              <enumeratedValues>
                <enumeratedValue>
                  <name>0</name>
                  <value>1</value>
                </enumeratedValue>
                <enumeratedValue>
                  <name>1</name>
                  <value>2</value>
                </enumeratedValue>
                <enumeratedValue>
                  <name>2</name>
                  <value>4</value>
                </enumeratedValue>
                <enumeratedValue>
                  <name>3</name>
                  <value>8</value>
                </enumeratedValue>
              </enumeratedValues>
            </field>
            <field>
              <name>ETPS</name>
              <bitRange>[13:12]</bitRange>
              <enumeratedValues>
                <enumeratedValue>
                  <name>0</name>
                  <value>1</value>
                </enumeratedValue>
                <enumeratedValue>
                  <name>1</name>
                  <value>2</value>
                </enumeratedValue>
              </enumeratedValues>
            </field>
            <field>
              <name>ECE</name>
              <bitRange>[14:14]</bitRange>
            </field>
            <field>
              <name>ETP</name>
              <bitRange>[15:15]</bitRange>
            </field>
            <field>
              <name>SMS_H</name>
              <bitRange>[16:16]</bitRange>
            </field>
            <field>
              <name>TS_H</name>
              <bitRange>[21:20]</bitRange>
            </field>
            <field>
              <name>SMSPE</name>
              <bitRange>[24:24]</bitRange>
            </field>
            <field>
              <name>SMSPS</name>
              <bitRange>[25:25]</bitRange>
            </field>
          </fields>
        </register>
        <register>
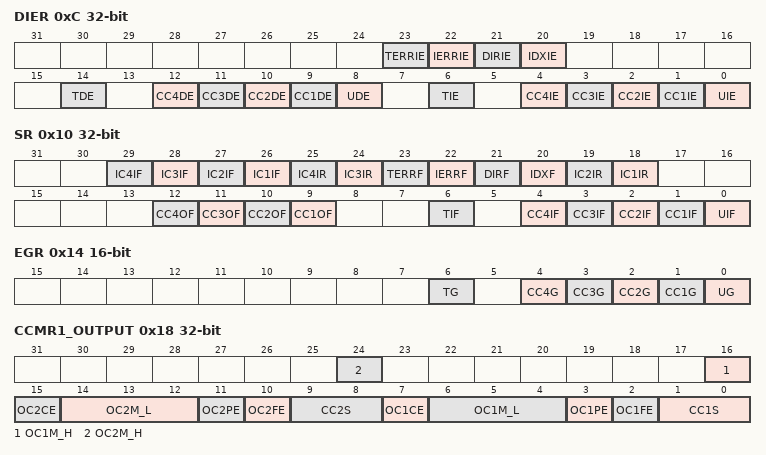
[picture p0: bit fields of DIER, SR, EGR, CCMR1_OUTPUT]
          <name>DIER</name>
          <description>desc DIER</description>
          <addressOffset>0xC</addressOffset>
          <fields>
            <field>
              <name>UIE</name>
              <bitRange>[0:0]</bitRange>
            </field>
            <field>
              <name>CC1IE</name>
              <bitRange>[1:1]</bitRange>
            </field>
            <field>
              <name>CC2IE</name>
              <bitRange>[2:2]</bitRange>
            </field>
            <field>
              <name>CC3IE</name>
              <bitRange>[3:3]</bitRange>
            </field>
            <field>
              <name>CC4IE</name>
              <bitRange>[4:4]</bitRange>
            </field>
            <field>
              <name>TIE</name>
              <bitRange>[6:6]</bitRange>
            </field>
            <field>
              <name>UDE</name>
              <bitRange>[8:8]</bitRange>
            </field>
            <field>
              <name>CC1DE</name>
              <bitRange>[9:9]</bitRange>
            </field>
            <field>
              <name>CC2DE</name>
              <bitRange>[10:10]</bitRange>
            </field>
            <field>
              <name>CC3DE</name>
              <bitRange>[11:11]</bitRange>
            </field>
            <field>
              <name>CC4DE</name>
              <bitRange>[12:12]</bitRange>
            </field>
            <field>
              <name>TDE</name>
              <bitRange>[14:14]</bitRange>
            </field>
            <field>
              <name>IDXIE</name>
              <bitRange>[20:20]</bitRange>
            </field>
            <field>
              <name>DIRIE</name>
              <bitRange>[21:21]</bitRange>
            </field>
            <field>
              <name>IERRIE</name>
              <bitRange>[22:22]</bitRange>
            </field>
            <field>
              <name>TERRIE</name>
              <bitRange>[23:23]</bitRange>
            </field>
          </fields>
        </register>
        <register>
          <name>SR</name>
          <description>desc SR</description>
          <addressOffset>0x10</addressOffset>
          <fields>
            <field>
              <name>UIF</name>
              <bitRange>[0:0]</bitRange>
            </field>
            <field>
              <name>CC1IF</name>
              <bitRange>[1:1]</bitRange>
            </field>
            <field>
              <name>CC2IF</name>
              <bitRange>[2:2]</bitRange>
            </field>
            <field>
              <name>CC3IF</name>
              <bitRange>[3:3]</bitRange>
            </field>
            <field>
              <name>CC4IF</name>
              <bitRange>[4:4]</bitRange>
            </field>
            <field>
              <name>TIF</name>
              <bitRange>[6:6]</bitRange>
            </field>
            <field>
              <name>CC1OF</name>
              <bitRange>[9:9]</bitRange>
            </field>
            <field>
              <name>CC2OF</name>
              <bitRange>[10:10]</bitRange>
            </field>
            <field>
              <name>CC3OF</name>
              <bitRange>[11:11]</bitRange>
            </field>
            <field>
              <name>CC4OF</name>
              <bitRange>[12:12]</bitRange>
            </field>
            <field>
              <name>IC1IR</name>
              <bitRange>[18:18]</bitRange>
            </field>
            <field>
              <name>IC2IR</name>
              <bitRange>[19:19]</bitRange>
            </field>
            <field>
              <name>IDXF</name>
              <bitRange>[20:20]</bitRange>
            </field>
            <field>
              <name>DIRF</name>
              <bitRange>[21:21]</bitRange>
            </field>
            <field>
              <name>IERRF</name>
              <bitRange>[22:22]</bitRange>
            </field>
            <field>
              <name>TERRF</name>
              <bitRange>[23:23]</bitRange>
            </field>
            <field>
              <name>IC3IR</name>
              <bitRange>[24:24]</bitRange>
            </field>
            <field>
              <name>IC4IR</name>
              <bitRange>[25:25]</bitRange>
            </field>
            <field>
              <name>IC1IF</name>
              <bitRange>[26:26]</bitRange>
            </field>
            <field>
              <name>IC2IF</name>
              <bitRange>[27:27]</bitRange>
            </field>
            <field>
              <name>IC3IF</name>
              <bitRange>[28:28]</bitRange>
            </field>
            <field>
              <name>IC4IF</name>
              <bitRange>[29:29]</bitRange>
            </field>
          </fields>
        </register>
        <register>
          <name>EGR</name>
          <description>desc EGR</description>
          <addressOffset>0x14</addressOffset>
          <size>16</size>
          <fields>
            <field>
              <name>UG</name>
              <bitRange>[0:0]</bitRange>
              <access>read-only</access>
            </field>
            <field>
              <name>CC1G</name>
              <bitRange>[1:1]</bitRange>
              <access>read-only</access>
            </field>
            <field>
              <name>CC2G</name>
              <bitRange>[2:2]</bitRange>
              <access>read-only</access>
            </field>
            <field>
              <name>CC3G</name>
              <bitRange>[3:3]</bitRange>
              <access>read-only</access>
            </field>
            <field>
              <name>CC4G</name>
              <bitRange>[4:4]</bitRange>
              <access>read-only</access>
            </field>
            <field>
              <name>TG</name>
              <bitRange>[6:6]</bitRange>
              <access>read-only</access>
            </field>
          </fields>
        </register>
        <register>
          <name>CCMR1_OUTPUT</name>
          <description>desc CCMR1:OUTPUT</description>
          <addressOffset>0x18</addressOffset>
          <fields>
            <field>
              <name>CC1S</name>
              <bitRange>[1:0]</bitRange>
            </field>
            <field>
              <name>OC1FE</name>
              <bitRange>[2:2]</bitRange>
            </field>
            <field>
              <name>OC1PE</name>
              <bitRange>[3:3]</bitRange>
            </field>
            <field>
              <name>OC1M_L</name>
              <bitRange>[6:4]</bitRange>
            </field>
            <field>
              <name>OC1CE</name>
              <bitRange>[7:7]</bitRange>
            </field>
            <field>
              <name>CC2S</name>
              <bitRange>[9:8]</bitRange>
            </field>
            <field>
              <name>OC2FE</name>
              <bitRange>[10:10]</bitRange>
            </field>
            <field>
              <name>OC2PE</name>
              <bitRange>[11:11]</bitRange>
            </field>
            <field>
              <name>OC2M_L</name>
              <bitRange>[14:12]</bitRange>
            </field>
            <field>
              <name>OC2CE</name>
              <bitRange>[15:15]</bitRange>
            </field>
            <field>
              <name>OC1M_H</name>
              <bitRange>[16:16]</bitRange>
            </field>
            <field>
              <name>OC2M_H</name>
              <bitRange>[24:24]</bitRange>
            </field>
          </fields>
        </register>
        <register>
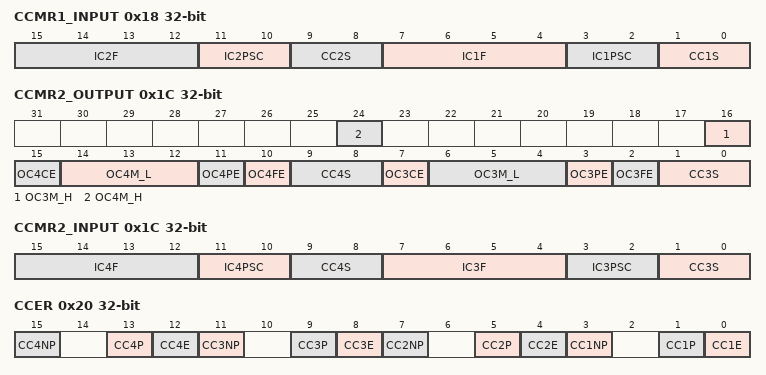
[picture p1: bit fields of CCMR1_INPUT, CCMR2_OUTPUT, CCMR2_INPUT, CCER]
          <name>CCMR1_INPUT</name>
          <description>desc CCMR1:INPUT</description>
          <alternateRegister>CCMR1_OUTPUT</alternateRegister>
          <addressOffset>0x18</addressOffset>
          <fields>
            <field>
              <name>CC1S</name>
              <bitRange>[1:0]</bitRange>
            </field>
            <field>
              <name>IC1PSC</name>
              <bitRange>[3:2]</bitRange>
            </field>
            <field>
              <name>IC1F</name>
              <bitRange>[7:4]</bitRange>
            </field>
            <field>
              <name>CC2S</name>
              <bitRange>[9:8]</bitRange>
            </field>
            <field>
              <name>IC2PSC</name>
              <bitRange>[11:10]</bitRange>
            </field>
            <field>
              <name>IC2F</name>
              <bitRange>[15:12]</bitRange>
            </field>
          </fields>
        </register>
        <register>
          <name>CCMR2_OUTPUT</name>
          <description>desc CCMR2:OUTPUT</description>
          <addressOffset>0x1C</addressOffset>
          <fields>
            <field>
              <name>CC3S</name>
              <bitRange>[1:0]</bitRange>
            </field>
            <field>
              <name>OC3FE</name>
              <bitRange>[2:2]</bitRange>
            </field>
            <field>
              <name>OC3PE</name>
              <bitRange>[3:3]</bitRange>
            </field>
            <field>
              <name>OC3M_L</name>
              <bitRange>[6:4]</bitRange>
            </field>
            <field>
              <name>OC3CE</name>
              <bitRange>[7:7]</bitRange>
            </field>
            <field>
              <name>CC4S</name>
              <bitRange>[9:8]</bitRange>
            </field>
            <field>
              <name>OC4FE</name>
              <bitRange>[10:10]</bitRange>
            </field>
            <field>
              <name>OC4PE</name>
              <bitRange>[11:11]</bitRange>
            </field>
            <field>
              <name>OC4M_L</name>
              <bitRange>[14:12]</bitRange>
            </field>
            <field>
              <name>OC4CE</name>
              <bitRange>[15:15]</bitRange>
            </field>
            <field>
              <name>OC3M_H</name>
              <bitRange>[16:16]</bitRange>
            </field>
            <field>
              <name>OC4M_H</name>
              <bitRange>[24:24]</bitRange>
            </field>
          </fields>
        </register>
        <register>
          <name>CCMR2_INPUT</name>
          <description>desc CCMR2:INPUT</description>
          <alternateRegister>CCMR2_OUTPUT</alternateRegister>
          <addressOffset>0x1C</addressOffset>
          <fields>
            <field>
              <name>CC3S</name>
              <bitRange>[1:0]</bitRange>
            </field>
            <field>
              <name>IC3PSC</name>
              <bitRange>[3:2]</bitRange>
            </field>
            <field>
              <name>IC3F</name>
              <bitRange>[7:4]</bitRange>
            </field>
            <field>
              <name>CC4S</name>
              <bitRange>[9:8]</bitRange>
            </field>
            <field>
              <name>IC4PSC</name>
              <bitRange>[11:10]</bitRange>
            </field>
            <field>
              <name>IC4F</name>
              <bitRange>[15:12]</bitRange>
            </field>
          </fields>
        </register>
        <register>
          <name>CCER</name>
          <description>desc CCER</description>
          <addressOffset>0x20</addressOffset>
          <fields>
            <field>
              <name>CC1E</name>
              <bitRange>[0:0]</bitRange>
            </field>
            <field>
              <name>CC1P</name>
              <bitRange>[1:1]</bitRange>
            </field>
            <field>
              <name>CC1NP</name>
              <bitRange>[3:3]</bitRange>
            </field>
            <field>
              <name>CC2E</name>
              <bitRange>[4:4]</bitRange>
            </field>
            <field>
              <name>CC2P</name>
              <bitRange>[5:5]</bitRange>
            </field>
            <field>
              <name>CC2NP</name>
              <bitRange>[7:7]</bitRange>
            </field>
            <field>
              <name>CC3E</name>
              <bitRange>[8:8]</bitRange>
            </field>
            <field>
              <name>CC3P</name>
              <bitRange>[9:9]</bitRange>
            </field>
            <field>
              <name>CC3NP</name>
              <bitRange>[11:11]</bitRange>
            </field>
            <field>
              <name>CC4E</name>
              <bitRange>[12:12]</bitRange>
            </field>
            <field>
              <name>CC4P</name>
              <bitRange>[13:13]</bitRange>
            </field>
            <field>
              <name>CC4NP</name>
              <bitRange>[15:15]</bitRange>
            </field>
          </fields>
        </register>
        <register>
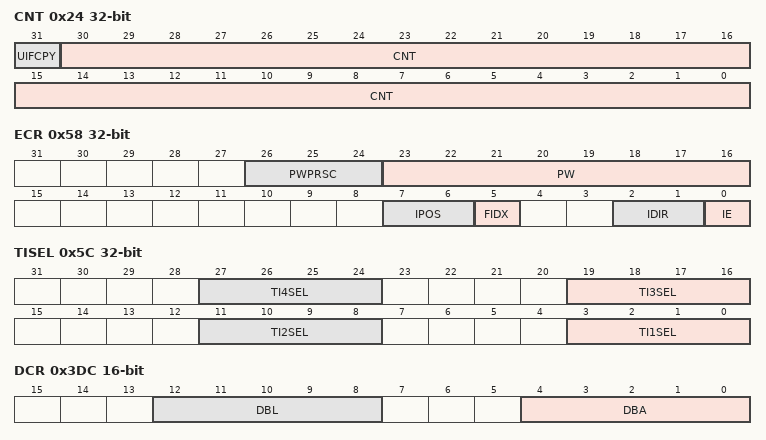
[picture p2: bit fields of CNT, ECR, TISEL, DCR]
          <name>CNT</name>
          <description>desc CNT</description>
          <addressOffset>0x24</addressOffset>
          <fields>
            <field>
              <name>CNT</name>
              <bitRange>[30:0]</bitRange>
            </field>
            <field>
              <name>UIFCPY</name>
              <bitRange>[31:31]</bitRange>
              <access>read-only</access>
            </field>
          </fields>
        </register>
        <register>
          <name>PSC</name>
          <description>desc PSC</description>
          <addressOffset>0x28</addressOffset>
          <fields>
            <field>
              <name>PSC</name>
              <bitRange>[15:0]</bitRange>
            </field>
          </fields>
        </register>
        <register>
          <name>ARR</name>
          <description>desc ARR</description>
          <addressOffset>0x2C</addressOffset>
          <fields>
            <field>
              <name>ARR</name>
              <bitRange>[31:0]</bitRange>
            </field>
          </fields>
        </register>
        <register>
          <name>CCR1</name>
          <description>desc CCR1</description>
          <addressOffset>0x34</addressOffset>
          <fields>
            <field>
              <name>CCR1</name>
              <bitRange>[31:0]</bitRange>
            </field>
          </fields>
        </register>
        <register>
          <name>CCR2</name>
          <description>desc CCR2</description>
          <addressOffset>0x38</addressOffset>
          <fields>
            <field>
              <name>CCR2</name>
              <bitRange>[31:0]</bitRange>
            </field>
          </fields>
        </register>
        <register>
          <name>CCR3</name>
          <description>desc CCR3</description>
          <addressOffset>0x3C</addressOffset>
          <fields>
            <field>
              <name>CCR3</name>
              <bitRange>[31:0]</bitRange>
            </field>
          </fields>
        </register>
        <register>
          <name>CCR4</name>
          <description>desc CCR4</description>
          <addressOffset>0x40</addressOffset>
          <fields>
            <field>
              <name>CCR4</name>
              <bitRange>[31:0]</bitRange>
            </field>
          </fields>
        </register>
        <register>
          <name>ECR</name>
          <addressOffset>0x58</addressOffset>
          <fields>
            <field>
              <name>IE</name>
              <bitRange>[0:0]</bitRange>
            </field>
            <field>
              <name>IDIR</name>
              <bitRange>[2:1]</bitRange>
              <enumeratedValues>
                <enumeratedValue>
                  <name>0</name>
                  <value>1</value>
                </enumeratedValue>
                <enumeratedValue>
                  <name>1</name>
                  <value>2</value>
                </enumeratedValue>
              </enumeratedValues>
            </field>
            <field>
              <name>FIDX</name>
              <bitRange>[5:5]</bitRange>
            </field>
            <field>
              <name>IPOS</name>
              <bitRange>[7:6]</bitRange>
              <enumeratedValues>
                <enumeratedValue>
                  <name>0</name>
                  <value>1</value>
                </enumeratedValue>
                <enumeratedValue>
                  <name>1</name>
                  <value>2</value>
                </enumeratedValue>
              </enumeratedValues>
            </field>
            <field>
              <name>PW</name>
              <bitRange>[23:16]</bitRange>
            </field>
            <field>
              <name>PWPRSC</name>
              <bitRange>[26:24]</bitRange>
              <enumeratedValues>
                <enumeratedValue>
                  <name>0</name>
                  <value>1</value>
                </enumeratedValue>
                <enumeratedValue>
                  <name>1</name>
                  <value>2</value>
                </enumeratedValue>
                <enumeratedValue>
                  <name>2</name>
                  <value>4</value>
                </enumeratedValue>
              </enumeratedValues>
            </field>
          </fields>
        </register>
        <register>
          <name>TISEL</name>
          <addressOffset>0x5C</addressOffset>
          <fields>
            <field>
              <name>TI1SEL</name>
              <bitRange>[3:0]</bitRange>
              <enumeratedValues>
                <enumeratedValue>
                  <name>0</name>
                  <value>1</value>
                </enumeratedValue>
                <enumeratedValue>
                  <name>1</name>
                  <value>2</value>
                </enumeratedValue>
                <enumeratedValue>
                  <name>2</name>
                  <value>4</value>
                </enumeratedValue>
                <enumeratedValue>
                  <name>3</name>
                  <value>8</value>
                </enumeratedValue>
              </enumeratedValues>
            </field>
            <field>
              <name>TI2SEL</name>
              <bitRange>[11:8]</bitRange>
              <enumeratedValues>
                <enumeratedValue>
                  <name>0</name>
                  <value>1</value>
                </enumeratedValue>
                <enumeratedValue>
                  <name>1</name>
                  <value>2</value>
                </enumeratedValue>
                <enumeratedValue>
                  <name>2</name>
                  <value>4</value>
                </enumeratedValue>
                <enumeratedValue>
                  <name>3</name>
                  <value>8</value>
                </enumeratedValue>
              </enumeratedValues>
            </field>
            <field>
              <name>TI3SEL</name>
              <bitRange>[19:16]</bitRange>
              <enumeratedValues>
                <enumeratedValue>
                  <name>0</name>
                  <value>1</value>
                </enumeratedValue>
                <enumeratedValue>
                  <name>1</name>
                  <value>2</value>
                </enumeratedValue>
                <enumeratedValue>
                  <name>2</name>
                  <value>4</value>
                </enumeratedValue>
                <enumeratedValue>
                  <name>3</name>
                  <value>8</value>
                </enumeratedValue>
              </enumeratedValues>
            </field>
            <field>
              <name>TI4SEL</name>
              <bitRange>[27:24]</bitRange>
              <enumeratedValues>
                <enumeratedValue>
                  <name>0</name>
                  <value>1</value>
                </enumeratedValue>
                <enumeratedValue>
                  <name>1</name>
                  <value>2</value>
                </enumeratedValue>
                <enumeratedValue>
                  <name>2</name>
                  <value>4</value>
                </enumeratedValue>
                <enumeratedValue>
                  <name>3</name>
                  <value>8</value>
                </enumeratedValue>
              </enumeratedValues>
            </field>
          </fields>
        </register>
        <register>
          <name>AF1</name>
          <addressOffset>0x60</addressOffset>
          <fields>
            <field>
              <name>ETRSEL</name>
              <bitRange>[17:14]</bitRange>
            </field>
          </fields>
        </register>
        <register>
          <name>AF2</name>
          <addressOffset>0x64</addressOffset>
          <fields>
            <field>
              <name>OCRSEL</name>
              <bitRange>[18:16]</bitRange>
            </field>
          </fields>
        </register>
        <register>
          <name>DCR</name>
          <description>desc DCR</description>
          <addressOffset>0x3DC</addressOffset>
          <size>16</size>
          <fields>
            <field>
              <name>DBA</name>
              <bitRange>[4:0]</bitRange>
              <enumeratedValues>
                <enumeratedValue>
                  <name>0</name>
                  <value>1</value>
                </enumeratedValue>
                <enumeratedValue>
                  <name>1</name>
                  <value>2</value>
                </enumeratedValue>
                <enumeratedValue>
                  <name>2</name>
                  <value>4</value>
                </enumeratedValue>
                <enumeratedValue>
                  <name>3</name>
                  <value>8</value>
                </enumeratedValue>
                <enumeratedValue>
                  <name>4</name>
                  <value>16</value>
                </enumeratedValue>
              </enumeratedValues>
            </field>
            <field>
              <name>DBL</name>
              <bitRange>[12:8]</bitRange>
              <enumeratedValues>
                <enumeratedValue>
                  <name>0</name>
                  <value>1</value>
                </enumeratedValue>
                <enumeratedValue>
                  <name>1</name>
                  <value>2</value>
                </enumeratedValue>
                <enumeratedValue>
                  <name>2</name>
                  <value>4</value>
                </enumeratedValue>
                <enumeratedValue>
                  <name>3</name>
                  <value>8</value>
                </enumeratedValue>
                <enumeratedValue>
                  <name>4</name>
                  <value>16</value>
                </enumeratedValue>
              </enumeratedValues>
            </field>
          </fields>
        </register>
        <register>
          <name>DMAR</name>
          <description>desc DMAR</description>
          <addressOffset>0x3E0</addressOffset>
          <fields>
            <field>
              <name>DMAB</name>
              <bitRange>[31:0]</bitRange>
            </field>
          </fields>
        </register>
      </registers>
    </peripheral>
    <peripheral derivedFrom="TIM2">
      <name>TIM3</name>
      <description>desc TIM</description>
      <baseAddress>0x40000400</baseAddress>
      <interrupt>
        <name>TIM3</name>
        <description>TIM3 global Interrupt</description>
        <value>29</value>
      </interrupt>
    </peripheral>
    <peripheral derivedFrom="TIM2">
      <name>TIM4</name>
      <description>desc TIM</description>
      <baseAddress>0x40000800</baseAddress>
      <interrupt>
        <name>TIM4</name>
        <description>TIM4 global Interrupt</description>
        <value>30</value>
      </interrupt>
    </peripheral>
    <peripheral derivedFrom="TIM2">
      <name>TIM5</name>
      <description>desc TIM</description>
      <baseAddress>0x40000C00</baseAddress>
      <interrupt>
        <name>TIM5</name>
        <description>TIM5 global Interrupt</description>
        <value>50</value>
      </interrupt>
    </peripheral>
    <peripheral>
      <name>TIM6</name>
      <description>desc TIM</description>
      <groupName>TIM</groupName>
      <baseAddress>0x40001000</baseAddress>
      <addressBlock>
        <offset>0x0</offset>
        <size>0x400</size>
        <usage>registers</usage>
      </addressBlock>
      <interrupt>
        <name>TIM6</name>
        <description>TIM6 global Interrupt</description>
        <value>54</value>
      </interrupt>
      <registers>
        <register>
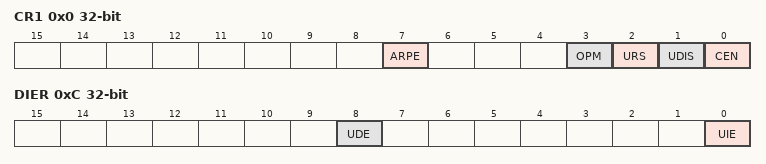
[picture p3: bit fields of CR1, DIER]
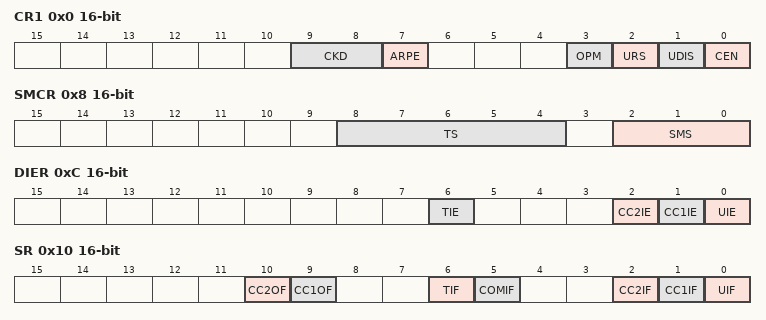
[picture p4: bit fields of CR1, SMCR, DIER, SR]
          <name>CR1</name>
          <description>desc CR1</description>
          <addressOffset>0x0</addressOffset>
          <fields>
            <field>
              <name>CEN</name>
              <bitRange>[0:0]</bitRange>
            </field>
            <field>
              <name>UDIS</name>
              <bitRange>[1:1]</bitRange>
            </field>
            <field>
              <name>URS</name>
              <bitRange>[2:2]</bitRange>
            </field>
            <field>
              <name>OPM</name>
              <bitRange>[3:3]</bitRange>
            </field>
            <field>
              <name>ARPE</name>
              <bitRange>[7:7]</bitRange>
            </field>
          </fields>
        </register>
        <register>
          <name>CR2</name>
          <description>desc CR2</description>
          <addressOffset>0x4</addressOffset>
          <fields>
            <field>
              <name>MMS</name>
              <bitRange>[6:4]</bitRange>
            </field>
          </fields>
        </register>
        <register>
          <name>DIER</name>
          <description>desc DIER</description>
          <addressOffset>0xC</addressOffset>
          <fields>
            <field>
              <name>UIE</name>
              <bitRange>[0:0]</bitRange>
            </field>
            <field>
              <name>UDE</name>
              <bitRange>[8:8]</bitRange>
            </field>
          </fields>
        </register>
        <register>
          <name>SR</name>
          <description>desc SR</description>
          <addressOffset>0x10</addressOffset>
          <fields>
            <field>
              <name>UIF</name>
              <bitRange>[0:0]</bitRange>
            </field>
          </fields>
        </register>
        <register>
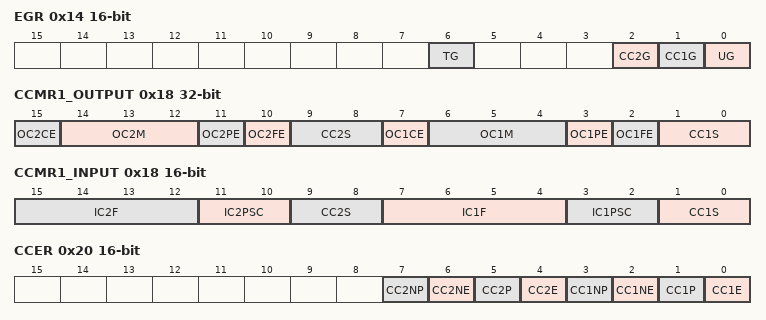
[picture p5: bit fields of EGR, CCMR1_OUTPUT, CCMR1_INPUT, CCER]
          <name>EGR</name>
          <description>desc EGR</description>
          <addressOffset>0x14</addressOffset>
          <fields>
            <field>
              <name>UG</name>
              <bitRange>[0:0]</bitRange>
            </field>
          </fields>
        </register>
        <register>
          <name>CNT</name>
          <description>desc CNT</description>
          <addressOffset>0x24</addressOffset>
          <fields>
            <field>
              <name>CNT</name>
              <bitRange>[15:0]</bitRange>
            </field>
          </fields>
        </register>
        <register>
          <name>PSC</name>
          <description>desc PSC</description>
          <addressOffset>0x28</addressOffset>
          <fields>
            <field>
              <name>PSC</name>
              <bitRange>[15:0]</bitRange>
            </field>
          </fields>
        </register>
        <register>
          <name>ARR</name>
          <description>desc ARR</description>
          <addressOffset>0x2C</addressOffset>
          <fields>
            <field>
              <name>ARR</name>
              <bitRange>[15:0]</bitRange>
            </field>
          </fields>
        </register>
      </registers>
    </peripheral>
    <peripheral derivedFrom="TIM6">
      <name>TIM7</name>
      <description>desc TIM</description>
      <baseAddress>0x40001400</baseAddress>
      <interrupt>
        <name>TIM7</name>
        <description>TIM7 global Interrupt</description>
        <value>55</value>
      </interrupt>
    </peripheral>
    <peripheral derivedFrom="TIM1">
      <name>TIM8</name>
      <baseAddress>0x40013400</baseAddress>
      <interrupt>
        <name>TIM8_BRK_TIM12</name>
        <description>TIM8 Break Interrupt and TIM12 global Interrupt</description>
        <value>43</value>
      </interrupt>
      <interrupt>
        <name>TIM8_UP_TIM13</name>
        <description>TIM8 Update Interrupt and TIM13 global Interrupt</description>
        <value>44</value>
      </interrupt>
      <interrupt>
        <name>TIM8_TRG_COM_TIM14</name>
        <description>TIM8 Trigger and Commutation Interrupt and TIM14 global interrupt</description>
        <value>45</value>
      </interrupt>
      <interrupt>
        <name>TIM8_CC</name>
        <description>TIM8 Capture Compare Interrupt</description>
        <value>46</value>
      </interrupt>
    </peripheral>
    <peripheral>
      <name>TIM9</name>
      <groupName>TIM</groupName>
      <baseAddress>0x40014C00</baseAddress>
      <addressBlock>
        <offset>0x0</offset>
        <size>0x400</size>
        <usage>registers</usage>
      </addressBlock>
      <interrupt>
        <name>TIM1_BRK_TIM9</name>
        <description>TIM1 Break Interrupt and TIM9 global Interrupt</description>
        <value>24</value>
      </interrupt>
      <registers>
        <register>
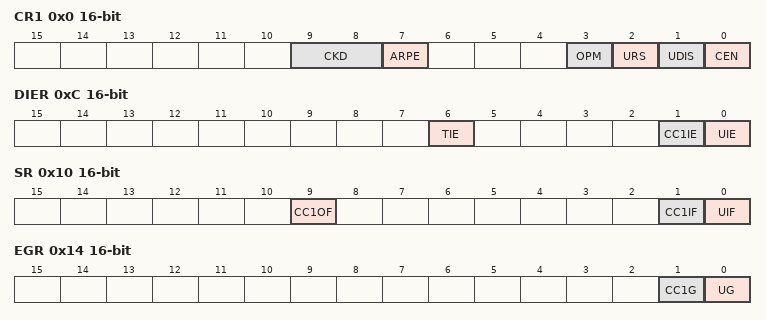
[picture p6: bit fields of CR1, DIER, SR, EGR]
          <name>CR1</name>
          <addressOffset>0x0</addressOffset>
          <size>16</size>
          <fields>
            <field>
              <name>CEN</name>
              <bitRange>[0:0]</bitRange>
            </field>
            <field>
              <name>UDIS</name>
              <bitRange>[1:1]</bitRange>
            </field>
            <field>
              <name>URS</name>
              <bitRange>[2:2]</bitRange>
            </field>
            <field>
              <name>OPM</name>
              <bitRange>[3:3]</bitRange>
            </field>
            <field>
              <name>ARPE</name>
              <bitRange>[7:7]</bitRange>
            </field>
            <field>
              <name>CKD</name>
              <bitRange>[9:8]</bitRange>
              <enumeratedValues>
                <enumeratedValue>
                  <name>0</name>
                  <value>1</value>
                </enumeratedValue>
                <enumeratedValue>
                  <name>1</name>
                  <value>2</value>
                </enumeratedValue>
              </enumeratedValues>
            </field>
          </fields>
        </register>
        <register>
          <name>SMCR</name>
          <addressOffset>0x8</addressOffset>
          <size>16</size>
          <fields>
            <field>
              <name>SMS</name>
              <bitRange>[2:0]</bitRange>
            </field>
            <field>
              <name>TS</name>
              <bitRange>[8:4]</bitRange>
            </field>
          </fields>
        </register>
        <register>
          <name>DIER</name>
          <addressOffset>0xC</addressOffset>
          <size>16</size>
          <fields>
            <field>
              <name>UIE</name>
              <bitRange>[0:0]</bitRange>
            </field>
            <field>
              <name>CC1IE</name>
              <bitRange>[1:1]</bitRange>
            </field>
            <field>
              <name>CC2IE</name>
              <bitRange>[2:2]</bitRange>
            </field>
            <field>
              <name>TIE</name>
              <bitRange>[6:6]</bitRange>
            </field>
          </fields>
        </register>
        <register>
          <name>SR</name>
          <addressOffset>0x10</addressOffset>
          <size>16</size>
          <fields>
            <field>
              <name>UIF</name>
              <bitRange>[0:0]</bitRange>
            </field>
            <field>
              <name>CC1IF</name>
              <bitRange>[1:1]</bitRange>
            </field>
            <field>
              <name>CC2IF</name>
              <bitRange>[2:2]</bitRange>
            </field>
            <field>
              <name>COMIF</name>
              <bitRange>[5:5]</bitRange>
            </field>
            <field>
              <name>TIF</name>
              <bitRange>[6:6]</bitRange>
            </field>
            <field>
              <name>CC1OF</name>
              <bitRange>[9:9]</bitRange>
            </field>
            <field>
              <name>CC2OF</name>
              <bitRange>[10:10]</bitRange>
            </field>
          </fields>
        </register>
        <register>
          <name>EGR</name>
          <addressOffset>0x14</addressOffset>
          <size>16</size>
          <fields>
            <field>
              <name>UG</name>
              <bitRange>[0:0]</bitRange>
            </field>
            <field>
              <name>CC1G</name>
              <bitRange>[1:1]</bitRange>
            </field>
            <field>
              <name>CC2G</name>
              <bitRange>[2:2]</bitRange>
            </field>
            <field>
              <name>TG</name>
              <bitRange>[6:6]</bitRange>
            </field>
          </fields>
        </register>
        <register>
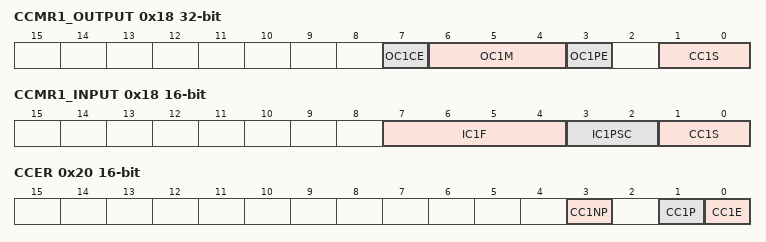
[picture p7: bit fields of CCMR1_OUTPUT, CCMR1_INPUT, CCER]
          <name>CCMR1_OUTPUT</name>
          <addressOffset>0x18</addressOffset>
          <fields>
            <field>
              <name>CC1S</name>
              <bitRange>[1:0]</bitRange>
            </field>
            <field>
              <name>OC1FE</name>
              <bitRange>[2:2]</bitRange>
            </field>
            <field>
              <name>OC1PE</name>
              <bitRange>[3:3]</bitRange>
            </field>
            <field>
              <name>OC1M</name>
              <bitRange>[6:4]</bitRange>
            </field>
            <field>
              <name>OC1CE</name>
              <bitRange>[7:7]</bitRange>
            </field>
            <field>
              <name>CC2S</name>
              <bitRange>[9:8]</bitRange>
            </field>
            <field>
              <name>OC2FE</name>
              <bitRange>[10:10]</bitRange>
            </field>
            <field>
              <name>OC2PE</name>
              <bitRange>[11:11]</bitRange>
            </field>
            <field>
              <name>OC2M</name>
              <bitRange>[14:12]</bitRange>
            </field>
            <field>
              <name>OC2CE</name>
              <bitRange>[15:15]</bitRange>
            </field>
          </fields>
        </register>
        <register>
          <name>CCMR1_INPUT</name>
          <alternateRegister>CCMR1_OUTPUT</alternateRegister>
          <addressOffset>0x18</addressOffset>
          <size>16</size>
          <fields>
            <field>
              <name>CC1S</name>
              <bitRange>[1:0]</bitRange>
            </field>
            <field>
              <name>IC1PSC</name>
              <bitRange>[3:2]</bitRange>
            </field>
            <field>
              <name>IC1F</name>
              <bitRange>[7:4]</bitRange>
            </field>
            <field>
              <name>CC2S</name>
              <bitRange>[9:8]</bitRange>
            </field>
            <field>
              <name>IC2PSC</name>
              <bitRange>[11:10]</bitRange>
            </field>
            <field>
              <name>IC2F</name>
              <bitRange>[15:12]</bitRange>
            </field>
          </fields>
        </register>
        <register>
          <name>CCER</name>
          <addressOffset>0x20</addressOffset>
          <size>16</size>
          <fields>
            <field>
              <name>CC1E</name>
              <bitRange>[0:0]</bitRange>
            </field>
            <field>
              <name>CC1P</name>
              <bitRange>[1:1]</bitRange>
            </field>
            <field>
              <name>CC1NE</name>
              <bitRange>[2:2]</bitRange>
            </field>
            <field>
              <name>CC1NP</name>
              <bitRange>[3:3]</bitRange>
            </field>
            <field>
              <name>CC2E</name>
              <bitRange>[4:4]</bitRange>
            </field>
            <field>
              <name>CC2P</name>
              <bitRange>[5:5]</bitRange>
            </field>
            <field>
              <name>CC2NE</name>
              <bitRange>[6:6]</bitRange>
            </field>
            <field>
              <name>CC2NP</name>
              <bitRange>[7:7]</bitRange>
            </field>
          </fields>
        </register>
        <register>
          <name>CNT</name>
          <addressOffset>0x24</addressOffset>
          <size>16</size>
          <fields>
            <field>
              <name>CNT</name>
              <bitRange>[15:0]</bitRange>
            </field>
          </fields>
        </register>
        <register>
          <name>PSC</name>
          <addressOffset>0x28</addressOffset>
          <size>16</size>
          <fields>
            <field>
              <name>PSC</name>
              <bitRange>[15:0]</bitRange>
            </field>
          </fields>
        </register>
        <register>
          <name>ARR</name>
          <addressOffset>0x2C</addressOffset>
          <size>16</size>
          <fields>
            <field>
              <name>ARR</name>
              <bitRange>[15:0]</bitRange>
            </field>
          </fields>
        </register>
        <register>
          <name>RCR</name>
          <addressOffset>0x30</addressOffset>
          <size>16</size>
          <fields>
            <field>
              <name>REP</name>
              <bitRange>[7:0]</bitRange>
            </field>
          </fields>
        </register>
        <register>
          <name>CCR1</name>
          <addressOffset>0x34</addressOffset>
          <size>16</size>
          <fields>
            <field>
              <name>CCR1</name>
              <bitRange>[15:0]</bitRange>
            </field>
          </fields>
        </register>
        <register>
          <name>CCR2</name>
          <addressOffset>0x38</addressOffset>
          <size>16</size>
          <fields>
            <field>
              <name>CCR2</name>
              <bitRange>[15:0]</bitRange>
            </field>
          </fields>
        </register>
      </registers>
    </peripheral>
    <peripheral>
      <name>TIM10</name>
      <groupName>TIM</groupName>
      <baseAddress>0x40015000</baseAddress>
      <addressBlock>
        <offset>0x0</offset>
        <size>0x400</size>
        <usage>registers</usage>
      </addressBlock>
      <interrupt>
        <name>TIM1_UP_TIM10</name>
        <description>TIM1 Update Interrupt and TIM10 global Interrupt</description>
        <value>25</value>
      </interrupt>
      <registers>
        <register>
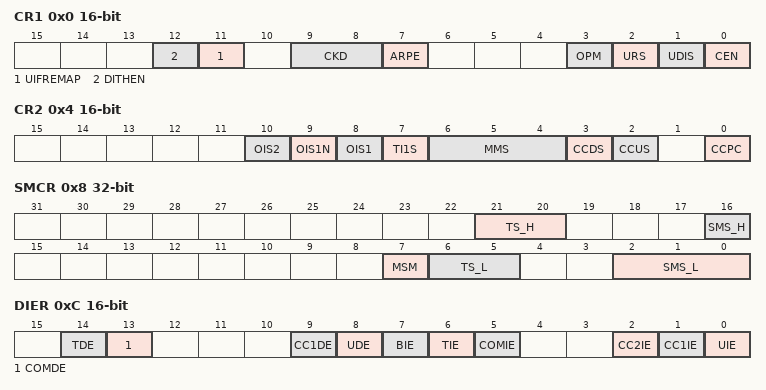
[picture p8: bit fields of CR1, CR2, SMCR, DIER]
          <name>CR1</name>
          <addressOffset>0x0</addressOffset>
          <size>16</size>
          <fields>
            <field>
              <name>CEN</name>
              <bitRange>[0:0]</bitRange>
            </field>
            <field>
              <name>UDIS</name>
              <bitRange>[1:1]</bitRange>
            </field>
            <field>
              <name>URS</name>
              <bitRange>[2:2]</bitRange>
            </field>
            <field>
              <name>OPM</name>
              <bitRange>[3:3]</bitRange>
            </field>
            <field>
              <name>ARPE</name>
              <bitRange>[7:7]</bitRange>
            </field>
            <field>
              <name>CKD</name>
              <bitRange>[9:8]</bitRange>
              <enumeratedValues>
                <enumeratedValue>
                  <name>0</name>
                  <value>1</value>
                </enumeratedValue>
                <enumeratedValue>
                  <name>1</name>
                  <value>2</value>
                </enumeratedValue>
              </enumeratedValues>
            </field>
          </fields>
        </register>
        <register>
          <name>DIER</name>
          <addressOffset>0xC</addressOffset>
          <size>16</size>
          <fields>
            <field>
              <name>UIE</name>
              <bitRange>[0:0]</bitRange>
            </field>
            <field>
              <name>CC1IE</name>
              <bitRange>[1:1]</bitRange>
            </field>
            <field>
              <name>TIE</name>
              <bitRange>[6:6]</bitRange>
            </field>
          </fields>
        </register>
        <register>
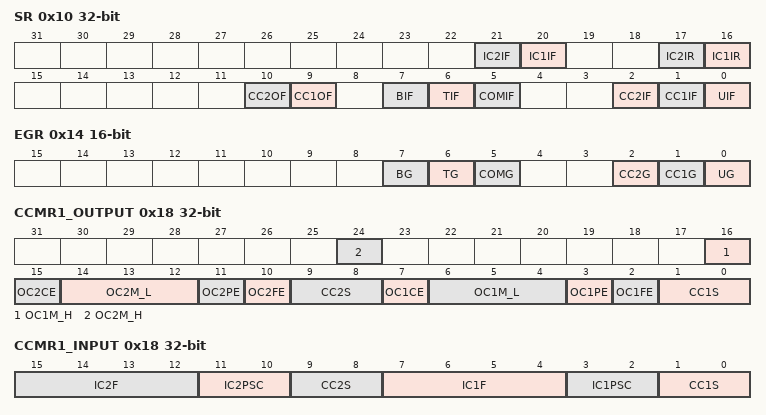
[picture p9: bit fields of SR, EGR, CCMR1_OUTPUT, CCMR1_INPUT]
          <name>SR</name>
          <addressOffset>0x10</addressOffset>
          <size>16</size>
          <fields>
            <field>
              <name>UIF</name>
              <bitRange>[0:0]</bitRange>
            </field>
            <field>
              <name>CC1IF</name>
              <bitRange>[1:1]</bitRange>
            </field>
            <field>
              <name>CC1OF</name>
              <bitRange>[9:9]</bitRange>
            </field>
          </fields>
        </register>
        <register>
          <name>EGR</name>
          <addressOffset>0x14</addressOffset>
          <size>16</size>
          <fields>
            <field>
              <name>UG</name>
              <bitRange>[0:0]</bitRange>
            </field>
            <field>
              <name>CC1G</name>
              <bitRange>[1:1]</bitRange>
            </field>
          </fields>
        </register>
        <register>
          <name>CCMR1_OUTPUT</name>
          <addressOffset>0x18</addressOffset>
          <fields>
            <field>
              <name>CC1S</name>
              <bitRange>[1:0]</bitRange>
            </field>
            <field>
              <name>OC1PE</name>
              <bitRange>[3:3]</bitRange>
            </field>
            <field>
              <name>OC1M</name>
              <bitRange>[6:4]</bitRange>
            </field>
            <field>
              <name>OC1CE</name>
              <bitRange>[7:7]</bitRange>
            </field>
          </fields>
        </register>
        <register>
          <name>CCMR1_INPUT</name>
          <alternateRegister>CCMR1_OUTPUT</alternateRegister>
          <addressOffset>0x18</addressOffset>
          <size>16</size>
          <fields>
            <field>
              <name>CC1S</name>
              <bitRange>[1:0]</bitRange>
            </field>
            <field>
              <name>IC1PSC</name>
              <bitRange>[3:2]</bitRange>
            </field>
            <field>
              <name>IC1F</name>
              <bitRange>[7:4]</bitRange>
            </field>
          </fields>
        </register>
        <register>
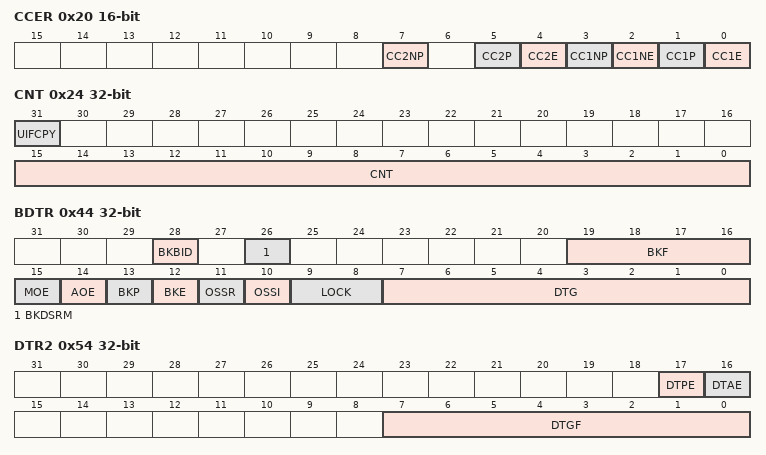
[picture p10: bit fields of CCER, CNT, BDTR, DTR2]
          <name>CCER</name>
          <addressOffset>0x20</addressOffset>
          <size>16</size>
          <fields>
            <field>
              <name>CC1E</name>
              <bitRange>[0:0]</bitRange>
            </field>
            <field>
              <name>CC1P</name>
              <bitRange>[1:1]</bitRange>
            </field>
            <field>
              <name>CC1NP</name>
              <bitRange>[3:3]</bitRange>
            </field>
          </fields>
        </register>
        <register>
          <name>CNT</name>
          <addressOffset>0x24</addressOffset>
          <size>16</size>
          <fields>
            <field>
              <name>CNT</name>
              <bitRange>[15:0]</bitRange>
            </field>
          </fields>
        </register>
        <register>
          <name>PSC</name>
          <addressOffset>0x28</addressOffset>
          <size>16</size>
          <fields>
            <field>
              <name>PSC</name>
              <bitRange>[15:0]</bitRange>
            </field>
          </fields>
        </register>
        <register>
          <name>ARR</name>
          <addressOffset>0x2C</addressOffset>
          <size>16</size>
          <fields>
            <field>
              <name>ARR</name>
              <bitRange>[15:0]</bitRange>
            </field>
          </fields>
        </register>
        <register>
          <name>CCR1</name>
          <addressOffset>0x34</addressOffset>
          <size>16</size>
          <fields>
            <field>
              <name>CCR1</name>
              <bitRange>[15:0]</bitRange>
            </field>
          </fields>
        </register>
        <register>
          <name>OR</name>
          <addressOffset>0x50</addressOffset>
          <size>16</size>
          <fields>
            <field>
              <name>TI1_RMP</name>
              <bitRange>[15:0]</bitRange>
            </field>
          </fields>
        </register>
      </registers>
    </peripheral>
    <peripheral derivedFrom="TIM10">
      <name>TIM11</name>
      <baseAddress>0x40015400</baseAddress>
    </peripheral>
    <peripheral derivedFrom="TIM9">
      <name>TIM12</name>
      <baseAddress>0x40001800</baseAddress>
    </peripheral>
    <peripheral derivedFrom="TIM10">
      <name>TIM13</name>
      <baseAddress>0x40001C00</baseAddress>
    </peripheral>
    <peripheral derivedFrom="TIM10">
      <name>TIM14</name>
      <baseAddress>0x40002000</baseAddress>
    </peripheral>
    <peripheral>
      <name>TIM15</name>
      <groupName>TIM</groupName>
      <baseAddress>0x40015800</baseAddress>
      <addressBlock>
        <offset>0x0</offset>
        <size>0x3F0</size>
        <usage>registers</usage>
      </addressBlock>
      <interrupt>
        <name>TIM15</name>
        <description>TIM15 global Interrupt</description>
        <value>60</value>
      </interrupt>
      <registers>
        <register>
          <name>CR1</name>
          <addressOffset>0x0</addressOffset>
          <size>16</size>
          <fields>
            <field>
              <name>CEN</name>
              <bitRange>[0:0]</bitRange>
            </field>
            <field>
              <name>UDIS</name>
              <bitRange>[1:1]</bitRange>
            </field>
            <field>
              <name>URS</name>
              <bitRange>[2:2]</bitRange>
            </field>
            <field>
              <name>OPM</name>
              <bitRange>[3:3]</bitRange>
            </field>
            <field>
              <name>ARPE</name>
              <bitRange>[7:7]</bitRange>
            </field>
            <field>
              <name>CKD</name>
              <bitRange>[9:8]</bitRange>
              <enumeratedValues>
                <enumeratedValue>
                  <name>0</name>
                  <value>1</value>
                </enumeratedValue>
                <enumeratedValue>
                  <name>1</name>
                  <value>2</value>
                </enumeratedValue>
              </enumeratedValues>
            </field>
            <field>
              <name>UIFREMAP</name>
              <bitRange>[11:11]</bitRange>
            </field>
            <field>
              <name>DITHEN</name>
              <bitRange>[12:12]</bitRange>
            </field>
          </fields>
        </register>
        <register>
          <name>CR2</name>
          <addressOffset>0x4</addressOffset>
          <size>16</size>
          <fields>
            <field>
              <name>CCPC</name>
              <bitRange>[0:0]</bitRange>
            </field>
            <field>
              <name>CCUS</name>
              <bitRange>[2:2]</bitRange>
            </field>
            <field>
              <name>CCDS</name>
              <bitRange>[3:3]</bitRange>
            </field>
            <field>
              <name>MMS</name>
              <bitRange>[6:4]</bitRange>
              <access>read-only</access>
            </field>
            <field>
              <name>TI1S</name>
              <bitRange>[7:7]</bitRange>
            </field>
            <field>
              <name>OIS1</name>
              <bitRange>[8:8]</bitRange>
            </field>
            <field>
              <name>OIS1N</name>
              <bitRange>[9:9]</bitRange>
            </field>
            <field>
              <name>OIS2</name>
              <bitRange>[10:10]</bitRange>
            </field>
          </fields>
        </register>
        <register>
          <name>SMCR</name>
          <addressOffset>0x8</addressOffset>
          <fields>
            <field>
              <name>SMS_L</name>
              <bitRange>[2:0]</bitRange>
            </field>
            <field>
              <name>TS_L</name>
              <bitRange>[6:5]</bitRange>
            </field>
            <field>
              <name>MSM</name>
              <bitRange>[7:7]</bitRange>
            </field>
            <field>
              <name>SMS_H</name>
              <bitRange>[16:16]</bitRange>
            </field>
            <field>
              <name>TS_H</name>
              <bitRange>[21:20]</bitRange>
            </field>
          </fields>
        </register>
        <register>
          <name>DIER</name>
          <addressOffset>0xC</addressOffset>
          <size>16</size>
          <fields>
            <field>
              <name>UIE</name>
              <bitRange>[0:0]</bitRange>
            </field>
            <field>
              <name>CC1IE</name>
              <bitRange>[1:1]</bitRange>
            </field>
            <field>
              <name>CC2IE</name>
              <bitRange>[2:2]</bitRange>
            </field>
            <field>
              <name>COMIE</name>
              <bitRange>[5:5]</bitRange>
            </field>
            <field>
              <name>TIE</name>
              <bitRange>[6:6]</bitRange>
            </field>
            <field>
              <name>BIE</name>
              <bitRange>[7:7]</bitRange>
            </field>
            <field>
              <name>UDE</name>
              <bitRange>[8:8]</bitRange>
            </field>
            <field>
              <name>CC1DE</name>
              <bitRange>[9:9]</bitRange>
            </field>
            <field>
              <name>COMDE</name>
              <bitRange>[13:13]</bitRange>
            </field>
            <field>
              <name>TDE</name>
              <bitRange>[14:14]</bitRange>
            </field>
          </fields>
        </register>
        <register>
          <name>SR</name>
          <addressOffset>0x10</addressOffset>
          <fields>
            <field>
              <name>UIF</name>
              <bitRange>[0:0]</bitRange>
            </field>
            <field>
              <name>CC1IF</name>
              <bitRange>[1:1]</bitRange>
            </field>
            <field>
              <name>CC2IF</name>
              <bitRange>[2:2]</bitRange>
            </field>
            <field>
              <name>COMIF</name>
              <bitRange>[5:5]</bitRange>
            </field>
            <field>
              <name>TIF</name>
              <bitRange>[6:6]</bitRange>
            </field>
            <field>
              <name>BIF</name>
              <bitRange>[7:7]</bitRange>
            </field>
            <field>
              <name>CC1OF</name>
              <bitRange>[9:9]</bitRange>
            </field>
            <field>
              <name>CC2OF</name>
              <bitRange>[10:10]</bitRange>
            </field>
            <field>
              <name>IC1IR</name>
              <bitRange>[16:16]</bitRange>
            </field>
            <field>
              <name>IC2IR</name>
              <bitRange>[17:17]</bitRange>
            </field>
            <field>
              <name>IC1IF</name>
              <bitRange>[20:20]</bitRange>
            </field>
            <field>
              <name>IC2IF</name>
              <bitRange>[21:21]</bitRange>
            </field>
          </fields>
        </register>
        <register>
          <name>EGR</name>
          <addressOffset>0x14</addressOffset>
          <size>16</size>
          <fields>
            <field>
              <name>UG</name>
              <bitRange>[0:0]</bitRange>
              <access>read-only</access>
            </field>
            <field>
              <name>CC1G</name>
              <bitRange>[1:1]</bitRange>
              <access>read-only</access>
            </field>
            <field>
              <name>CC2G</name>
              <bitRange>[2:2]</bitRange>
              <access>read-only</access>
            </field>
            <field>
              <name>COMG</name>
              <bitRange>[5:5]</bitRange>
              <access>read-only</access>
            </field>
            <field>
              <name>TG</name>
              <bitRange>[6:6]</bitRange>
              <access>read-only</access>
            </field>
            <field>
              <name>BG</name>
              <bitRange>[7:7]</bitRange>
              <access>read-only</access>
            </field>
          </fields>
        </register>
        <register>
          <name>CCMR1_OUTPUT</name>
          <addressOffset>0x18</addressOffset>
          <fields>
            <field>
              <name>CC1S</name>
              <bitRange>[1:0]</bitRange>
            </field>
            <field>
              <name>OC1FE</name>
              <bitRange>[2:2]</bitRange>
            </field>
            <field>
              <name>OC1PE</name>
              <bitRange>[3:3]</bitRange>
            </field>
            <field>
              <name>OC1M_L</name>
              <bitRange>[6:4]</bitRange>
            </field>
            <field>
              <name>OC1CE</name>
              <bitRange>[7:7]</bitRange>
            </field>
            <field>
              <name>CC2S</name>
              <bitRange>[9:8]</bitRange>
            </field>
            <field>
              <name>OC2FE</name>
              <bitRange>[10:10]</bitRange>
            </field>
            <field>
              <name>OC2PE</name>
              <bitRange>[11:11]</bitRange>
            </field>
            <field>
              <name>OC2M_L</name>
              <bitRange>[14:12]</bitRange>
            </field>
            <field>
              <name>OC2CE</name>
              <bitRange>[15:15]</bitRange>
            </field>
            <field>
              <name>OC1M_H</name>
              <bitRange>[16:16]</bitRange>
            </field>
            <field>
              <name>OC2M_H</name>
              <bitRange>[24:24]</bitRange>
            </field>
          </fields>
        </register>
        <register>
          <name>CCMR1_INPUT</name>
          <alternateRegister>CCMR1_OUTPUT</alternateRegister>
          <addressOffset>0x18</addressOffset>
          <fields>
            <field>
              <name>CC1S</name>
              <bitRange>[1:0]</bitRange>
            </field>
            <field>
              <name>IC1PSC</name>
              <bitRange>[3:2]</bitRange>
            </field>
            <field>
              <name>IC1F</name>
              <bitRange>[7:4]</bitRange>
            </field>
            <field>
              <name>CC2S</name>
              <bitRange>[9:8]</bitRange>
            </field>
            <field>
              <name>IC2PSC</name>
              <bitRange>[11:10]</bitRange>
            </field>
            <field>
              <name>IC2F</name>
              <bitRange>[15:12]</bitRange>
            </field>
          </fields>
        </register>
        <register>
          <name>CCER</name>
          <addressOffset>0x20</addressOffset>
          <size>16</size>
          <fields>
            <field>
              <name>CC1E</name>
              <bitRange>[0:0]</bitRange>
            </field>
            <field>
              <name>CC1P</name>
              <bitRange>[1:1]</bitRange>
            </field>
            <field>
              <name>CC1NE</name>
              <bitRange>[2:2]</bitRange>
            </field>
            <field>
              <name>CC1NP</name>
              <bitRange>[3:3]</bitRange>
            </field>
            <field>
              <name>CC2E</name>
              <bitRange>[4:4]</bitRange>
            </field>
            <field>
              <name>CC2P</name>
              <bitRange>[5:5]</bitRange>
            </field>
            <field>
              <name>CC2NP</name>
              <bitRange>[7:7]</bitRange>
            </field>
          </fields>
        </register>
        <register>
          <name>CNT</name>
          <addressOffset>0x24</addressOffset>
          <fields>
            <field>
              <name>CNT</name>
              <bitRange>[15:0]</bitRange>
            </field>
            <field>
              <name>UIFCPY</name>
              <bitRange>[31:31]</bitRange>
              <access>read-only</access>
            </field>
          </fields>
        </register>
        <register>
          <name>PSC</name>
          <addressOffset>0x28</addressOffset>
          <fields>
            <field>
              <name>PSC</name>
              <bitRange>[15:0]</bitRange>
            </field>
          </fields>
        </register>
        <register>
          <name>ARR</name>
          <addressOffset>0x2C</addressOffset>
          <fields>
            <field>
              <name>ARR</name>
              <bitRange>[19:0]</bitRange>
            </field>
          </fields>
        </register>
        <register>
          <name>RCR</name>
          <addressOffset>0x30</addressOffset>
          <fields>
            <field>
              <name>REP</name>
              <bitRange>[7:0]</bitRange>
            </field>
          </fields>
        </register>
        <register>
          <name>CCR1</name>
          <addressOffset>0x34</addressOffset>
          <fields>
            <field>
              <name>CCR1</name>
              <bitRange>[19:0]</bitRange>
            </field>
          </fields>
        </register>
        <register>
          <name>CCR2</name>
          <addressOffset>0x38</addressOffset>
          <fields>
            <field>
              <name>CCR2</name>
              <bitRange>[19:0]</bitRange>
            </field>
          </fields>
        </register>
        <register>
          <name>BDTR</name>
          <addressOffset>0x44</addressOffset>
          <fields>
            <field>
              <name>DTG</name>
              <bitRange>[7:0]</bitRange>
            </field>
            <field>
              <name>LOCK</name>
              <bitRange>[9:8]</bitRange>
              <enumeratedValues>
                <enumeratedValue>
                  <name>0</name>
                  <value>1</value>
                </enumeratedValue>
                <enumeratedValue>
                  <name>1</name>
                  <value>2</value>
                </enumeratedValue>
              </enumeratedValues>
            </field>
            <field>
              <name>OSSI</name>
              <bitRange>[10:10]</bitRange>
            </field>
            <field>
              <name>OSSR</name>
              <bitRange>[11:11]</bitRange>
            </field>
            <field>
              <name>BKE</name>
              <bitRange>[12:12]</bitRange>
            </field>
            <field>
              <name>BKP</name>
              <bitRange>[13:13]</bitRange>
            </field>
            <field>
              <name>AOE</name>
              <bitRange>[14:14]</bitRange>
            </field>
            <field>
              <name>MOE</name>
              <bitRange>[15:15]</bitRange>
            </field>
            <field>
              <name>BKF</name>
              <bitRange>[19:16]</bitRange>
              <enumeratedValues>
                <enumeratedValue>
                  <name>0</name>
                  <value>1</value>
                </enumeratedValue>
                <enumeratedValue>
                  <name>1</name>
                  <value>2</value>
                </enumeratedValue>
                <enumeratedValue>
                  <name>2</name>
                  <value>4</value>
                </enumeratedValue>
                <enumeratedValue>
                  <name>3</name>
                  <value>8</value>
                </enumeratedValue>
              </enumeratedValues>
            </field>
            <field>
              <name>BKDSRM</name>
              <bitRange>[26:26]</bitRange>
            </field>
            <field>
              <name>BKBID</name>
              <bitRange>[28:28]</bitRange>
            </field>
          </fields>
        </register>
        <register>
          <name>DTR2</name>
          <addressOffset>0x54</addressOffset>
          <fields>
            <field>
              <name>DTGF</name>
              <bitRange>[7:0]</bitRange>
            </field>
            <field>
              <name>DTAE</name>
              <bitRange>[16:16]</bitRange>
            </field>
            <field>
              <name>DTPE</name>
              <bitRange>[17:17]</bitRange>
            </field>
          </fields>
        </register>
        <register>
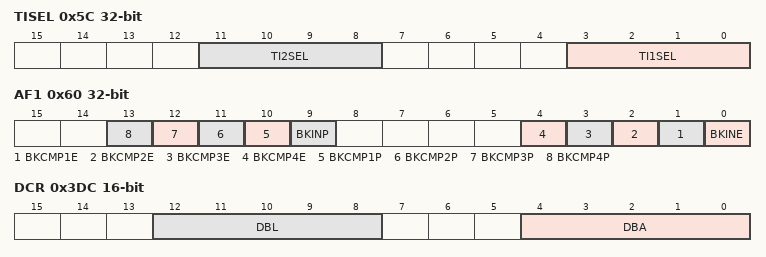
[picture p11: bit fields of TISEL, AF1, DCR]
          <name>TISEL</name>
          <addressOffset>0x5C</addressOffset>
          <fields>
            <field>
              <name>TI1SEL</name>
              <bitRange>[3:0]</bitRange>
              <enumeratedValues>
                <enumeratedValue>
                  <name>0</name>
                  <value>1</value>
                </enumeratedValue>
                <enumeratedValue>
                  <name>1</name>
                  <value>2</value>
                </enumeratedValue>
                <enumeratedValue>
                  <name>2</name>
                  <value>4</value>
                </enumeratedValue>
                <enumeratedValue>
                  <name>3</name>
                  <value>8</value>
                </enumeratedValue>
              </enumeratedValues>
            </field>
            <field>
              <name>TI2SEL</name>
              <bitRange>[11:8]</bitRange>
              <enumeratedValues>
                <enumeratedValue>
                  <name>0</name>
                  <value>1</value>
                </enumeratedValue>
                <enumeratedValue>
                  <name>1</name>
                  <value>2</value>
                </enumeratedValue>
                <enumeratedValue>
                  <name>2</name>
                  <value>4</value>
                </enumeratedValue>
                <enumeratedValue>
                  <name>3</name>
                  <value>8</value>
                </enumeratedValue>
              </enumeratedValues>
            </field>
          </fields>
        </register>
        <register>
          <name>AF1</name>
          <addressOffset>0x60</addressOffset>
          <fields>
            <field>
              <name>BKINE</name>
              <bitRange>[0:0]</bitRange>
            </field>
            <field>
              <name>BKCMP1E</name>
              <bitRange>[1:1]</bitRange>
            </field>
            <field>
              <name>BKCMP2E</name>
              <bitRange>[2:2]</bitRange>
            </field>
            <field>
              <name>BKCMP3E</name>
              <bitRange>[3:3]</bitRange>
            </field>
            <field>
              <name>BKCMP4E</name>
              <bitRange>[4:4]</bitRange>
            </field>
            <field>
              <name>BKINP</name>
              <bitRange>[9:9]</bitRange>
            </field>
            <field>
              <name>BKCMP1P</name>
              <bitRange>[10:10]</bitRange>
            </field>
            <field>
              <name>BKCMP2P</name>
              <bitRange>[11:11]</bitRange>
            </field>
            <field>
              <name>BKCMP3P</name>
              <bitRange>[12:12]</bitRange>
            </field>
            <field>
              <name>BKCMP4P</name>
              <bitRange>[13:13]</bitRange>
            </field>
          </fields>
        </register>
        <register>
          <name>AF2</name>
          <addressOffset>0x64</addressOffset>
          <fields>
            <field>
              <name>OCRSEL</name>
              <bitRange>[18:16]</bitRange>
            </field>
          </fields>
        </register>
        <register>
          <name>DCR</name>
          <addressOffset>0x3DC</addressOffset>
          <size>16</size>
          <fields>
            <field>
              <name>DBA</name>
              <bitRange>[4:0]</bitRange>
              <enumeratedValues>
                <enumeratedValue>
                  <name>0</name>
                  <value>1</value>
                </enumeratedValue>
                <enumeratedValue>
                  <name>1</name>
                  <value>2</value>
                </enumeratedValue>
                <enumeratedValue>
                  <name>2</name>
                  <value>4</value>
                </enumeratedValue>
                <enumeratedValue>
                  <name>3</name>
                  <value>8</value>
                </enumeratedValue>
                <enumeratedValue>
                  <name>4</name>
                  <value>16</value>
                </enumeratedValue>
              </enumeratedValues>
            </field>
            <field>
              <name>DBL</name>
              <bitRange>[12:8]</bitRange>
              <enumeratedValues>
                <enumeratedValue>
                  <name>0</name>
                  <value>1</value>
                </enumeratedValue>
                <enumeratedValue>
                  <name>1</name>
                  <value>2</value>
                </enumeratedValue>
                <enumeratedValue>
                  <name>2</name>
                  <value>4</value>
                </enumeratedValue>
                <enumeratedValue>
                  <name>3</name>
                  <value>8</value>
                </enumeratedValue>
                <enumeratedValue>
                  <name>4</name>
                  <value>16</value>
                </enumeratedValue>
              </enumeratedValues>
            </field>
          </fields>
        </register>
        <register>
          <name>DMAR</name>
          <addressOffset>0x3E0</addressOffset>
          <fields>
            <field>
              <name>DMAB</name>
              <bitRange>[31:0]</bitRange>
            </field>
          </fields>
        </register>
      </registers>
    </peripheral>
    <peripheral>
      <name>TIM16</name>
      <groupName>TIM</groupName>
      <baseAddress>0x40015C00</baseAddress>
      <addressBlock>
        <offset>0x0</offset>
        <size>0x3F0</size>
        <usage>registers</usage>
      </addressBlock>
      <interrupt>
        <name>TIM16</name>
        <description>TIM16 global Interrupt</description>
        <value>61</value>
      </interrupt>
      <registers>
        <register>
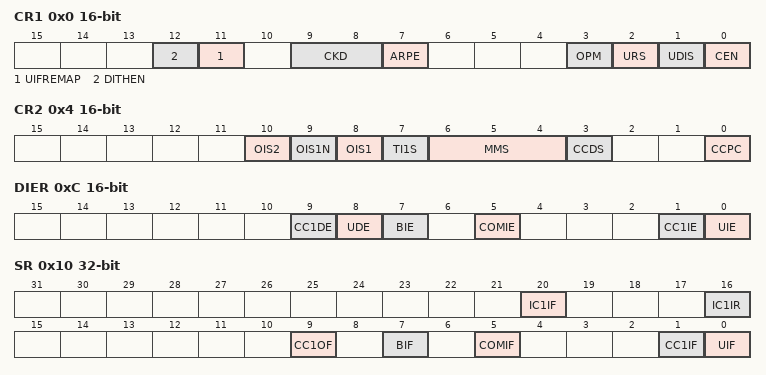
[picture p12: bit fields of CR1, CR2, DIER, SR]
          <name>CR1</name>
          <addressOffset>0x0</addressOffset>
          <size>16</size>
          <fields>
            <field>
              <name>CEN</name>
              <bitRange>[0:0]</bitRange>
            </field>
            <field>
              <name>UDIS</name>
              <bitRange>[1:1]</bitRange>
            </field>
            <field>
              <name>URS</name>
              <bitRange>[2:2]</bitRange>
            </field>
            <field>
              <name>OPM</name>
              <bitRange>[3:3]</bitRange>
            </field>
            <field>
              <name>ARPE</name>
              <bitRange>[7:7]</bitRange>
            </field>
            <field>
              <name>CKD</name>
              <bitRange>[9:8]</bitRange>
              <enumeratedValues>
                <enumeratedValue>
                  <name>0</name>
                  <value>1</value>
                </enumeratedValue>
                <enumeratedValue>
                  <name>1</name>
                  <value>2</value>
                </enumeratedValue>
              </enumeratedValues>
            </field>
            <field>
              <name>UIFREMAP</name>
              <bitRange>[11:11]</bitRange>
            </field>
            <field>
              <name>DITHEN</name>
              <bitRange>[12:12]</bitRange>
            </field>
          </fields>
        </register>
        <register>
          <name>CR2</name>
          <addressOffset>0x4</addressOffset>
          <size>16</size>
          <fields>
            <field>
              <name>CCPC</name>
              <bitRange>[0:0]</bitRange>
            </field>
            <field>
              <name>CCDS</name>
              <bitRange>[3:3]</bitRange>
            </field>
            <field>
              <name>MMS</name>
              <bitRange>[6:4]</bitRange>
              <access>read-only</access>
            </field>
            <field>
              <name>TI1S</name>
              <bitRange>[7:7]</bitRange>
            </field>
            <field>
              <name>OIS1</name>
              <bitRange>[8:8]</bitRange>
            </field>
            <field>
              <name>OIS1N</name>
              <bitRange>[9:9]</bitRange>
            </field>
            <field>
              <name>OIS2</name>
              <bitRange>[10:10]</bitRange>
            </field>
          </fields>
        </register>
        <register>
          <name>DIER</name>
          <addressOffset>0xC</addressOffset>
          <size>16</size>
          <fields>
            <field>
              <name>UIE</name>
              <bitRange>[0:0]</bitRange>
            </field>
            <field>
              <name>CC1IE</name>
              <bitRange>[1:1]</bitRange>
            </field>
            <field>
              <name>COMIE</name>
              <bitRange>[5:5]</bitRange>
            </field>
            <field>
              <name>BIE</name>
              <bitRange>[7:7]</bitRange>
            </field>
            <field>
              <name>UDE</name>
              <bitRange>[8:8]</bitRange>
            </field>
            <field>
              <name>CC1DE</name>
              <bitRange>[9:9]</bitRange>
            </field>
          </fields>
        </register>
        <register>
          <name>SR</name>
          <addressOffset>0x10</addressOffset>
          <fields>
            <field>
              <name>UIF</name>
              <bitRange>[0:0]</bitRange>
            </field>
            <field>
              <name>CC1IF</name>
              <bitRange>[1:1]</bitRange>
            </field>
            <field>
              <name>COMIF</name>
              <bitRange>[5:5]</bitRange>
            </field>
            <field>
              <name>BIF</name>
              <bitRange>[7:7]</bitRange>
            </field>
            <field>
              <name>CC1OF</name>
              <bitRange>[9:9]</bitRange>
            </field>
            <field>
              <name>IC1IR</name>
              <bitRange>[16:16]</bitRange>
            </field>
            <field>
              <name>IC1IF</name>
              <bitRange>[20:20]</bitRange>
            </field>
          </fields>
        </register>
        <register>
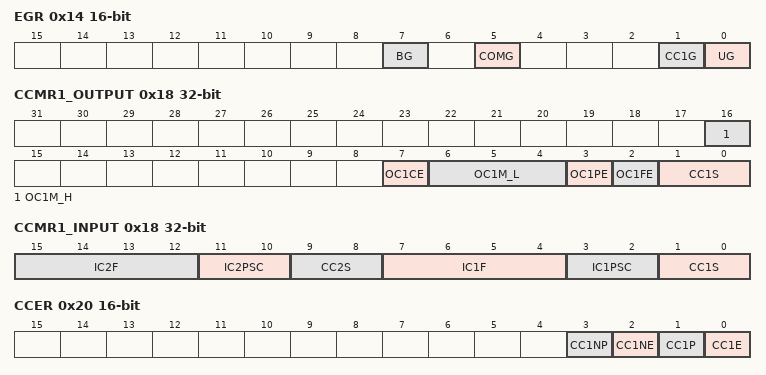
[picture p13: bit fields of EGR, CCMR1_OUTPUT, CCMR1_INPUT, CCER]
          <name>EGR</name>
          <addressOffset>0x14</addressOffset>
          <size>16</size>
          <fields>
            <field>
              <name>UG</name>
              <bitRange>[0:0]</bitRange>
              <access>read-only</access>
            </field>
            <field>
              <name>CC1G</name>
              <bitRange>[1:1]</bitRange>
              <access>read-only</access>
            </field>
            <field>
              <name>COMG</name>
              <bitRange>[5:5]</bitRange>
              <access>read-only</access>
            </field>
            <field>
              <name>BG</name>
              <bitRange>[7:7]</bitRange>
              <access>read-only</access>
            </field>
          </fields>
        </register>
        <register>
          <name>CCMR1_OUTPUT</name>
          <addressOffset>0x18</addressOffset>
          <fields>
            <field>
              <name>CC1S</name>
              <bitRange>[1:0]</bitRange>
            </field>
            <field>
              <name>OC1FE</name>
              <bitRange>[2:2]</bitRange>
            </field>
            <field>
              <name>OC1PE</name>
              <bitRange>[3:3]</bitRange>
            </field>
            <field>
              <name>OC1M_L</name>
              <bitRange>[6:4]</bitRange>
            </field>
            <field>
              <name>OC1CE</name>
              <bitRange>[7:7]</bitRange>
            </field>
            <field>
              <name>OC1M_H</name>
              <bitRange>[16:16]</bitRange>
            </field>
          </fields>
        </register>
        <register>
          <name>CCMR1_INPUT</name>
          <alternateRegister>CCMR1_OUTPUT</alternateRegister>
          <addressOffset>0x18</addressOffset>
          <fields>
            <field>
              <name>CC1S</name>
              <bitRange>[1:0]</bitRange>
            </field>
            <field>
              <name>IC1PSC</name>
              <bitRange>[3:2]</bitRange>
            </field>
            <field>
              <name>IC1F</name>
              <bitRange>[7:4]</bitRange>
            </field>
            <field>
              <name>CC2S</name>
              <bitRange>[9:8]</bitRange>
            </field>
            <field>
              <name>IC2PSC</name>
              <bitRange>[11:10]</bitRange>
            </field>
            <field>
              <name>IC2F</name>
              <bitRange>[15:12]</bitRange>
            </field>
          </fields>
        </register>
        <register>
          <name>CCER</name>
          <addressOffset>0x20</addressOffset>
          <size>16</size>
          <fields>
            <field>
              <name>CC1E</name>
              <bitRange>[0:0]</bitRange>
            </field>
            <field>
              <name>CC1P</name>
              <bitRange>[1:1]</bitRange>
            </field>
            <field>
              <name>CC1NE</name>
              <bitRange>[2:2]</bitRange>
            </field>
            <field>
              <name>CC1NP</name>
              <bitRange>[3:3]</bitRange>
            </field>
          </fields>
        </register>
        <register>
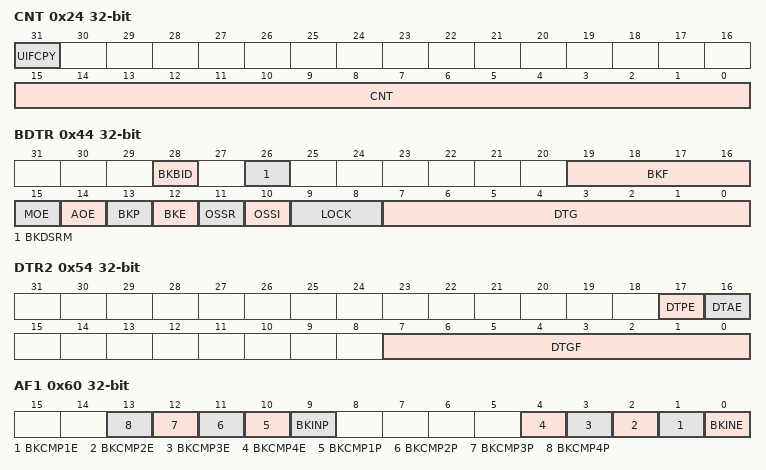
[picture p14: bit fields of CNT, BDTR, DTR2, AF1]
          <name>CNT</name>
          <addressOffset>0x24</addressOffset>
          <fields>
            <field>
              <name>CNT</name>
              <bitRange>[15:0]</bitRange>
            </field>
            <field>
              <name>UIFCPY</name>
              <bitRange>[31:31]</bitRange>
              <access>read-only</access>
            </field>
          </fields>
        </register>
        <register>
          <name>PSC</name>
          <addressOffset>0x28</addressOffset>
          <fields>
            <field>
              <name>PSC</name>
              <bitRange>[15:0]</bitRange>
            </field>
          </fields>
        </register>
        <register>
          <name>ARR</name>
          <addressOffset>0x2C</addressOffset>
          <fields>
            <field>
              <name>ARR</name>
              <bitRange>[19:0]</bitRange>
            </field>
          </fields>
        </register>
        <register>
          <name>RCR</name>
          <addressOffset>0x30</addressOffset>
          <fields>
            <field>
              <name>REP</name>
              <bitRange>[7:0]</bitRange>
            </field>
          </fields>
        </register>
        <register>
          <name>CCR1</name>
          <addressOffset>0x34</addressOffset>
          <fields>
            <field>
              <name>CCR1</name>
              <bitRange>[19:0]</bitRange>
            </field>
          </fields>
        </register>
        <register>
          <name>BDTR</name>
          <addressOffset>0x44</addressOffset>
          <fields>
            <field>
              <name>DTG</name>
              <bitRange>[7:0]</bitRange>
            </field>
            <field>
              <name>LOCK</name>
              <bitRange>[9:8]</bitRange>
              <enumeratedValues>
                <enumeratedValue>
                  <name>0</name>
                  <value>1</value>
                </enumeratedValue>
                <enumeratedValue>
                  <name>1</name>
                  <value>2</value>
                </enumeratedValue>
              </enumeratedValues>
            </field>
            <field>
              <name>OSSI</name>
              <bitRange>[10:10]</bitRange>
            </field>
            <field>
              <name>OSSR</name>
              <bitRange>[11:11]</bitRange>
            </field>
            <field>
              <name>BKE</name>
              <bitRange>[12:12]</bitRange>
            </field>
            <field>
              <name>BKP</name>
              <bitRange>[13:13]</bitRange>
            </field>
            <field>
              <name>AOE</name>
              <bitRange>[14:14]</bitRange>
            </field>
            <field>
              <name>MOE</name>
              <bitRange>[15:15]</bitRange>
            </field>
            <field>
              <name>BKF</name>
              <bitRange>[19:16]</bitRange>
              <enumeratedValues>
                <enumeratedValue>
                  <name>0</name>
                  <value>1</value>
                </enumeratedValue>
                <enumeratedValue>
                  <name>1</name>
                  <value>2</value>
                </enumeratedValue>
                <enumeratedValue>
                  <name>2</name>
                  <value>4</value>
                </enumeratedValue>
                <enumeratedValue>
                  <name>3</name>
                  <value>8</value>
                </enumeratedValue>
              </enumeratedValues>
            </field>
            <field>
              <name>BKDSRM</name>
              <bitRange>[26:26]</bitRange>
            </field>
            <field>
              <name>BKBID</name>
              <bitRange>[28:28]</bitRange>
            </field>
          </fields>
        </register>
        <register>
          <name>DTR2</name>
          <addressOffset>0x54</addressOffset>
          <fields>
            <field>
              <name>DTGF</name>
              <bitRange>[7:0]</bitRange>
            </field>
            <field>
              <name>DTAE</name>
              <bitRange>[16:16]</bitRange>
            </field>
            <field>
              <name>DTPE</name>
              <bitRange>[17:17]</bitRange>
            </field>
          </fields>
        </register>
        <register>
          <name>TISEL</name>
          <addressOffset>0x5C</addressOffset>
          <fields>
            <field>
              <name>TI1SEL</name>
              <bitRange>[3:0]</bitRange>
              <enumeratedValues>
                <enumeratedValue>
                  <name>0</name>
                  <value>1</value>
                </enumeratedValue>
                <enumeratedValue>
                  <name>1</name>
                  <value>2</value>
                </enumeratedValue>
                <enumeratedValue>
                  <name>2</name>
                  <value>4</value>
                </enumeratedValue>
                <enumeratedValue>
                  <name>3</name>
                  <value>8</value>
                </enumeratedValue>
              </enumeratedValues>
            </field>
          </fields>
        </register>
        <register>
          <name>AF1</name>
          <addressOffset>0x60</addressOffset>
          <fields>
            <field>
              <name>BKINE</name>
              <bitRange>[0:0]</bitRange>
            </field>
            <field>
              <name>BKCMP1E</name>
              <bitRange>[1:1]</bitRange>
            </field>
            <field>
              <name>BKCMP2E</name>
              <bitRange>[2:2]</bitRange>
            </field>
            <field>
              <name>BKCMP3E</name>
              <bitRange>[3:3]</bitRange>
            </field>
            <field>
              <name>BKCMP4E</name>
              <bitRange>[4:4]</bitRange>
            </field>
            <field>
              <name>BKINP</name>
              <bitRange>[9:9]</bitRange>
            </field>
            <field>
              <name>BKCMP1P</name>
              <bitRange>[10:10]</bitRange>
            </field>
            <field>
              <name>BKCMP2P</name>
              <bitRange>[11:11]</bitRange>
            </field>
            <field>
              <name>BKCMP3P</name>
              <bitRange>[12:12]</bitRange>
            </field>
            <field>
              <name>BKCMP4P</name>
              <bitRange>[13:13]</bitRange>
            </field>
          </fields>
        </register>
        <register>
          <name>AF2</name>
          <addressOffset>0x64</addressOffset>
          <fields>
            <field>
              <name>OCRSEL</name>
              <bitRange>[18:16]</bitRange>
            </field>
          </fields>
        </register>
        <register>
          <name>OR1</name>
          <addressOffset>0x68</addressOffset>
          <fields>
            <field>
              <name>HSE32EN</name>
              <bitRange>[0:0]</bitRange>
            </field>
          </fields>
        </register>
        <register>
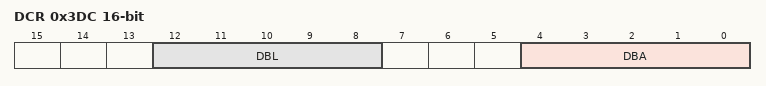
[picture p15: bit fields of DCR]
          <name>DCR</name>
          <addressOffset>0x3DC</addressOffset>
          <size>16</size>
          <fields>
            <field>
              <name>DBA</name>
              <bitRange>[4:0]</bitRange>
              <enumeratedValues>
                <enumeratedValue>
                  <name>0</name>
                  <value>1</value>
                </enumeratedValue>
                <enumeratedValue>
                  <name>1</name>
                  <value>2</value>
                </enumeratedValue>
                <enumeratedValue>
                  <name>2</name>
                  <value>4</value>
                </enumeratedValue>
                <enumeratedValue>
                  <name>3</name>
                  <value>8</value>
                </enumeratedValue>
                <enumeratedValue>
                  <name>4</name>
                  <value>16</value>
                </enumeratedValue>
              </enumeratedValues>
            </field>
            <field>
              <name>DBL</name>
              <bitRange>[12:8]</bitRange>
              <enumeratedValues>
                <enumeratedValue>
                  <name>0</name>
                  <value>1</value>
                </enumeratedValue>
                <enumeratedValue>
                  <name>1</name>
                  <value>2</value>
                </enumeratedValue>
                <enumeratedValue>
                  <name>2</name>
                  <value>4</value>
                </enumeratedValue>
                <enumeratedValue>
                  <name>3</name>
                  <value>8</value>
                </enumeratedValue>
                <enumeratedValue>
                  <name>4</name>
                  <value>16</value>
                </enumeratedValue>
              </enumeratedValues>
            </field>
          </fields>
        </register>
        <register>
          <name>DMAR</name>
          <addressOffset>0x3E0</addressOffset>
          <fields>
            <field>
              <name>DMAB</name>
              <bitRange>[31:0]</bitRange>
            </field>
          </fields>
        </register>
      </registers>
    </peripheral>
    <peripheral derivedFrom="TIM16">
      <name>TIM17</name>
      <baseAddress>0x40016000</baseAddress>
      <interrupt>
        <name>TIM17</name>
        <description>TIM17 global Interrupt</description>
        <value>62</value>
      </interrupt>
    </peripheral>
    <peripheral derivedFrom="TIM2">
      <name>TIM18</name>
      <baseAddress>0x40002400</baseAddress>
      <interrupt>
        <name>TIM18</name>
        <description>TIM18 global Interrupt</description>
        <value>22</value>
      </interrupt>
    </peripheral>
    <peripheral derivedFrom="TIM10">
      <name>TIM19</name>
      <baseAddress>0x40016400</baseAddress>
      <interrupt>
        <name>TIM19</name>
        <description>TIM19 global Interrupt</description>
        <value>42</value>
      </interrupt>
    </peripheral>
    <peripheral>
      <name>UART1</name>
      <groupName>UART</groupName>
      <baseAddress>0x40004C00</baseAddress>
      <addressBlock>
        <offset>0x0</offset>
        <size>0x400</size>
        <usage>registers</usage>
      </addressBlock>
      <interrupt>
        <name>UART1</name>
        <description>UART1 global Interrupt</description>
        <value>52</value>
      </interrupt>
      <registers>
        <register>
          <name>DR</name>
          <addressOffset>0x0</addressOffset>
          <fields>
            <field>
              <name>DR</name>
              <description>Receive/send data register</description>
              <bitRange>[8:0]</bitRange>
            </field>
          </fields>
        </register>
        <register>
          <name>BRR</name>
          <addressOffset>0x4</addressOffset>
          <fields>
            <field>
              <name>BRR</name>
              <description>Baud rate register</description>
              <bitRange>[15:0]</bitRange>
            </field>
          </fields>
        </register>
        <register>
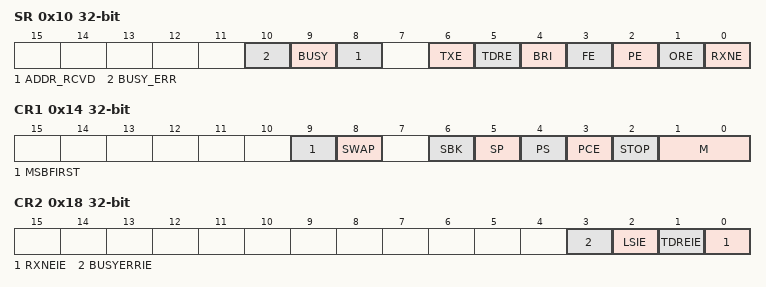
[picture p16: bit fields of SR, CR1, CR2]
          <name>SR</name>
          <addressOffset>0x10</addressOffset>
          <fields>
            <field>
              <name>RXNE</name>
              <description>Receive register not empty</description>
              <bitRange>[0:0]</bitRange>
              <access>read-only</access>
            </field>
            <field>
              <name>ORE</name>
              <description>Overrun error bit</description>
              <bitRange>[1:1]</bitRange>
            </field>
            <field>
              <name>PE</name>
              <description>Parity Error bit</description>
              <bitRange>[2:2]</bitRange>
            </field>
            <field>
              <name>FE</name>
              <description>Framing Error bit</description>
              <bitRange>[3:3]</bitRange>
            </field>
            <field>
              <name>BRI</name>
              <description>Break Interrupt bit</description>
              <bitRange>[4:4]</bitRange>
            </field>
            <field>
              <name>TDRE</name>
              <description>Transmit Holding Register Empty bit</description>
              <bitRange>[5:5]</bitRange>
              <access>read-only</access>
            </field>
            <field>
              <name>TXE</name>
              <description>Transmitter Empty bit</description>
              <bitRange>[6:6]</bitRange>
              <access>read-only</access>
            </field>
            <field>
              <name>ADDR_RCVD</name>
              <description>Address Received Bit</description>
              <bitRange>[8:8]</bitRange>
            </field>
            <field>
              <name>BUSY</name>
              <description>UART Busy</description>
              <bitRange>[9:9]</bitRange>
              <access>read-only</access>
            </field>
            <field>
              <name>BUSY_ERR</name>
              <description>Busy Detect Error</description>
              <bitRange>[10:10]</bitRange>
            </field>
          </fields>
        </register>
        <register>
          <name>CR1</name>
          <addressOffset>0x14</addressOffset>
          <fields>
            <field>
              <name>M</name>
              <description>Data Length Select</description>
              <bitRange>[1:0]</bitRange>
              <enumeratedValues>
                <enumeratedValue>
                  <name>0</name>
                  <value>1</value>
                </enumeratedValue>
                <enumeratedValue>
                  <name>1</name>
                  <value>2</value>
                </enumeratedValue>
              </enumeratedValues>
            </field>
            <field>
              <name>STOP</name>
              <description>Number of stop bits</description>
              <bitRange>[2:2]</bitRange>
            </field>
            <field>
              <name>PCE</name>
              <description>Parity Enable</description>
              <bitRange>[3:3]</bitRange>
            </field>
            <field>
              <name>PS</name>
              <description>Even Parity Select</description>
              <bitRange>[4:4]</bitRange>
            </field>
            <field>
              <name>SP</name>
              <description>Stick Parity</description>
              <bitRange>[5:5]</bitRange>
            </field>
            <field>
              <name>SBK</name>
              <description>Send Break</description>
              <bitRange>[6:6]</bitRange>
            </field>
            <field>
              <name>SWAP</name>
              <description>TX/RX pin swap</description>
              <bitRange>[8:8]</bitRange>
            </field>
            <field>
              <name>MSBFIRST</name>
              <description>MSB first mode</description>
              <bitRange>[9:9]</bitRange>
            </field>
          </fields>
        </register>
        <register>
          <name>CR2</name>
          <addressOffset>0x18</addressOffset>
          <fields>
            <field>
              <name>RXNEIE</name>
              <description>Enable Received Data Available Interrupt</description>
              <bitRange>[0:0]</bitRange>
            </field>
            <field>
              <name>TDREIE</name>
              <description>Enable Transmit Holding Register Empty Interrupt</description>
              <bitRange>[1:1]</bitRange>
            </field>
            <field>
              <name>LSIE</name>
              <description>Enable Receiver Line Status Interrupt</description>
              <bitRange>[2:2]</bitRange>
            </field>
            <field>
              <name>BUSYERRIE</name>
              <description>Enable Busyerr state interruption</description>
              <bitRange>[3:3]</bitRange>
            </field>
          </fields>
        </register>
        <register>
          <name>CR3</name>
          <addressOffset>0x1C</addressOffset>
          <fields>
            <field>
              <name>M_E</name>
              <description>Extension for DLS</description>
              <bitRange>[0:0]</bitRange>
            </field>
            <field>
              <name>ADDR_MATCH</name>
              <description>Address Match Mode</description>
              <bitRange>[1:1]</bitRange>
            </field>
            <field>
              <name>SEND_ADDR</name>
              <description>Send address control bit</description>
              <bitRange>[2:2]</bitRange>
            </field>
            <field>
              <name>TX_MODE</name>
              <description>Transmit mode control bit</description>
              <bitRange>[3:3]</bitRange>
            </field>
            <field>
              <name>DMAR</name>
              <description>DMA receive enable</description>
              <bitRange>[4:4]</bitRange>
            </field>
            <field>
              <name>DMAT</name>
              <description>DMA transmit enable</description>
              <bitRange>[5:5]</bitRange>
            </field>
            <field>
              <name>DMA_SOFT_ACK</name>
              <description>DMA software ack</description>
              <bitRange>[6:6]</bitRange>
            </field>
          </fields>
        </register>
        <register>
          <name>RAR</name>
          <addressOffset>0x20</addressOffset>
          <fields>
            <field>
              <name>RAR</name>
              <description>Receive address matching register</description>
              <bitRange>[7:0]</bitRange>
            </field>
          </fields>
        </register>
        <register>
          <name>TAR</name>
          <addressOffset>0x24</addressOffset>
          <fields>
            <field>
              <name>TAR</name>
              <description>Transmit address matching register</description>
              <bitRange>[7:0]</bitRange>
            </field>
          </fields>
        </register>
        <register>
          <name>BRRF</name>
          <addressOffset>0x28</addressOffset>
          <fields>
            <field>
              <name>BRRF</name>
              <description>Baud rate fractional register</description>
              <bitRange>[3:0]</bitRange>
              <enumeratedValues>
                <enumeratedValue>
                  <name>0</name>
                  <value>1</value>
                </enumeratedValue>
                <enumeratedValue>
                  <name>1</name>
                  <value>2</value>
                </enumeratedValue>
                <enumeratedValue>
                  <name>2</name>
                  <value>4</value>
                </enumeratedValue>
                <enumeratedValue>
                  <name>3</name>
                  <value>8</value>
                </enumeratedValue>
              </enumeratedValues>
            </field>
          </fields>
        </register>
      </registers>
    </peripheral>
    <peripheral derivedFrom="UART1">
      <name>UART2</name>
      <baseAddress>0x40005000</baseAddress>
      <interrupt>
        <name>UART2</name>
        <description>UART2 global Interrupt</description>
        <value>77</value>
      </interrupt>
    </peripheral>
    <peripheral derivedFrom="UART1">
      <name>UART3</name>
      <baseAddress>0x40005C00</baseAddress>
      <interrupt>
        <name>UART3</name>
        <description>UART3 global Interrupt</description>
        <value>78</value>
      </interrupt>
    </peripheral>
    <peripheral>
      <name>USART1</name>
      <groupName>USART</groupName>
      <baseAddress>0x40013800</baseAddress>
      <addressBlock>
        <offset>0x0</offset>
        <size>0x400</size>
        <usage>registers</usage>
      </addressBlock>
      <interrupt>
        <name>USART1</name>
        <description>USART1 global Interrupt</description>
        <value>37</value>
      </interrupt>
      <registers>
        <register>
          <name>SR</name>
          <addressOffset>0x0</addressOffset>
          <fields>
            <field>
              <name>PE</name>
              <description>Parity error</description>
              <bitRange>[0:0]</bitRange>
              <access>read-only</access>
            </field>
            <field>
              <name>FE</name>
              <description>Framing error</description>
              <bitRange>[1:1]</bitRange>
              <access>read-only</access>
            </field>
            <field>
              <name>NE</name>
              <description>Noise error flag</description>
              <bitRange>[2:2]</bitRange>
              <access>read-only</access>
            </field>
            <field>
              <name>ORE</name>
              <description>overrun error</description>
              <bitRange>[3:3]</bitRange>
              <access>read-only</access>
            </field>
            <field>
              <name>IDLE</name>
              <description>idle</description>
              <bitRange>[4:4]</bitRange>
              <access>read-only</access>
            </field>
            <field>
              <name>RXNE_RXFNF</name>
              <description>Read data register not empty</description>
              <bitRange>[5:5]</bitRange>
              <access>read-only</access>
            </field>
            <field>
              <name>TC</name>
              <description>Transmission complete</description>
              <bitRange>[6:6]</bitRange>
              <access>read-only</access>
            </field>
            <field>
              <name>TXE_TXFNF</name>
              <description>Transmit data register empty</description>
              <bitRange>[7:7]</bitRange>
              <access>read-only</access>
            </field>
            <field>
              <name>LBD</name>
              <description>LIN break detection flag</description>
              <bitRange>[8:8]</bitRange>
            </field>
            <field>
              <name>CTS</name>
              <description>cts flag</description>
              <bitRange>[9:9]</bitRange>
            </field>
            <field>
              <name>ABRF</name>
              <description>auto baud rate flag</description>
              <bitRange>[10:10]</bitRange>
              <access>read-only</access>
            </field>
            <field>
              <name>ABRE</name>
              <description>auto baud rateerror</description>
              <bitRange>[11:11]</bitRange>
              <access>read-only</access>
            </field>
            <field>
              <name>ABRQ</name>
              <description>auto baud rate req</description>
              <bitRange>[12:12]</bitRange>
              <access>read-only</access>
            </field>
            <field>
              <name>TXFT</name>
              <description>txfifo threshold flag</description>
              <bitRange>[13:13]</bitRange>
              <access>read-only</access>
            </field>
            <field>
              <name>RXFT</name>
              <description>rxfifo threshoold flag</description>
              <bitRange>[14:14]</bitRange>
              <access>read-only</access>
            </field>
            <field>
              <name>RXFF</name>
              <description>rxfifo full</description>
              <bitRange>[15:15]</bitRange>
              <access>read-only</access>
            </field>
            <field>
              <name>TXFE</name>
              <description>txfifo empty</description>
              <bitRange>[16:16]</bitRange>
              <access>read-only</access>
            </field>
            <field>
              <name>EOBF</name>
              <description>end of block flag</description>
              <bitRange>[18:18]</bitRange>
            </field>
            <field>
              <name>RTOF</name>
              <description>rto flag</description>
              <bitRange>[19:19]</bitRange>
            </field>
          </fields>
        </register>
        <register>
          <name>TDR</name>
          <addressOffset>0x4</addressOffset>
          <fields>
            <field>
              <name>TDR</name>
              <description>tdr</description>
              <bitRange>[8:0]</bitRange>
            </field>
          </fields>
        </register>
        <register>
          <name>BRR</name>
          <addressOffset>0x8</addressOffset>
          <fields>
            <field>
              <name>DIV_F</name>
              <description>DIV_Fraction</description>
              <bitRange>[3:0]</bitRange>
              <enumeratedValues>
                <enumeratedValue>
                  <name>0</name>
                  <value>1</value>
                </enumeratedValue>
                <enumeratedValue>
                  <name>1</name>
                  <value>2</value>
                </enumeratedValue>
                <enumeratedValue>
                  <name>2</name>
                  <value>4</value>
                </enumeratedValue>
                <enumeratedValue>
                  <name>3</name>
                  <value>8</value>
                </enumeratedValue>
              </enumeratedValues>
            </field>
            <field>
              <name>DIV_M</name>
              <description>DIV_Mantissa</description>
              <bitRange>[15:4]</bitRange>
            </field>
          </fields>
        </register>
        <register>
          <name>CR1</name>
          <addressOffset>0xC</addressOffset>
          <fields>
            <field>
              <name>SBK</name>
              <description>Send break</description>
              <bitRange>[0:0]</bitRange>
            </field>
            <field>
              <name>RWU</name>
              <description>Receiver wakeup</description>
              <bitRange>[1:1]</bitRange>
              <access>read-only</access>
            </field>
            <field>
              <name>RE</name>
              <description>Receiver enable</description>
              <bitRange>[2:2]</bitRange>
            </field>
            <field>
              <name>TE</name>
              <description>Transmitter enable</description>
              <bitRange>[3:3]</bitRange>
            </field>
            <field>
              <name>IDLEIE</name>
              <description>IDLE interrupt enable</description>
              <bitRange>[4:4]</bitRange>
            </field>
            <field>
              <name>RXNEIE</name>
              <description>RXNE interrupt enable</description>
              <bitRange>[5:5]</bitRange>
            </field>
            <field>
              <name>TCIE</name>
              <description>send complete int enable</description>
              <bitRange>[6:6]</bitRange>
            </field>
            <field>
              <name>TXEIE</name>
              <description>txe</description>
              <bitRange>[7:7]</bitRange>
            </field>
            <field>
              <name>PEIE</name>
              <description>PE interrupt enable</description>
              <bitRange>[8:8]</bitRange>
            </field>
            <field>
              <name>PS</name>
              <description>Parity selection</description>
              <bitRange>[9:9]</bitRange>
            </field>
            <field>
              <name>PCE</name>
              <description>Parity control enable</description>
              <bitRange>[10:10]</bitRange>
            </field>
            <field>
              <name>WAKE</name>
              <description>Wakeup method</description>
              <bitRange>[11:11]</bitRange>
            </field>
            <field>
              <name>M0</name>
              <description>word length</description>
              <bitRange>[12:12]</bitRange>
            </field>
            <field>
              <name>UE</name>
              <description>uesart enable</description>
              <bitRange>[13:13]</bitRange>
            </field>
            <field>
              <name>M1</name>
              <description>word length</description>
              <bitRange>[14:14]</bitRange>
            </field>
            <field>
              <name>MSB</name>
              <description>msb</description>
              <bitRange>[15:15]</bitRange>
            </field>
            <field>
              <name>MMRQ</name>
              <description>mm request</description>
              <bitRange>[16:16]</bitRange>
            </field>
            <field>
              <name>ADDM7</name>
              <description>addm7</description>
              <bitRange>[17:17]</bitRange>
            </field>
            <field>
              <name>SWAP</name>
              <description>swap</description>
              <bitRange>[18:18]</bitRange>
            </field>
            <field>
              <name>TXFTCFG</name>
              <description>txfifo threshoold cfg</description>
              <bitRange>[21:19]</bitRange>
              <enumeratedValues>
                <enumeratedValue>
                  <name>0</name>
                  <value>1</value>
                </enumeratedValue>
                <enumeratedValue>
                  <name>1</name>
                  <value>2</value>
                </enumeratedValue>
                <enumeratedValue>
                  <name>2</name>
                  <value>4</value>
                </enumeratedValue>
              </enumeratedValues>
            </field>
            <field>
              <name>RXFTCFG</name>
              <description>rxfifo threshoold cfg</description>
              <bitRange>[24:22]</bitRange>
              <enumeratedValues>
                <enumeratedValue>
                  <name>0</name>
                  <value>1</value>
                </enumeratedValue>
                <enumeratedValue>
                  <name>1</name>
                  <value>2</value>
                </enumeratedValue>
                <enumeratedValue>
                  <name>2</name>
                  <value>4</value>
                </enumeratedValue>
              </enumeratedValues>
            </field>
            <field>
              <name>RX_INV</name>
              <description>rxinv</description>
              <bitRange>[25:25]</bitRange>
            </field>
            <field>
              <name>TX_INV</name>
              <description>txinv</description>
              <bitRange>[26:26]</bitRange>
            </field>
            <field>
              <name>DATAINV</name>
              <description>datainv</description>
              <bitRange>[27:27]</bitRange>
            </field>
            <field>
              <name>RXFRQ</name>
              <description>receive data flush request</description>
              <bitRange>[29:29]</bitRange>
            </field>
            <field>
              <name>TXFRQ</name>
              <description>Transmit data flush request</description>
              <bitRange>[30:30]</bitRange>
            </field>
            <field>
              <name>FIFOEN</name>
              <description>fifo en</description>
              <bitRange>[31:31]</bitRange>
            </field>
          </fields>
        </register>
        <register>
          <name>CR2</name>
          <addressOffset>0x10</addressOffset>
          <fields>
            <field>
              <name>LBDL</name>
              <description>LIN break detection length</description>
              <bitRange>[5:5]</bitRange>
            </field>
            <field>
              <name>LBDIE</name>
              <description>lin break enable</description>
              <bitRange>[6:6]</bitRange>
            </field>
            <field>
              <name>LBCL</name>
              <description>lbcl</description>
              <bitRange>[8:8]</bitRange>
            </field>
            <field>
              <name>CPHA</name>
              <description>cpha</description>
              <bitRange>[9:9]</bitRange>
            </field>
            <field>
              <name>CPOL</name>
              <description>cpol</description>
              <bitRange>[10:10]</bitRange>
            </field>
            <field>
              <name>CLKEN</name>
              <description>clk en</description>
              <bitRange>[11:11]</bitRange>
            </field>
            <field>
              <name>STOP</name>
              <description>stop bit</description>
              <bitRange>[13:12]</bitRange>
              <enumeratedValues>
                <enumeratedValue>
                  <name>0</name>
                  <value>1</value>
                </enumeratedValue>
                <enumeratedValue>
                  <name>1</name>
                  <value>2</value>
                </enumeratedValue>
              </enumeratedValues>
            </field>
            <field>
              <name>LINEN</name>
              <description>lin enable</description>
              <bitRange>[14:14]</bitRange>
            </field>
            <field>
              <name>ADD</name>
              <description>address</description>
              <bitRange>[22:15]</bitRange>
            </field>
            <field>
              <name>DEM</name>
              <description>dem</description>
              <bitRange>[23:23]</bitRange>
            </field>
            <field>
              <name>DEP</name>
              <description>dep</description>
              <bitRange>[24:24]</bitRange>
            </field>
          </fields>
        </register>
        <register>
          <name>CR3</name>
          <addressOffset>0x14</addressOffset>
          <fields>
            <field>
              <name>EIE</name>
              <description>error int enable</description>
              <bitRange>[0:0]</bitRange>
            </field>
            <field>
              <name>IREN</name>
              <description>iren enable</description>
              <bitRange>[1:1]</bitRange>
            </field>
            <field>
              <name>IRLP</name>
              <description>idra lowpower</description>
              <bitRange>[2:2]</bitRange>
            </field>
            <field>
              <name>HDSEL</name>
              <description>hdsel</description>
              <bitRange>[3:3]</bitRange>
            </field>
            <field>
              <name>NACK</name>
              <description>scen nack enable</description>
              <bitRange>[4:4]</bitRange>
            </field>
            <field>
              <name>SCEN</name>
              <description>scen enable</description>
              <bitRange>[5:5]</bitRange>
            </field>
            <field>
              <name>DMAR</name>
              <description>dma rx enable</description>
              <bitRange>[6:6]</bitRange>
            </field>
            <field>
              <name>DMAT</name>
              <description>dma tx enable</description>
              <bitRange>[7:7]</bitRange>
            </field>
            <field>
              <name>RTSE</name>
              <description>rts enable</description>
              <bitRange>[8:8]</bitRange>
            </field>
            <field>
              <name>CTSE</name>
              <description>cts enable</description>
              <bitRange>[9:9]</bitRange>
            </field>
            <field>
              <name>CTSIE</name>
              <description>cts int enable</description>
              <bitRange>[10:10]</bitRange>
            </field>
            <field>
              <name>OVER8</name>
              <description>oversampling</description>
              <bitRange>[11:11]</bitRange>
            </field>
            <field>
              <name>ABREN</name>
              <description>autobaud enable</description>
              <bitRange>[12:12]</bitRange>
            </field>
            <field>
              <name>ABRMOD</name>
              <description>auto baud mod</description>
              <bitRange>[14:13]</bitRange>
              <enumeratedValues>
                <enumeratedValue>
                  <name>0</name>
                  <value>1</value>
                </enumeratedValue>
                <enumeratedValue>
                  <name>1</name>
                  <value>2</value>
                </enumeratedValue>
              </enumeratedValues>
            </field>
            <field>
              <name>RXFFIE</name>
              <description>rxff int enable</description>
              <bitRange>[15:15]</bitRange>
            </field>
            <field>
              <name>TXFEIE</name>
              <description>txfe int enable</description>
              <bitRange>[16:16]</bitRange>
            </field>
            <field>
              <name>RXFTIE</name>
              <description>rxft int enable</description>
              <bitRange>[17:17]</bitRange>
            </field>
            <field>
              <name>TXFTIE</name>
              <description>txft int enable</description>
              <bitRange>[18:18]</bitRange>
            </field>
            <field>
              <name>DEDT</name>
              <description>dedt int enable</description>
              <bitRange>[23:19]</bitRange>
              <enumeratedValues>
                <enumeratedValue>
                  <name>0</name>
                  <value>1</value>
                </enumeratedValue>
                <enumeratedValue>
                  <name>1</name>
                  <value>2</value>
                </enumeratedValue>
                <enumeratedValue>
                  <name>2</name>
                  <value>4</value>
                </enumeratedValue>
                <enumeratedValue>
                  <name>3</name>
                  <value>8</value>
                </enumeratedValue>
                <enumeratedValue>
                  <name>4</name>
                  <value>16</value>
                </enumeratedValue>
              </enumeratedValues>
            </field>
            <field>
              <name>DEAT</name>
              <description>deat int enable</description>
              <bitRange>[28:24]</bitRange>
              <enumeratedValues>
                <enumeratedValue>
                  <name>0</name>
                  <value>1</value>
                </enumeratedValue>
                <enumeratedValue>
                  <name>1</name>
                  <value>2</value>
                </enumeratedValue>
                <enumeratedValue>
                  <name>2</name>
                  <value>4</value>
                </enumeratedValue>
                <enumeratedValue>
                  <name>3</name>
                  <value>8</value>
                </enumeratedValue>
                <enumeratedValue>
                  <name>4</name>
                  <value>16</value>
                </enumeratedValue>
              </enumeratedValues>
            </field>
            <field>
              <name>RTOIE</name>
              <description>rto int enable</description>
              <bitRange>[29:29]</bitRange>
            </field>
            <field>
              <name>EOBIE</name>
              <description>eob int enable</description>
              <bitRange>[30:30]</bitRange>
            </field>
          </fields>
        </register>
        <register>
          <name>GTPR</name>
          <addressOffset>0x18</addressOffset>
          <fields>
            <field>
              <name>PSC</name>
              <description>Prescaler value</description>
              <bitRange>[7:0]</bitRange>
            </field>
            <field>
              <name>GT</name>
              <description>Guard time value</description>
              <bitRange>[15:8]</bitRange>
            </field>
          </fields>
        </register>
        <register>
          <name>RTOR</name>
          <addressOffset>0x1C</addressOffset>
          <fields>
            <field>
              <name>RTO</name>
              <description>receive timeout</description>
              <bitRange>[23:0]</bitRange>
            </field>
            <field>
              <name>BLEN</name>
              <description>blocken length</description>
              <bitRange>[31:24]</bitRange>
            </field>
          </fields>
        </register>
        <register>
          <name>RDR</name>
          <addressOffset>0x20</addressOffset>
          <fields>
            <field>
              <name>RDR</name>
              <description>rdr</description>
              <bitRange>[8:0]</bitRange>
            </field>
          </fields>
        </register>
      </registers>
    </peripheral>
    <peripheral derivedFrom="USART1">
      <name>USART2</name>
      <baseAddress>0x40004400</baseAddress>
      <interrupt>
        <name>USART2</name>
        <description>USART2 global Interrupt</description>
        <value>38</value>
      </interrupt>
    </peripheral>
    <peripheral derivedFrom="USART1">
      <name>USART3</name>
      <baseAddress>0x40004800</baseAddress>
      <interrupt>
        <name>USART3</name>
        <description>USART3 global Interrupt</description>
        <value>39</value>
      </interrupt>
    </peripheral>
    <peripheral>
      <name>USB1_OTG_DEVICE</name>
      <description>USB on the go full speed</description>
      <baseAddress>0x48040800</baseAddress>
      <addressBlock>
        <offset>0x0</offset>
        <size>0x400</size>
        <usage>registers</usage>
      </addressBlock>
      <registers>
        <register>
          <name>FS_DCFG</name>
          <description>OTG_FS device configuration register (OTG_FS_DCFG)</description>
          <addressOffset>0x0</addressOffset>
          <fields>
            <field>
              <name>DSPD</name>
              <description>Device speed</description>
              <bitRange>[1:0]</bitRange>
            </field>
            <field>
              <name>NZLSOHSK</name>
              <description>Non-zero-length status OUT handshake</description>
              <bitRange>[2:2]</bitRange>
            </field>
            <field>
              <name>DAD</name>
              <description>Device address</description>
              <bitRange>[10:4]</bitRange>
            </field>
            <field>
              <name>PFIVL</name>
              <description>Periodic frame interval</description>
              <bitRange>[12:11]</bitRange>
            </field>
          </fields>
        </register>
        <register>
          <name>FS_DCTL</name>
          <description>OTG_FS device control register (OTG_FS_DCTL)</description>
          <addressOffset>0x4</addressOffset>
          <fields>
            <field>
              <name>RWUSIG</name>
              <description>Remote wakeup signaling</description>
              <bitRange>[0:0]</bitRange>
            </field>
            <field>
              <name>SDIS</name>
              <description>Soft disconnect</description>
              <bitRange>[1:1]</bitRange>
            </field>
            <field>
              <name>GINSTS</name>
              <description>Global IN NAK status</description>
              <bitRange>[2:2]</bitRange>
              <access>read-only</access>
            </field>
            <field>
              <name>GONSTS</name>
              <description>Global OUT NAK status</description>
              <bitRange>[3:3]</bitRange>
              <access>read-only</access>
            </field>
            <field>
              <name>TCTL</name>
              <description>Test control</description>
              <bitRange>[6:4]</bitRange>
            </field>
            <field>
              <name>SGINAK</name>
              <description>Set global IN NAK</description>
              <bitRange>[7:7]</bitRange>
            </field>
            <field>
              <name>CGINAK</name>
              <description>Clear global IN NAK</description>
              <bitRange>[8:8]</bitRange>
            </field>
            <field>
              <name>SGONAK</name>
              <description>Set global OUT NAK</description>
              <bitRange>[9:9]</bitRange>
            </field>
            <field>
              <name>CGONAK</name>
              <description>Clear global OUT NAK</description>
              <bitRange>[10:10]</bitRange>
            </field>
            <field>
              <name>POPRGDNE</name>
              <description>Power-on programming done</description>
              <bitRange>[11:11]</bitRange>
            </field>
          </fields>
        </register>
        <register>
          <name>FS_DSTS</name>
          <description>OTG_FS device status register (OTG_FS_DSTS)</description>
          <addressOffset>0x8</addressOffset>
          <fields>
            <field>
              <name>SUSPSTS</name>
              <description>Suspend status</description>
              <bitRange>[0:0]</bitRange>
              <access>read-only</access>
            </field>
            <field>
              <name>ENUMSPD</name>
              <description>Enumerated speed</description>
              <bitRange>[2:1]</bitRange>
              <access>read-only</access>
            </field>
            <field>
              <name>EERR</name>
              <description>Erratic error</description>
              <bitRange>[3:3]</bitRange>
              <access>read-only</access>
            </field>
            <field>
              <name>FNSOF</name>
              <description>Frame number of the received SOF</description>
              <bitRange>[21:8]</bitRange>
              <access>read-only</access>
            </field>
          </fields>
        </register>
        <register>
          <name>FS_DIEPMSK</name>
          <description>OTG_FS device IN endpoint common interrupt mask register (OTG_FS_DIEPMSK)</description>
          <addressOffset>0x10</addressOffset>
          <fields>
            <field>
              <name>XFRCM</name>
              <description>Transfer completed interrupt mask</description>
              <bitRange>[0:0]</bitRange>
            </field>
            <field>
              <name>EPDM</name>
              <description>Endpoint disabled interrupt mask</description>
              <bitRange>[1:1]</bitRange>
            </field>
            <field>
              <name>TOM</name>
              <description>Timeout condition mask (Non-isochronous endpoints)</description>
              <bitRange>[3:3]</bitRange>
            </field>
            <field>
              <name>ITTXFEMSK</name>
              <description>IN token received when TxFIFO empty mask</description>
              <bitRange>[4:4]</bitRange>
            </field>
            <field>
              <name>INEPNMM</name>
              <description>IN token received with EP mismatch mask</description>
              <bitRange>[5:5]</bitRange>
            </field>
            <field>
              <name>INEPNEM</name>
              <description>IN endpoint NAK effective mask</description>
              <bitRange>[6:6]</bitRange>
            </field>
          </fields>
        </register>
        <register>
          <name>FS_DOEPMSK</name>
          <description>OTG_FS device OUT endpoint common interrupt mask register (OTG_FS_DOEPMSK)</description>
          <addressOffset>0x14</addressOffset>
          <fields>
            <field>
              <name>XFRCM</name>
              <description>Transfer completed interrupt mask</description>
              <bitRange>[0:0]</bitRange>
            </field>
            <field>
              <name>EPDM</name>
              <description>Endpoint disabled interrupt mask</description>
              <bitRange>[1:1]</bitRange>
            </field>
            <field>
              <name>STUPM</name>
              <description>SETUP phase done mask</description>
              <bitRange>[3:3]</bitRange>
            </field>
            <field>
              <name>OTEPDM</name>
              <description>OUT token received when endpoint disabled mask</description>
              <bitRange>[4:4]</bitRange>
            </field>
          </fields>
        </register>
        <register>
          <name>FS_DAINT</name>
          <description>OTG_FS device all endpoints interrupt register (OTG_FS_DAINT)</description>
          <addressOffset>0x18</addressOffset>
          <fields>
            <field>
              <name>IEPINT</name>
              <description>IN endpoint interrupt bits</description>
              <bitRange>[15:0]</bitRange>
              <access>read-only</access>
            </field>
            <field>
              <name>OEPINT</name>
              <description>OUT endpoint interrupt bits</description>
              <bitRange>[31:16]</bitRange>
              <access>read-only</access>
            </field>
          </fields>
        </register>
        <register>
          <name>FS_DAINTMSK</name>
          <description>OTG_FS all endpoints interrupt mask register (OTG_FS_DAINTMSK)</description>
          <addressOffset>0x1C</addressOffset>
          <fields>
            <field>
              <name>IEPM</name>
              <description>IN EP interrupt mask bits</description>
              <bitRange>[15:0]</bitRange>
            </field>
            <field>
              <name>OEPINT</name>
              <description>OUT endpoint interrupt bits</description>
              <bitRange>[31:16]</bitRange>
            </field>
          </fields>
        </register>
        <register>
          <name>DVBUSDIS</name>
          <description>OTG_FS device VBUS discharge time register</description>
          <addressOffset>0x28</addressOffset>
          <fields>
            <field>
              <name>VBUSDT</name>
              <description>Device VBUS discharge time</description>
              <bitRange>[15:0]</bitRange>
            </field>
          </fields>
        </register>
        <register>
          <name>DVBUSPULSE</name>
          <description>OTG_FS device VBUS pulsing time register</description>
          <addressOffset>0x2C</addressOffset>
          <fields>
            <field>
              <name>DVBUSP</name>
              <description>Device VBUS pulsing time</description>
              <bitRange>[11:0]</bitRange>
            </field>
          </fields>
        </register>
        <register>
          <name>DIEPEMPMSK</name>
          <description>OTG_FS device IN endpoint FIFO empty interrupt mask register</description>
          <addressOffset>0x34</addressOffset>
          <fields>
            <field>
              <name>INEPTXFEM</name>
              <description>IN EP Tx FIFO empty interrupt mask bits</description>
              <bitRange>[15:0]</bitRange>
            </field>
          </fields>
        </register>
        <register>
          <name>FS_DIEPCTL0</name>
          <description>OTG_FS device control IN endpoint 0 control register (OTG_FS_DIEPCTL0)</description>
          <addressOffset>0x100</addressOffset>
          <fields>
            <field>
              <name>MPSIZ</name>
              <description>Maximum packet size</description>
              <bitRange>[1:0]</bitRange>
            </field>
            <field>
              <name>USBAEP</name>
              <description>USB active endpoint</description>
              <bitRange>[15:15]</bitRange>
              <access>read-only</access>
            </field>
            <field>
              <name>NAKSTS</name>
              <description>NAK status</description>
              <bitRange>[17:17]</bitRange>
              <access>read-only</access>
            </field>
            <field>
              <name>EPTYP</name>
              <description>Endpoint type</description>
              <bitRange>[19:18]</bitRange>
              <access>read-only</access>
            </field>
            <field>
              <name>STALL</name>
              <description>STALL handshake</description>
              <bitRange>[21:21]</bitRange>
            </field>
            <field>
              <name>TXFNUM</name>
              <description>TxFIFO number</description>
              <bitRange>[25:22]</bitRange>
            </field>
            <field>
              <name>CNAK</name>
              <description>Clear NAK</description>
              <bitRange>[26:26]</bitRange>
            </field>
            <field>
              <name>SNAK</name>
              <description>Set NAK</description>
              <bitRange>[27:27]</bitRange>
            </field>
            <field>
              <name>EPDIS</name>
              <description>Endpoint disable</description>
              <bitRange>[30:30]</bitRange>
              <access>read-only</access>
            </field>
            <field>
              <name>EPENA</name>
              <description>Endpoint enable</description>
              <bitRange>[31:31]</bitRange>
              <access>read-only</access>
            </field>
          </fields>
        </register>
        <register>
          <name>DIEPINT0</name>
          <description>device endpoint-x interrupt register</description>
          <addressOffset>0x108</addressOffset>
          <fields>
            <field>
              <name>XFRC</name>
              <description>XFRC</description>
              <bitRange>[0:0]</bitRange>
            </field>
            <field>
              <name>EPDISD</name>
              <description>EPDISD</description>
              <bitRange>[1:1]</bitRange>
            </field>
            <field>
              <name>TOC</name>
              <description>TOC</description>
              <bitRange>[3:3]</bitRange>
            </field>
            <field>
              <name>ITTXFE</name>
              <description>ITTXFE</description>
              <bitRange>[4:4]</bitRange>
            </field>
            <field>
              <name>INEPNE</name>
              <description>INEPNE</description>
              <bitRange>[6:6]</bitRange>
            </field>
            <field>
              <name>TXFE</name>
              <description>TXFE</description>
              <bitRange>[7:7]</bitRange>
              <access>read-only</access>
            </field>
          </fields>
        </register>
        <register>
          <name>DIEPTSIZ0</name>
          <description>device endpoint-0 transfer size register</description>
          <addressOffset>0x110</addressOffset>
          <fields>
            <field>
              <name>XFRSIZ</name>
              <description>Transfer size</description>
              <bitRange>[6:0]</bitRange>
            </field>
            <field>
              <name>PKTCNT</name>
              <description>Packet count</description>
              <bitRange>[20:19]</bitRange>
            </field>
          </fields>
        </register>
        <register>
          <name>DTXFSTS0</name>
          <description>OTG_FS device IN endpoint transmit FIFO status register</description>
          <addressOffset>0x118</addressOffset>
          <fields>
            <field>
              <name>INEPTFSAV</name>
              <description>IN endpoint TxFIFO space available</description>
              <bitRange>[15:0]</bitRange>
              <access>read-only</access>
            </field>
          </fields>
        </register>
        <register>
          <name>DIEPCTL1</name>
          <description>OTG device endpoint-1 control register</description>
          <addressOffset>0x120</addressOffset>
          <fields>
            <field>
              <name>MPSIZ</name>
              <description>MPSIZ</description>
              <bitRange>[10:0]</bitRange>
            </field>
            <field>
              <name>USBAEP</name>
              <description>USBAEP</description>
              <bitRange>[15:15]</bitRange>
            </field>
            <field>
              <name>EONUM_DPID</name>
              <description>EONUM/DPID</description>
              <bitRange>[16:16]</bitRange>
              <access>read-only</access>
            </field>
            <field>
              <name>NAKSTS</name>
              <description>NAKSTS</description>
              <bitRange>[17:17]</bitRange>
              <access>read-only</access>
            </field>
            <field>
              <name>EPTYP</name>
              <description>EPTYP</description>
              <bitRange>[19:18]</bitRange>
            </field>
            <field>
              <name>STALL</name>
              <description>Stall</description>
              <bitRange>[21:21]</bitRange>
            </field>
            <field>
              <name>TXFNUM</name>
              <description>TXFNUM</description>
              <bitRange>[25:22]</bitRange>
            </field>
            <field>
              <name>CNAK</name>
              <description>CNAK</description>
              <bitRange>[26:26]</bitRange>
            </field>
            <field>
              <name>SNAK</name>
              <description>SNAK</description>
              <bitRange>[27:27]</bitRange>
            </field>
            <field>
              <name>SD0PID_SEVNFRM</name>
              <description>SD0PID/SEVNFRM</description>
              <bitRange>[28:28]</bitRange>
            </field>
            <field>
              <name>SODDFRM_SD1PID</name>
              <description>SODDFRM/SD1PID</description>
              <bitRange>[29:29]</bitRange>
            </field>
            <field>
              <name>EPDIS</name>
              <description>EPDIS</description>
              <bitRange>[30:30]</bitRange>
            </field>
            <field>
              <name>EPENA</name>
              <description>EPENA</description>
              <bitRange>[31:31]</bitRange>
            </field>
          </fields>
        </register>
        <register>
          <name>DIEPINT1</name>
          <description>device endpoint-1 interrupt register</description>
          <addressOffset>0x128</addressOffset>
          <fields>
            <field>
              <name>XFRC</name>
              <description>XFRC</description>
              <bitRange>[0:0]</bitRange>
            </field>
            <field>
              <name>EPDISD</name>
              <description>EPDISD</description>
              <bitRange>[1:1]</bitRange>
            </field>
            <field>
              <name>TOC</name>
              <description>TOC</description>
              <bitRange>[3:3]</bitRange>
            </field>
            <field>
              <name>ITTXFE</name>
              <description>ITTXFE</description>
              <bitRange>[4:4]</bitRange>
            </field>
            <field>
              <name>INEPNE</name>
              <description>INEPNE</description>
              <bitRange>[6:6]</bitRange>
            </field>
            <field>
              <name>TXFE</name>
              <description>TXFE</description>
              <bitRange>[7:7]</bitRange>
              <access>read-only</access>
            </field>
          </fields>
        </register>
        <register>
          <name>DIEPTSIZ1</name>
          <description>device endpoint-1 transfer size register</description>
          <addressOffset>0x130</addressOffset>
          <fields>
            <field>
              <name>XFRSIZ</name>
              <description>Transfer size</description>
              <bitRange>[18:0]</bitRange>
            </field>
            <field>
              <name>PKTCNT</name>
              <description>Packet count</description>
              <bitRange>[28:19]</bitRange>
            </field>
            <field>
              <name>MCNT</name>
              <description>Multi count</description>
              <bitRange>[30:29]</bitRange>
            </field>
          </fields>
        </register>
        <register>
          <name>DTXFSTS1</name>
          <description>OTG_FS device IN endpoint transmit FIFO status register</description>
          <addressOffset>0x138</addressOffset>
          <fields>
            <field>
              <name>INEPTFSAV</name>
              <description>IN endpoint TxFIFO space available</description>
              <bitRange>[15:0]</bitRange>
              <access>read-only</access>
            </field>
          </fields>
        </register>
        <register>
          <name>DIEPCTL2</name>
          <description>OTG device endpoint-2 control register</description>
          <addressOffset>0x140</addressOffset>
          <fields>
            <field>
              <name>MPSIZ</name>
              <description>MPSIZ</description>
              <bitRange>[10:0]</bitRange>
            </field>
            <field>
              <name>USBAEP</name>
              <description>USBAEP</description>
              <bitRange>[15:15]</bitRange>
            </field>
            <field>
              <name>EONUM_DPID</name>
              <description>EONUM/DPID</description>
              <bitRange>[16:16]</bitRange>
              <access>read-only</access>
            </field>
            <field>
              <name>NAKSTS</name>
              <description>NAKSTS</description>
              <bitRange>[17:17]</bitRange>
              <access>read-only</access>
            </field>
            <field>
              <name>EPTYP</name>
              <description>EPTYP</description>
              <bitRange>[19:18]</bitRange>
            </field>
            <field>
              <name>STALL</name>
              <description>Stall</description>
              <bitRange>[21:21]</bitRange>
            </field>
            <field>
              <name>TXFNUM</name>
              <description>TXFNUM</description>
              <bitRange>[25:22]</bitRange>
            </field>
            <field>
              <name>CNAK</name>
              <description>CNAK</description>
              <bitRange>[26:26]</bitRange>
            </field>
            <field>
              <name>SNAK</name>
              <description>SNAK</description>
              <bitRange>[27:27]</bitRange>
            </field>
            <field>
              <name>SD0PID_SEVNFRM</name>
              <description>SD0PID/SEVNFRM</description>
              <bitRange>[28:28]</bitRange>
            </field>
            <field>
              <name>SODDFRM</name>
              <description>SODDFRM</description>
              <bitRange>[29:29]</bitRange>
            </field>
            <field>
              <name>EPDIS</name>
              <description>EPDIS</description>
              <bitRange>[30:30]</bitRange>
            </field>
            <field>
              <name>EPENA</name>
              <description>EPENA</description>
              <bitRange>[31:31]</bitRange>
            </field>
          </fields>
        </register>
        <register>
          <name>DIEPINT2</name>
          <description>device endpoint-2 interrupt register</description>
          <addressOffset>0x148</addressOffset>
          <fields>
            <field>
              <name>XFRC</name>
              <description>XFRC</description>
              <bitRange>[0:0]</bitRange>
            </field>
            <field>
              <name>EPDISD</name>
              <description>EPDISD</description>
              <bitRange>[1:1]</bitRange>
            </field>
            <field>
              <name>TOC</name>
              <description>TOC</description>
              <bitRange>[3:3]</bitRange>
            </field>
            <field>
              <name>ITTXFE</name>
              <description>ITTXFE</description>
              <bitRange>[4:4]</bitRange>
            </field>
            <field>
              <name>INEPNE</name>
              <description>INEPNE</description>
              <bitRange>[6:6]</bitRange>
            </field>
            <field>
              <name>TXFE</name>
              <description>TXFE</description>
              <bitRange>[7:7]</bitRange>
              <access>read-only</access>
            </field>
          </fields>
        </register>
        <register>
          <name>DIEPTSIZ2</name>
          <description>device endpoint-2 transfer size register</description>
          <addressOffset>0x150</addressOffset>
          <fields>
            <field>
              <name>XFRSIZ</name>
              <description>Transfer size</description>
              <bitRange>[18:0]</bitRange>
            </field>
            <field>
              <name>PKTCNT</name>
              <description>Packet count</description>
              <bitRange>[28:19]</bitRange>
            </field>
            <field>
              <name>MCNT</name>
              <description>Multi count</description>
              <bitRange>[30:29]</bitRange>
            </field>
          </fields>
        </register>
        <register>
          <name>DTXFSTS2</name>
          <description>OTG_FS device IN endpoint transmit FIFO status register</description>
          <addressOffset>0x158</addressOffset>
          <fields>
            <field>
              <name>INEPTFSAV</name>
              <description>IN endpoint TxFIFO space available</description>
              <bitRange>[15:0]</bitRange>
              <access>read-only</access>
            </field>
          </fields>
        </register>
        <register>
          <name>DIEPCTL3</name>
          <description>OTG device endpoint-3 control register</description>
          <addressOffset>0x160</addressOffset>
          <fields>
            <field>
              <name>MPSIZ</name>
              <description>MPSIZ</description>
              <bitRange>[10:0]</bitRange>
            </field>
            <field>
              <name>USBAEP</name>
              <description>USBAEP</description>
              <bitRange>[15:15]</bitRange>
            </field>
            <field>
              <name>EONUM_DPID</name>
              <description>EONUM/DPID</description>
              <bitRange>[16:16]</bitRange>
              <access>read-only</access>
            </field>
            <field>
              <name>NAKSTS</name>
              <description>NAKSTS</description>
              <bitRange>[17:17]</bitRange>
              <access>read-only</access>
            </field>
            <field>
              <name>EPTYP</name>
              <description>EPTYP</description>
              <bitRange>[19:18]</bitRange>
            </field>
            <field>
              <name>STALL</name>
              <description>Stall</description>
              <bitRange>[21:21]</bitRange>
            </field>
            <field>
              <name>TXFNUM</name>
              <description>TXFNUM</description>
              <bitRange>[25:22]</bitRange>
            </field>
            <field>
              <name>CNAK</name>
              <description>CNAK</description>
              <bitRange>[26:26]</bitRange>
            </field>
            <field>
              <name>SNAK</name>
              <description>SNAK</description>
              <bitRange>[27:27]</bitRange>
            </field>
            <field>
              <name>SD0PID_SEVNFRM</name>
              <description>SD0PID/SEVNFRM</description>
              <bitRange>[28:28]</bitRange>
            </field>
            <field>
              <name>SODDFRM</name>
              <description>SODDFRM</description>
              <bitRange>[29:29]</bitRange>
            </field>
            <field>
              <name>EPDIS</name>
              <description>EPDIS</description>
              <bitRange>[30:30]</bitRange>
            </field>
            <field>
              <name>EPENA</name>
              <description>EPENA</description>
              <bitRange>[31:31]</bitRange>
            </field>
          </fields>
        </register>
        <register>
          <name>DIEPINT3</name>
          <description>device endpoint-3 interrupt register</description>
          <addressOffset>0x168</addressOffset>
          <fields>
            <field>
              <name>XFRC</name>
              <description>XFRC</description>
              <bitRange>[0:0]</bitRange>
            </field>
            <field>
              <name>EPDISD</name>
              <description>EPDISD</description>
              <bitRange>[1:1]</bitRange>
            </field>
            <field>
              <name>TOC</name>
              <description>TOC</description>
              <bitRange>[3:3]</bitRange>
            </field>
            <field>
              <name>ITTXFE</name>
              <description>ITTXFE</description>
              <bitRange>[4:4]</bitRange>
            </field>
            <field>
              <name>INEPNE</name>
              <description>INEPNE</description>
              <bitRange>[6:6]</bitRange>
            </field>
            <field>
              <name>TXFE</name>
              <description>TXFE</description>
              <bitRange>[7:7]</bitRange>
              <access>read-only</access>
            </field>
          </fields>
        </register>
        <register>
          <name>DIEPTSIZ3</name>
          <description>device endpoint-3 transfer size register</description>
          <addressOffset>0x170</addressOffset>
          <fields>
            <field>
              <name>XFRSIZ</name>
              <description>Transfer size</description>
              <bitRange>[18:0]</bitRange>
            </field>
            <field>
              <name>PKTCNT</name>
              <description>Packet count</description>
              <bitRange>[28:19]</bitRange>
            </field>
            <field>
              <name>MCNT</name>
              <description>Multi count</description>
              <bitRange>[30:29]</bitRange>
            </field>
          </fields>
        </register>
        <register>
          <name>DTXFSTS3</name>
          <description>OTG_FS device IN endpoint transmit FIFO status register</description>
          <addressOffset>0x178</addressOffset>
          <fields>
            <field>
              <name>INEPTFSAV</name>
              <description>IN endpoint TxFIFO space available</description>
              <bitRange>[15:0]</bitRange>
              <access>read-only</access>
            </field>
          </fields>
        </register>
        <register>
          <name>DOEPCTL0</name>
          <description>device endpoint-0 control register</description>
          <addressOffset>0x300</addressOffset>
          <fields>
            <field>
              <name>MPSIZ</name>
              <description>MPSIZ</description>
              <bitRange>[1:0]</bitRange>
              <access>read-only</access>
            </field>
            <field>
              <name>USBAEP</name>
              <description>USBAEP</description>
              <bitRange>[15:15]</bitRange>
              <access>read-only</access>
            </field>
            <field>
              <name>NAKSTS</name>
              <description>NAKSTS</description>
              <bitRange>[17:17]</bitRange>
              <access>read-only</access>
            </field>
            <field>
              <name>EPTYP</name>
              <description>EPTYP</description>
              <bitRange>[19:18]</bitRange>
              <access>read-only</access>
            </field>
            <field>
              <name>SNPM</name>
              <description>SNPM</description>
              <bitRange>[20:20]</bitRange>
            </field>
            <field>
              <name>STALL</name>
              <description>Stall</description>
              <bitRange>[21:21]</bitRange>
            </field>
            <field>
              <name>CNAK</name>
              <description>CNAK</description>
              <bitRange>[26:26]</bitRange>
            </field>
            <field>
              <name>SNAK</name>
              <description>SNAK</description>
              <bitRange>[27:27]</bitRange>
            </field>
            <field>
              <name>EPDIS</name>
              <description>EPDIS</description>
              <bitRange>[30:30]</bitRange>
              <access>read-only</access>
            </field>
            <field>
              <name>EPENA</name>
              <description>EPENA</description>
              <bitRange>[31:31]</bitRange>
            </field>
          </fields>
        </register>
        <register>
          <name>DOEPINT0</name>
          <description>device endpoint-0 interrupt register</description>
          <addressOffset>0x308</addressOffset>
          <fields>
            <field>
              <name>XFRC</name>
              <description>XFRC</description>
              <bitRange>[0:0]</bitRange>
            </field>
            <field>
              <name>EPDISD</name>
              <description>EPDISD</description>
              <bitRange>[1:1]</bitRange>
            </field>
            <field>
              <name>STUP</name>
              <description>STUP</description>
              <bitRange>[3:3]</bitRange>
            </field>
            <field>
              <name>OTEPDIS</name>
              <description>OTEPDIS</description>
              <bitRange>[4:4]</bitRange>
            </field>
            <field>
              <name>B2BSTUP</name>
              <description>B2BSTUP</description>
              <bitRange>[6:6]</bitRange>
            </field>
          </fields>
        </register>
        <register>
          <name>DOEPTSIZ0</name>
          <description>device OUT endpoint-0 transfer size register</description>
          <addressOffset>0x310</addressOffset>
          <fields>
            <field>
              <name>XFRSIZ</name>
              <description>Transfer size</description>
              <bitRange>[6:0]</bitRange>
            </field>
            <field>
              <name>PKTCNT</name>
              <description>Packet count</description>
              <bitRange>[19:19]</bitRange>
            </field>
            <field>
              <name>STUPCNT</name>
              <description>SETUP packet count</description>
              <bitRange>[30:29]</bitRange>
            </field>
          </fields>
        </register>
        <register>
          <name>DOEPCTL1</name>
          <description>device endpoint-1 control register</description>
          <addressOffset>0x320</addressOffset>
          <fields>
            <field>
              <name>MPSIZ</name>
              <description>MPSIZ</description>
              <bitRange>[10:0]</bitRange>
            </field>
            <field>
              <name>USBAEP</name>
              <description>USBAEP</description>
              <bitRange>[15:15]</bitRange>
            </field>
            <field>
              <name>EONUM_DPID</name>
              <description>EONUM/DPID</description>
              <bitRange>[16:16]</bitRange>
              <access>read-only</access>
            </field>
            <field>
              <name>NAKSTS</name>
              <description>NAKSTS</description>
              <bitRange>[17:17]</bitRange>
              <access>read-only</access>
            </field>
            <field>
              <name>EPTYP</name>
              <description>EPTYP</description>
              <bitRange>[19:18]</bitRange>
            </field>
            <field>
              <name>SNPM</name>
              <description>SNPM</description>
              <bitRange>[20:20]</bitRange>
            </field>
            <field>
              <name>STALL</name>
              <description>Stall</description>
              <bitRange>[21:21]</bitRange>
            </field>
            <field>
              <name>CNAK</name>
              <description>CNAK</description>
              <bitRange>[26:26]</bitRange>
            </field>
            <field>
              <name>SNAK</name>
              <description>SNAK</description>
              <bitRange>[27:27]</bitRange>
            </field>
            <field>
              <name>SD0PID_SEVNFRM</name>
              <description>SD0PID/SEVNFRM</description>
              <bitRange>[28:28]</bitRange>
            </field>
            <field>
              <name>SODDFRM</name>
              <description>SODDFRM</description>
              <bitRange>[29:29]</bitRange>
            </field>
            <field>
              <name>EPDIS</name>
              <description>EPDIS</description>
              <bitRange>[30:30]</bitRange>
            </field>
            <field>
              <name>EPENA</name>
              <description>EPENA</description>
              <bitRange>[31:31]</bitRange>
            </field>
          </fields>
        </register>
        <register>
          <name>DOEPINT1</name>
          <description>device endpoint-1 interrupt register</description>
          <addressOffset>0x328</addressOffset>
          <fields>
            <field>
              <name>XFRC</name>
              <description>XFRC</description>
              <bitRange>[0:0]</bitRange>
            </field>
            <field>
              <name>EPDISD</name>
              <description>EPDISD</description>
              <bitRange>[1:1]</bitRange>
            </field>
            <field>
              <name>STUP</name>
              <description>STUP</description>
              <bitRange>[3:3]</bitRange>
            </field>
            <field>
              <name>OTEPDIS</name>
              <description>OTEPDIS</description>
              <bitRange>[4:4]</bitRange>
            </field>
            <field>
              <name>B2BSTUP</name>
              <description>B2BSTUP</description>
              <bitRange>[6:6]</bitRange>
            </field>
          </fields>
        </register>
        <register>
          <name>DOEPTSIZ1</name>
          <description>device OUT endpoint-1 transfer size register</description>
          <addressOffset>0x330</addressOffset>
          <fields>
            <field>
              <name>XFRSIZ</name>
              <description>Transfer size</description>
              <bitRange>[18:0]</bitRange>
            </field>
            <field>
              <name>PKTCNT</name>
              <description>Packet count</description>
              <bitRange>[28:19]</bitRange>
            </field>
            <field>
              <name>RXDPID_STUPCNT</name>
              <description>Received data PID/SETUP packet count</description>
              <bitRange>[30:29]</bitRange>
            </field>
          </fields>
        </register>
        <register>
          <name>DOEPCTL2</name>
          <description>device endpoint-2 control register</description>
          <addressOffset>0x340</addressOffset>
          <fields>
            <field>
              <name>MPSIZ</name>
              <description>MPSIZ</description>
              <bitRange>[10:0]</bitRange>
            </field>
            <field>
              <name>USBAEP</name>
              <description>USBAEP</description>
              <bitRange>[15:15]</bitRange>
            </field>
            <field>
              <name>EONUM_DPID</name>
              <description>EONUM/DPID</description>
              <bitRange>[16:16]</bitRange>
              <access>read-only</access>
            </field>
            <field>
              <name>NAKSTS</name>
              <description>NAKSTS</description>
              <bitRange>[17:17]</bitRange>
              <access>read-only</access>
            </field>
            <field>
              <name>EPTYP</name>
              <description>EPTYP</description>
              <bitRange>[19:18]</bitRange>
            </field>
            <field>
              <name>SNPM</name>
              <description>SNPM</description>
              <bitRange>[20:20]</bitRange>
            </field>
            <field>
              <name>STALL</name>
              <description>Stall</description>
              <bitRange>[21:21]</bitRange>
            </field>
            <field>
              <name>CNAK</name>
              <description>CNAK</description>
              <bitRange>[26:26]</bitRange>
            </field>
            <field>
              <name>SNAK</name>
              <description>SNAK</description>
              <bitRange>[27:27]</bitRange>
            </field>
            <field>
              <name>SD0PID_SEVNFRM</name>
              <description>SD0PID/SEVNFRM</description>
              <bitRange>[28:28]</bitRange>
            </field>
            <field>
              <name>SODDFRM</name>
              <description>SODDFRM</description>
              <bitRange>[29:29]</bitRange>
            </field>
            <field>
              <name>EPDIS</name>
              <description>EPDIS</description>
              <bitRange>[30:30]</bitRange>
            </field>
            <field>
              <name>EPENA</name>
              <description>EPENA</description>
              <bitRange>[31:31]</bitRange>
            </field>
          </fields>
        </register>
        <register>
          <name>DOEPINT2</name>
          <description>device endpoint-2 interrupt register</description>
          <addressOffset>0x348</addressOffset>
          <fields>
            <field>
              <name>XFRC</name>
              <description>XFRC</description>
              <bitRange>[0:0]</bitRange>
            </field>
            <field>
              <name>EPDISD</name>
              <description>EPDISD</description>
              <bitRange>[1:1]</bitRange>
            </field>
            <field>
              <name>STUP</name>
              <description>STUP</description>
              <bitRange>[3:3]</bitRange>
            </field>
            <field>
              <name>OTEPDIS</name>
              <description>OTEPDIS</description>
              <bitRange>[4:4]</bitRange>
            </field>
            <field>
              <name>B2BSTUP</name>
              <description>B2BSTUP</description>
              <bitRange>[6:6]</bitRange>
            </field>
          </fields>
        </register>
        <register>
          <name>DOEPTSIZ2</name>
          <description>device OUT endpoint-2 transfer size register</description>
          <addressOffset>0x350</addressOffset>
          <fields>
            <field>
              <name>XFRSIZ</name>
              <description>Transfer size</description>
              <bitRange>[18:0]</bitRange>
            </field>
            <field>
              <name>PKTCNT</name>
              <description>Packet count</description>
              <bitRange>[28:19]</bitRange>
            </field>
            <field>
              <name>RXDPID_STUPCNT</name>
              <description>Received data PID/SETUP packet count</description>
              <bitRange>[30:29]</bitRange>
            </field>
          </fields>
        </register>
        <register>
          <name>DOEPCTL3</name>
          <description>device endpoint-3 control register</description>
          <addressOffset>0x360</addressOffset>
          <fields>
            <field>
              <name>MPSIZ</name>
              <description>MPSIZ</description>
              <bitRange>[10:0]</bitRange>
            </field>
            <field>
              <name>USBAEP</name>
              <description>USBAEP</description>
              <bitRange>[15:15]</bitRange>
            </field>
            <field>
              <name>EONUM_DPID</name>
              <description>EONUM/DPID</description>
              <bitRange>[16:16]</bitRange>
              <access>read-only</access>
            </field>
            <field>
              <name>NAKSTS</name>
              <description>NAKSTS</description>
              <bitRange>[17:17]</bitRange>
              <access>read-only</access>
            </field>
            <field>
              <name>EPTYP</name>
              <description>EPTYP</description>
              <bitRange>[19:18]</bitRange>
            </field>
            <field>
              <name>SNPM</name>
              <description>SNPM</description>
              <bitRange>[20:20]</bitRange>
            </field>
            <field>
              <name>STALL</name>
              <description>Stall</description>
              <bitRange>[21:21]</bitRange>
            </field>
            <field>
              <name>CNAK</name>
              <description>CNAK</description>
              <bitRange>[26:26]</bitRange>
            </field>
            <field>
              <name>SNAK</name>
              <description>SNAK</description>
              <bitRange>[27:27]</bitRange>
            </field>
            <field>
              <name>SD0PID_SEVNFRM</name>
              <description>SD0PID/SEVNFRM</description>
              <bitRange>[28:28]</bitRange>
            </field>
            <field>
              <name>SODDFRM</name>
              <description>SODDFRM</description>
              <bitRange>[29:29]</bitRange>
            </field>
            <field>
              <name>EPDIS</name>
              <description>EPDIS</description>
              <bitRange>[30:30]</bitRange>
            </field>
            <field>
              <name>EPENA</name>
              <description>EPENA</description>
              <bitRange>[31:31]</bitRange>
            </field>
          </fields>
        </register>
        <register>
          <name>DOEPINT3</name>
          <description>device endpoint-3 interrupt register</description>
          <addressOffset>0x368</addressOffset>
          <fields>
            <field>
              <name>XFRC</name>
              <description>XFRC</description>
              <bitRange>[0:0]</bitRange>
            </field>
            <field>
              <name>EPDISD</name>
              <description>EPDISD</description>
              <bitRange>[1:1]</bitRange>
            </field>
            <field>
              <name>STUP</name>
              <description>STUP</description>
              <bitRange>[3:3]</bitRange>
            </field>
            <field>
              <name>OTEPDIS</name>
              <description>OTEPDIS</description>
              <bitRange>[4:4]</bitRange>
            </field>
            <field>
              <name>B2BSTUP</name>
              <description>B2BSTUP</description>
              <bitRange>[6:6]</bitRange>
            </field>
          </fields>
        </register>
        <register>
          <name>DOEPTSIZ3</name>
          <description>device OUT endpoint-3 transfer size register</description>
          <addressOffset>0x370</addressOffset>
          <fields>
            <field>
              <name>XFRSIZ</name>
              <description>Transfer size</description>
              <bitRange>[18:0]</bitRange>
            </field>
            <field>
              <name>PKTCNT</name>
              <description>Packet count</description>
              <bitRange>[28:19]</bitRange>
            </field>
            <field>
              <name>RXDPID_STUPCNT</name>
              <description>Received data PID/SETUP packet count</description>
              <bitRange>[30:29]</bitRange>
            </field>
          </fields>
        </register>
      </registers>
    </peripheral>
    <peripheral>
      <name>USB1_OTG_GLOBAL</name>
      <description>USB on the go full speed</description>
      <baseAddress>0x48040000</baseAddress>
      <addressBlock>
        <offset>0x0</offset>
        <size>0x400</size>
        <usage>registers</usage>
      </addressBlock>
      <interrupt>
        <name>OTG1_FS</name>
        <description>USB1 OTG global interrupt</description>
        <value>21</value>
      </interrupt>
      <registers>
        <register>
          <name>FS_GOTGCTL</name>
          <description>OTG_FS control and status register (OTG_FS_GOTGCTL)</description>
          <addressOffset>0x0</addressOffset>
          <fields>
            <field>
              <name>SRQSCS</name>
              <description>Session request success</description>
              <bitRange>[0:0]</bitRange>
              <access>read-only</access>
            </field>
            <field>
              <name>SRQ</name>
              <description>Session request</description>
              <bitRange>[1:1]</bitRange>
            </field>
            <field>
              <name>HNGSCS</name>
              <description>Host negotiation success</description>
              <bitRange>[8:8]</bitRange>
              <access>read-only</access>
            </field>
            <field>
              <name>HNPRQ</name>
              <description>HNP request</description>
              <bitRange>[9:9]</bitRange>
            </field>
            <field>
              <name>HSHNPEN</name>
              <description>Host set HNP enable</description>
              <bitRange>[10:10]</bitRange>
            </field>
            <field>
              <name>DHNPEN</name>
              <description>Device HNP enabled</description>
              <bitRange>[11:11]</bitRange>
            </field>
            <field>
              <name>CIDSTS</name>
              <description>Connector ID status</description>
              <bitRange>[16:16]</bitRange>
              <access>read-only</access>
            </field>
            <field>
              <name>DBCT</name>
              <description>Long/short debounce time</description>
              <bitRange>[17:17]</bitRange>
              <access>read-only</access>
            </field>
            <field>
              <name>ASVLD</name>
              <description>A-session valid</description>
              <bitRange>[18:18]</bitRange>
              <access>read-only</access>
            </field>
            <field>
              <name>BSVLD</name>
              <description>B-session valid</description>
              <bitRange>[19:19]</bitRange>
              <access>read-only</access>
            </field>
          </fields>
        </register>
        <register>
          <name>FS_GOTGINT</name>
          <description>OTG_FS interrupt register (OTG_FS_GOTGINT)</description>
          <addressOffset>0x4</addressOffset>
          <fields>
            <field>
              <name>SEDET</name>
              <description>Session end detected</description>
              <bitRange>[2:2]</bitRange>
            </field>
            <field>
              <name>SRSSCHG</name>
              <description>Session request success status change</description>
              <bitRange>[8:8]</bitRange>
            </field>
            <field>
              <name>HNSSCHG</name>
              <description>Host negotiation success status change</description>
              <bitRange>[9:9]</bitRange>
            </field>
            <field>
              <name>HNGDET</name>
              <description>Host negotiation detected</description>
              <bitRange>[17:17]</bitRange>
            </field>
            <field>
              <name>ADTOCHG</name>
              <description>A-device timeout change</description>
              <bitRange>[18:18]</bitRange>
            </field>
            <field>
              <name>DBCDNE</name>
              <description>Debounce done</description>
              <bitRange>[19:19]</bitRange>
            </field>
          </fields>
        </register>
        <register>
          <name>FS_GAHBCFG</name>
          <description>OTG_FS AHB configuration register (OTG_FS_GAHBCFG)</description>
          <addressOffset>0x8</addressOffset>
          <fields>
            <field>
              <name>GINT</name>
              <description>Global interrupt mask</description>
              <bitRange>[0:0]</bitRange>
            </field>
            <field>
              <name>TXFELVL</name>
              <description>TxFIFO empty level</description>
              <bitRange>[7:7]</bitRange>
            </field>
            <field>
              <name>PTXFELVL</name>
              <description>Periodic TxFIFO empty level</description>
              <bitRange>[8:8]</bitRange>
            </field>
          </fields>
        </register>
        <register>
          <name>FS_GUSBCFG</name>
          <description>OTG_FS USB configuration register (OTG_FS_GUSBCFG)</description>
          <addressOffset>0xC</addressOffset>
          <fields>
            <field>
              <name>TOCAL</name>
              <description>FS timeout calibration</description>
              <bitRange>[2:0]</bitRange>
            </field>
            <field>
              <name>PHYSEL</name>
              <description>Full Speed serial transceiver select</description>
              <bitRange>[7:7]</bitRange>
            </field>
            <field>
              <name>SRPCAP</name>
              <description>SRP-capable</description>
              <bitRange>[8:8]</bitRange>
            </field>
            <field>
              <name>HNPCAP</name>
              <description>HNP-capable</description>
              <bitRange>[9:9]</bitRange>
            </field>
            <field>
              <name>TRDT</name>
              <description>USB turnaround time</description>
              <bitRange>[13:10]</bitRange>
            </field>
            <field>
              <name>FHMOD</name>
              <description>Force host mode</description>
              <bitRange>[29:29]</bitRange>
            </field>
            <field>
              <name>FDMOD</name>
              <description>Force device mode</description>
              <bitRange>[30:30]</bitRange>
            </field>
            <field>
              <name>CTXPKT</name>
              <description>Corrupt Tx packet</description>
              <bitRange>[31:31]</bitRange>
            </field>
          </fields>
        </register>
        <register>
          <name>FS_GRSTCTL</name>
          <description>OTG_FS reset register (OTG_FS_GRSTCTL)</description>
          <addressOffset>0x10</addressOffset>
          <fields>
            <field>
              <name>CSRST</name>
              <description>Core soft reset</description>
              <bitRange>[0:0]</bitRange>
            </field>
            <field>
              <name>HSRST</name>
              <description>HCLK soft reset</description>
              <bitRange>[1:1]</bitRange>
            </field>
            <field>
              <name>FCRST</name>
              <description>Host frame counter reset</description>
              <bitRange>[2:2]</bitRange>
            </field>
            <field>
              <name>RXFFLSH</name>
              <description>RxFIFO flush</description>
              <bitRange>[4:4]</bitRange>
            </field>
            <field>
              <name>TXFFLSH</name>
              <description>TxFIFO flush</description>
              <bitRange>[5:5]</bitRange>
            </field>
            <field>
              <name>TXFNUM</name>
              <description>TxFIFO number</description>
              <bitRange>[10:6]</bitRange>
            </field>
            <field>
              <name>AHBIDL</name>
              <description>AHB master idle</description>
              <bitRange>[31:31]</bitRange>
              <access>read-only</access>
            </field>
          </fields>
        </register>
        <register>
          <name>FS_GINTSTS</name>
          <description>OTG_FS core interrupt register (OTG_FS_GINTSTS)</description>
          <addressOffset>0x14</addressOffset>
          <fields>
            <field>
              <name>CMOD</name>
              <description>Current mode of operation</description>
              <bitRange>[0:0]</bitRange>
              <access>read-only</access>
            </field>
            <field>
              <name>MMIS</name>
              <description>Mode mismatch interrupt</description>
              <bitRange>[1:1]</bitRange>
            </field>
            <field>
              <name>OTGINT</name>
              <description>OTG interrupt</description>
              <bitRange>[2:2]</bitRange>
              <access>read-only</access>
            </field>
            <field>
              <name>SOF</name>
              <description>Start of frame</description>
              <bitRange>[3:3]</bitRange>
            </field>
            <field>
              <name>RXFLVL</name>
              <description>RxFIFO non-empty</description>
              <bitRange>[4:4]</bitRange>
              <access>read-only</access>
            </field>
            <field>
              <name>NPTXFE</name>
              <description>Non-periodic TxFIFO empty</description>
              <bitRange>[5:5]</bitRange>
              <access>read-only</access>
            </field>
            <field>
              <name>GINAKEFF</name>
              <description>Global IN non-periodic NAK effective</description>
              <bitRange>[6:6]</bitRange>
              <access>read-only</access>
            </field>
            <field>
              <name>GOUTNAKEFF</name>
              <description>Global OUT NAK effective</description>
              <bitRange>[7:7]</bitRange>
              <access>read-only</access>
            </field>
            <field>
              <name>ESUSP</name>
              <description>Early suspend</description>
              <bitRange>[10:10]</bitRange>
            </field>
            <field>
              <name>USBSUSP</name>
              <description>USB suspend</description>
              <bitRange>[11:11]</bitRange>
            </field>
            <field>
              <name>USBRST</name>
              <description>USB reset</description>
              <bitRange>[12:12]</bitRange>
            </field>
            <field>
              <name>ENUMDNE</name>
              <description>Enumeration done</description>
              <bitRange>[13:13]</bitRange>
            </field>
            <field>
              <name>ISOODRP</name>
              <description>Isochronous OUT packet dropped interrupt</description>
              <bitRange>[14:14]</bitRange>
            </field>
            <field>
              <name>EOPF</name>
              <description>End of periodic frame interrupt</description>
              <bitRange>[15:15]</bitRange>
            </field>
            <field>
              <name>IEPINT</name>
              <description>IN endpoint interrupt</description>
              <bitRange>[18:18]</bitRange>
              <access>read-only</access>
            </field>
            <field>
              <name>OEPINT</name>
              <description>OUT endpoint interrupt</description>
              <bitRange>[19:19]</bitRange>
              <access>read-only</access>
            </field>
            <field>
              <name>IISOIXFR</name>
              <description>Incomplete isochronous IN transfer</description>
              <bitRange>[20:20]</bitRange>
            </field>
            <field>
              <name>IPXFR_INCOMPISOOUT</name>
              <description>Incomplete periodic transfer(Host mode)/Incomplete isochronous OUT transfer(Device mode)</description>
              <bitRange>[21:21]</bitRange>
            </field>
            <field>
              <name>HPRTINT</name>
              <description>Host port interrupt</description>
              <bitRange>[24:24]</bitRange>
              <access>read-only</access>
            </field>
            <field>
              <name>HCINT</name>
              <description>Host channels interrupt</description>
              <bitRange>[25:25]</bitRange>
              <access>read-only</access>
            </field>
            <field>
              <name>PTXFE</name>
              <description>Periodic TxFIFO empty</description>
              <bitRange>[26:26]</bitRange>
              <access>read-only</access>
            </field>
            <field>
              <name>CIDSCHG</name>
              <description>Connector ID status change</description>
              <bitRange>[28:28]</bitRange>
            </field>
            <field>
              <name>DISCINT</name>
              <description>Disconnect detected interrupt</description>
              <bitRange>[29:29]</bitRange>
            </field>
            <field>
              <name>SRQINT</name>
              <description>Session request/new session detected interrupt</description>
              <bitRange>[30:30]</bitRange>
            </field>
            <field>
              <name>WKUPINT</name>
              <description>Resume/remote wakeup detected interrupt</description>
              <bitRange>[31:31]</bitRange>
            </field>
          </fields>
        </register>
        <register>
          <name>FS_GINTMSK</name>
          <description>OTG_FS interrupt mask register (OTG_FS_GINTMSK)</description>
          <addressOffset>0x18</addressOffset>
          <fields>
            <field>
              <name>MMISM</name>
              <description>Mode mismatch interrupt mask</description>
              <bitRange>[1:1]</bitRange>
            </field>
            <field>
              <name>OTGINT</name>
              <description>OTG interrupt mask</description>
              <bitRange>[2:2]</bitRange>
            </field>
            <field>
              <name>SOFM</name>
              <description>Start of frame mask</description>
              <bitRange>[3:3]</bitRange>
            </field>
            <field>
              <name>RXFLVLM</name>
              <description>Receive FIFO non-empty mask</description>
              <bitRange>[4:4]</bitRange>
            </field>
            <field>
              <name>NPTXFEM</name>
              <description>Non-periodic TxFIFO empty mask</description>
              <bitRange>[5:5]</bitRange>
            </field>
            <field>
              <name>GINAKEFFM</name>
              <description>Global non-periodic IN NAK effective mask</description>
              <bitRange>[6:6]</bitRange>
            </field>
            <field>
              <name>GONAKEFFM</name>
              <description>Global OUT NAK effective mask</description>
              <bitRange>[7:7]</bitRange>
            </field>
            <field>
              <name>ESUSPM</name>
              <description>Early suspend mask</description>
              <bitRange>[10:10]</bitRange>
            </field>
            <field>
              <name>USBSUSPM</name>
              <description>USB suspend mask</description>
              <bitRange>[11:11]</bitRange>
            </field>
            <field>
              <name>USBRST</name>
              <description>USB reset mask</description>
              <bitRange>[12:12]</bitRange>
            </field>
            <field>
              <name>ENUMDNEM</name>
              <description>Enumeration done mask</description>
              <bitRange>[13:13]</bitRange>
            </field>
            <field>
              <name>ISOODRPM</name>
              <description>Isochronous OUT packet dropped interrupt mask</description>
              <bitRange>[14:14]</bitRange>
            </field>
            <field>
              <name>EOPFM</name>
              <description>End of periodic frame interrupt mask</description>
              <bitRange>[15:15]</bitRange>
            </field>
            <field>
              <name>EPMISM</name>
              <description>Endpoint mismatch interrupt mask</description>
              <bitRange>[17:17]</bitRange>
            </field>
            <field>
              <name>IEPINT</name>
              <description>IN endpoints interrupt mask</description>
              <bitRange>[18:18]</bitRange>
            </field>
            <field>
              <name>OEPINT</name>
              <description>OUT endpoints interrupt mask</description>
              <bitRange>[19:19]</bitRange>
            </field>
            <field>
              <name>IISOIXFRM</name>
              <description>Incomplete isochronous IN transfer mask</description>
              <bitRange>[20:20]</bitRange>
            </field>
            <field>
              <name>IPXFRM_IISOOXFRM</name>
              <description>Incomplete periodic transfer mask(Host mode)/Incomplete isochronous OUT transfer mask(Device mode)</description>
              <bitRange>[21:21]</bitRange>
            </field>
            <field>
              <name>PRTIM</name>
              <description>Host port interrupt mask</description>
              <bitRange>[24:24]</bitRange>
              <access>read-only</access>
            </field>
            <field>
              <name>HCIM</name>
              <description>Host channels interrupt mask</description>
              <bitRange>[25:25]</bitRange>
            </field>
            <field>
              <name>PTXFEM</name>
              <description>Periodic TxFIFO empty mask</description>
              <bitRange>[26:26]</bitRange>
            </field>
            <field>
              <name>CIDSCHGM</name>
              <description>Connector ID status change mask</description>
              <bitRange>[28:28]</bitRange>
            </field>
            <field>
              <name>DISCINT</name>
              <description>Disconnect detected interrupt mask</description>
              <bitRange>[29:29]</bitRange>
            </field>
            <field>
              <name>SRQIM</name>
              <description>Session request/new session detected interrupt mask</description>
              <bitRange>[30:30]</bitRange>
            </field>
            <field>
              <name>WUIM</name>
              <description>Resume/remote wakeup detected interrupt mask</description>
              <bitRange>[31:31]</bitRange>
            </field>
          </fields>
        </register>
        <register>
          <name>FS_GRXSTSR_DEVICE</name>
          <addressOffset>0x1C</addressOffset>
          <fields>
            <field>
              <name>EPNUM</name>
              <description>Endpoint number</description>
              <bitRange>[3:0]</bitRange>
              <access>read-only</access>
            </field>
            <field>
              <name>BCNT</name>
              <description>Byte count</description>
              <bitRange>[14:4]</bitRange>
              <access>read-only</access>
            </field>
            <field>
              <name>DPID</name>
              <description>Data PID</description>
              <bitRange>[16:15]</bitRange>
              <access>read-only</access>
            </field>
            <field>
              <name>PKTSTS</name>
              <description>Packet status</description>
              <bitRange>[20:17]</bitRange>
              <access>read-only</access>
            </field>
            <field>
              <name>FRMNUM</name>
              <description>Frame number</description>
              <bitRange>[24:21]</bitRange>
              <access>read-only</access>
            </field>
          </fields>
        </register>
        <register>
          <name>FS_GRXSTSR_HOST</name>
          <alternateRegister>FS_GRXSTSR_DEVICE</alternateRegister>
          <addressOffset>0x1C</addressOffset>
          <fields>
            <field>
              <name>EPNUM</name>
              <description>Endpoint number</description>
              <bitRange>[3:0]</bitRange>
              <access>read-only</access>
            </field>
            <field>
              <name>BCNT</name>
              <description>Byte count</description>
              <bitRange>[14:4]</bitRange>
              <access>read-only</access>
            </field>
            <field>
              <name>DPID</name>
              <description>Data PID</description>
              <bitRange>[16:15]</bitRange>
              <access>read-only</access>
            </field>
            <field>
              <name>PKTSTS</name>
              <description>Packet status</description>
              <bitRange>[20:17]</bitRange>
              <access>read-only</access>
            </field>
            <field>
              <name>FRMNUM</name>
              <description>Frame number</description>
              <bitRange>[24:21]</bitRange>
              <access>read-only</access>
            </field>
          </fields>
        </register>
        <register>
          <name>FS_GRXFSIZ</name>
          <description>OTG_FS Receive FIFO size register (OTG_FS_GRXFSIZ)</description>
          <addressOffset>0x24</addressOffset>
          <fields>
            <field>
              <name>RXFD</name>
              <description>RxFIFO depth</description>
              <bitRange>[15:0]</bitRange>
            </field>
          </fields>
        </register>
        <register>
          <name>FS_GNPTXFSIZ_DEVICE</name>
          <addressOffset>0x28</addressOffset>
          <fields>
            <field>
              <name>TX0FSA</name>
              <description>Endpoint 0 transmit RAM start address</description>
              <bitRange>[15:0]</bitRange>
            </field>
            <field>
              <name>TX0FD</name>
              <description>Endpoint 0 TxFIFO depth</description>
              <bitRange>[31:16]</bitRange>
            </field>
          </fields>
        </register>
        <register>
          <name>FS_GNPTXFSIZ_HOST</name>
          <alternateRegister>FS_GNPTXFSIZ_DEVICE</alternateRegister>
          <addressOffset>0x28</addressOffset>
          <fields>
            <field>
              <name>NPTXFSA</name>
              <description>Non-periodic transmit RAM start address</description>
              <bitRange>[15:0]</bitRange>
            </field>
            <field>
              <name>NPTXFD</name>
              <description>Non-periodic TxFIFO depth</description>
              <bitRange>[31:16]</bitRange>
            </field>
          </fields>
        </register>
        <register>
          <name>FS_GNPTXSTS</name>
          <description>OTG_FS non-periodic transmit FIFO/queue status register (OTG_FS_GNPTXSTS)</description>
          <addressOffset>0x2C</addressOffset>
          <fields>
            <field>
              <name>NPTXFSAV</name>
              <description>Non-periodic TxFIFO space available</description>
              <bitRange>[15:0]</bitRange>
              <access>read-only</access>
            </field>
            <field>
              <name>NPTQXSAV</name>
              <description>Non-periodic transmit request queue space available</description>
              <bitRange>[23:16]</bitRange>
              <access>read-only</access>
            </field>
            <field>
              <name>NPTXQTOP</name>
              <description>Top of the non-periodic transmit request queue</description>
              <bitRange>[30:24]</bitRange>
              <access>read-only</access>
            </field>
          </fields>
        </register>
        <register>
          <name>FS_GCCFG</name>
          <description>OTG_FS general core configuration register (OTG_FS_GCCFG)</description>
          <addressOffset>0x38</addressOffset>
          <fields>
            <field>
              <name>PWRDWN</name>
              <description>Power down</description>
              <bitRange>[16:16]</bitRange>
            </field>
            <field>
              <name>VBUSASEN</name>
              <description>Enable the VBUS sensing device</description>
              <bitRange>[18:18]</bitRange>
            </field>
            <field>
              <name>VBUSBSEN</name>
              <description>Enable the VBUS sensing device</description>
              <bitRange>[19:19]</bitRange>
            </field>
            <field>
              <name>SOFOUTEN</name>
              <description>SOF output enable</description>
              <bitRange>[20:20]</bitRange>
            </field>
          </fields>
        </register>
        <register>
          <name>FS_CID</name>
          <description>core ID register</description>
          <addressOffset>0x3C</addressOffset>
          <fields>
            <field>
              <name>PRODUCT_ID</name>
              <description>Product ID field</description>
              <bitRange>[31:0]</bitRange>
            </field>
          </fields>
        </register>
        <register>
          <name>FS_HPTXFSIZ</name>
          <description>OTG_FS Host periodic transmit FIFO size register (OTG_FS_HPTXFSIZ)</description>
          <addressOffset>0x100</addressOffset>
          <fields>
            <field>
              <name>PTXSA</name>
              <description>Host periodic TxFIFO start address</description>
              <bitRange>[15:0]</bitRange>
            </field>
            <field>
              <name>PTXFSIZ</name>
              <description>Host periodic TxFIFO depth</description>
              <bitRange>[31:16]</bitRange>
            </field>
          </fields>
        </register>
        <register>
          <name>FS_DIEPTXF1</name>
          <description>OTG_FS device IN endpoint transmit FIFO size register (OTG_FS_DIEPTXF2)</description>
          <addressOffset>0x104</addressOffset>
          <fields>
            <field>
              <name>INEPTXSA</name>
              <description>IN endpoint FIFO2 transmit RAM start address</description>
              <bitRange>[15:0]</bitRange>
            </field>
            <field>
              <name>INEPTXFD</name>
              <description>IN endpoint TxFIFO depth</description>
              <bitRange>[31:16]</bitRange>
            </field>
          </fields>
        </register>
        <register>
          <name>FS_DIEPTXF2</name>
          <description>OTG_FS device IN endpoint transmit FIFO size register (OTG_FS_DIEPTXF3)</description>
          <addressOffset>0x108</addressOffset>
          <fields>
            <field>
              <name>INEPTXSA</name>
              <description>IN endpoint FIFO3 transmit RAM start address</description>
              <bitRange>[15:0]</bitRange>
            </field>
            <field>
              <name>INEPTXFD</name>
              <description>IN endpoint TxFIFO depth</description>
              <bitRange>[31:16]</bitRange>
            </field>
          </fields>
        </register>
        <register>
          <name>FS_DIEPTXF3</name>
          <description>OTG_FS device IN endpoint transmit FIFO size register (OTG_FS_DIEPTXF4)</description>
          <addressOffset>0x10C</addressOffset>
          <fields>
            <field>
              <name>INEPTXSA</name>
              <description>IN endpoint FIFO4 transmit RAM start address</description>
              <bitRange>[15:0]</bitRange>
            </field>
            <field>
              <name>INEPTXFD</name>
              <description>IN endpoint TxFIFO depth</description>
              <bitRange>[31:16]</bitRange>
            </field>
          </fields>
        </register>
      </registers>
    </peripheral>
    <peripheral>
      <name>USB1_OTG_HOST</name>
      <description>USB on the go full speed</description>
      <baseAddress>0x48040400</baseAddress>
      <addressBlock>
        <offset>0x0</offset>
        <size>0x400</size>
        <usage>registers</usage>
      </addressBlock>
      <registers>
        <register>
          <name>FS_HCFG</name>
          <description>OTG_FS host configuration register (OTG_FS_HCFG)</description>
          <addressOffset>0x0</addressOffset>
          <fields>
            <field>
              <name>FSLSPCS</name>
              <description>FS/LS PHY clock select</description>
              <bitRange>[1:0]</bitRange>
            </field>
            <field>
              <name>FSLSS</name>
              <description>FS- and LS-only support</description>
              <bitRange>[2:2]</bitRange>
              <access>read-only</access>
            </field>
          </fields>
        </register>
        <register>
          <name>HFIR</name>
          <description>OTG_FS Host frame interval register</description>
          <addressOffset>0x4</addressOffset>
          <fields>
            <field>
              <name>FRIVL</name>
              <description>Frame interval</description>
              <bitRange>[15:0]</bitRange>
            </field>
          </fields>
        </register>
        <register>
          <name>FS_HFNUM</name>
          <description>OTG_FS host frame number/frame time remaining register (OTG_FS_HFNUM)</description>
          <addressOffset>0x8</addressOffset>
          <fields>
            <field>
              <name>FRNUM</name>
              <description>Frame number</description>
              <bitRange>[15:0]</bitRange>
              <access>read-only</access>
            </field>
            <field>
              <name>FTREM</name>
              <description>Frame time remaining</description>
              <bitRange>[31:16]</bitRange>
              <access>read-only</access>
            </field>
          </fields>
        </register>
        <register>
          <name>FS_HPTXSTS</name>
          <description>OTG_FS_Host periodic transmit FIFO/queue status register (OTG_FS_HPTXSTS)</description>
          <addressOffset>0x10</addressOffset>
          <fields>
            <field>
              <name>PTXFSAVL</name>
              <description>Periodic transmit data FIFO space available</description>
              <bitRange>[15:0]</bitRange>
            </field>
            <field>
              <name>PTXQSAV</name>
              <description>Periodic transmit request queue space available</description>
              <bitRange>[23:16]</bitRange>
              <access>read-only</access>
            </field>
            <field>
              <name>PTXQTOP</name>
              <description>Top of the periodic transmit request queue</description>
              <bitRange>[31:24]</bitRange>
              <access>read-only</access>
            </field>
          </fields>
        </register>
        <register>
          <name>HAINT</name>
          <description>OTG_FS Host all channels interrupt register</description>
          <addressOffset>0x14</addressOffset>
          <fields>
            <field>
              <name>HAINT</name>
              <description>Channel interrupts</description>
              <bitRange>[15:0]</bitRange>
              <access>read-only</access>
            </field>
          </fields>
        </register>
        <register>
          <name>HAINTMSK</name>
          <description>OTG_FS host all channels interrupt mask register</description>
          <addressOffset>0x18</addressOffset>
          <fields>
            <field>
              <name>HAINTM</name>
              <description>Channel interrupt mask</description>
              <bitRange>[15:0]</bitRange>
            </field>
          </fields>
        </register>
        <register>
          <name>FS_HPRT</name>
          <description>OTG_FS host port control and status register (OTG_FS_HPRT)</description>
          <addressOffset>0x40</addressOffset>
          <fields>
            <field>
              <name>PCSTS</name>
              <description>Port connect status</description>
              <bitRange>[0:0]</bitRange>
              <access>read-only</access>
            </field>
            <field>
              <name>PCDET</name>
              <description>Port connect detected</description>
              <bitRange>[1:1]</bitRange>
            </field>
            <field>
              <name>PENA</name>
              <description>Port enable</description>
              <bitRange>[2:2]</bitRange>
            </field>
            <field>
              <name>PENCHNG</name>
              <description>Port enable/disable change</description>
              <bitRange>[3:3]</bitRange>
            </field>
            <field>
              <name>POCA</name>
              <description>Port overcurrent active</description>
              <bitRange>[4:4]</bitRange>
              <access>read-only</access>
            </field>
            <field>
              <name>POCCHNG</name>
              <description>Port overcurrent change</description>
              <bitRange>[5:5]</bitRange>
            </field>
            <field>
              <name>PRES</name>
              <description>Port resume</description>
              <bitRange>[6:6]</bitRange>
            </field>
            <field>
              <name>PSUSP</name>
              <description>Port suspend</description>
              <bitRange>[7:7]</bitRange>
            </field>
            <field>
              <name>PRST</name>
              <description>Port reset</description>
              <bitRange>[8:8]</bitRange>
            </field>
            <field>
              <name>PLSTS</name>
              <description>Port line status</description>
              <bitRange>[11:10]</bitRange>
              <access>read-only</access>
            </field>
            <field>
              <name>PPWR</name>
              <description>Port power</description>
              <bitRange>[12:12]</bitRange>
            </field>
            <field>
              <name>PTCTL</name>
              <description>Port test control</description>
              <bitRange>[16:13]</bitRange>
            </field>
            <field>
              <name>PSPD</name>
              <description>Port speed</description>
              <bitRange>[18:17]</bitRange>
              <access>read-only</access>
            </field>
          </fields>
        </register>
        <register>
          <name>FS_HCCHAR0</name>
          <description>OTG_FS host channel-0 characteristics register (OTG_FS_HCCHAR0)</description>
          <addressOffset>0x100</addressOffset>
          <fields>
            <field>
              <name>MPSIZ</name>
              <description>Maximum packet size</description>
              <bitRange>[10:0]</bitRange>
            </field>
            <field>
              <name>EPNUM</name>
              <description>Endpoint number</description>
              <bitRange>[14:11]</bitRange>
            </field>
            <field>
              <name>EPDIR</name>
              <description>Endpoint direction</description>
              <bitRange>[15:15]</bitRange>
            </field>
            <field>
              <name>LSDEV</name>
              <description>Low-speed device</description>
              <bitRange>[17:17]</bitRange>
            </field>
            <field>
              <name>EPTYP</name>
              <description>Endpoint type</description>
              <bitRange>[19:18]</bitRange>
            </field>
            <field>
              <name>MCNT</name>
              <description>Multicount</description>
              <bitRange>[21:20]</bitRange>
            </field>
            <field>
              <name>DAD</name>
              <description>Device address</description>
              <bitRange>[28:22]</bitRange>
            </field>
            <field>
              <name>ODDFRM</name>
              <description>Odd frame</description>
              <bitRange>[29:29]</bitRange>
            </field>
            <field>
              <name>CHDIS</name>
              <description>Channel disable</description>
              <bitRange>[30:30]</bitRange>
            </field>
            <field>
              <name>CHENA</name>
              <description>Channel enable</description>
              <bitRange>[31:31]</bitRange>
            </field>
          </fields>
        </register>
        <register>
          <name>FS_HCINT0</name>
          <description>OTG_FS host channel-0 interrupt register (OTG_FS_HCINT0)</description>
          <addressOffset>0x108</addressOffset>
          <fields>
            <field>
              <name>XFRC</name>
              <description>Transfer completed</description>
              <bitRange>[0:0]</bitRange>
            </field>
            <field>
              <name>CHH</name>
              <description>Channel halted</description>
              <bitRange>[1:1]</bitRange>
            </field>
            <field>
              <name>STALL</name>
              <description>STALL response received interrupt</description>
              <bitRange>[3:3]</bitRange>
            </field>
            <field>
              <name>NAK</name>
              <description>NAK response received interrupt</description>
              <bitRange>[4:4]</bitRange>
            </field>
            <field>
              <name>ACK</name>
              <description>ACK response received/transmitted interrupt</description>
              <bitRange>[5:5]</bitRange>
            </field>
            <field>
              <name>TXERR</name>
              <description>Transaction error</description>
              <bitRange>[7:7]</bitRange>
            </field>
            <field>
              <name>BBERR</name>
              <description>Babble error</description>
              <bitRange>[8:8]</bitRange>
            </field>
            <field>
              <name>FRMOR</name>
              <description>Frame overrun</description>
              <bitRange>[9:9]</bitRange>
            </field>
            <field>
              <name>DTERR</name>
              <description>Data toggle error</description>
              <bitRange>[10:10]</bitRange>
            </field>
          </fields>
        </register>
        <register>
          <name>FS_HCINTMSK0</name>
          <description>OTG_FS host channel-0 mask register (OTG_FS_HCINTMSK0)</description>
          <addressOffset>0x10C</addressOffset>
          <fields>
            <field>
              <name>XFRCM</name>
              <description>Transfer completed mask</description>
              <bitRange>[0:0]</bitRange>
            </field>
            <field>
              <name>CHHM</name>
              <description>Channel halted mask</description>
              <bitRange>[1:1]</bitRange>
            </field>
            <field>
              <name>STALLM</name>
              <description>STALL response received interrupt mask</description>
              <bitRange>[3:3]</bitRange>
            </field>
            <field>
              <name>NAKM</name>
              <description>NAK response received interrupt mask</description>
              <bitRange>[4:4]</bitRange>
            </field>
            <field>
              <name>ACKM</name>
              <description>ACK response received/transmitted interrupt mask</description>
              <bitRange>[5:5]</bitRange>
            </field>
            <field>
              <name>NYET</name>
              <description>response received interrupt mask</description>
              <bitRange>[6:6]</bitRange>
            </field>
            <field>
              <name>TXERRM</name>
              <description>Transaction error mask</description>
              <bitRange>[7:7]</bitRange>
            </field>
            <field>
              <name>BBERRM</name>
              <description>Babble error mask</description>
              <bitRange>[8:8]</bitRange>
            </field>
            <field>
              <name>FRMORM</name>
              <description>Frame overrun mask</description>
              <bitRange>[9:9]</bitRange>
            </field>
            <field>
              <name>DTERRM</name>
              <description>Data toggle error mask</description>
              <bitRange>[10:10]</bitRange>
            </field>
          </fields>
        </register>
        <register>
          <name>FS_HCTSIZ0</name>
          <description>OTG_FS host channel-0 transfer size register</description>
          <addressOffset>0x110</addressOffset>
          <fields>
            <field>
              <name>XFRSIZ</name>
              <description>Transfer size</description>
              <bitRange>[18:0]</bitRange>
            </field>
            <field>
              <name>PKTCNT</name>
              <description>Packet count</description>
              <bitRange>[28:19]</bitRange>
            </field>
            <field>
              <name>DPID</name>
              <description>Data PID</description>
              <bitRange>[30:29]</bitRange>
            </field>
          </fields>
        </register>
        <register>
          <name>FS_HCCHAR1</name>
          <description>OTG_FS host channel-1 characteristics register (OTG_FS_HCCHAR1)</description>
          <addressOffset>0x120</addressOffset>
          <fields>
            <field>
              <name>MPSIZ</name>
              <description>Maximum packet size</description>
              <bitRange>[10:0]</bitRange>
            </field>
            <field>
              <name>EPNUM</name>
              <description>Endpoint number</description>
              <bitRange>[14:11]</bitRange>
            </field>
            <field>
              <name>EPDIR</name>
              <description>Endpoint direction</description>
              <bitRange>[15:15]</bitRange>
            </field>
            <field>
              <name>LSDEV</name>
              <description>Low-speed device</description>
              <bitRange>[17:17]</bitRange>
            </field>
            <field>
              <name>EPTYP</name>
              <description>Endpoint type</description>
              <bitRange>[19:18]</bitRange>
            </field>
            <field>
              <name>MCNT</name>
              <description>Multicount</description>
              <bitRange>[21:20]</bitRange>
            </field>
            <field>
              <name>DAD</name>
              <description>Device address</description>
              <bitRange>[28:22]</bitRange>
            </field>
            <field>
              <name>ODDFRM</name>
              <description>Odd frame</description>
              <bitRange>[29:29]</bitRange>
            </field>
            <field>
              <name>CHDIS</name>
              <description>Channel disable</description>
              <bitRange>[30:30]</bitRange>
            </field>
            <field>
              <name>CHENA</name>
              <description>Channel enable</description>
              <bitRange>[31:31]</bitRange>
            </field>
          </fields>
        </register>
        <register>
          <name>FS_HCINT1</name>
          <description>OTG_FS host channel-1 interrupt register (OTG_FS_HCINT1)</description>
          <addressOffset>0x128</addressOffset>
          <fields>
            <field>
              <name>XFRC</name>
              <description>Transfer completed</description>
              <bitRange>[0:0]</bitRange>
            </field>
            <field>
              <name>CHH</name>
              <description>Channel halted</description>
              <bitRange>[1:1]</bitRange>
            </field>
            <field>
              <name>STALL</name>
              <description>STALL response received interrupt</description>
              <bitRange>[3:3]</bitRange>
            </field>
            <field>
              <name>NAK</name>
              <description>NAK response received interrupt</description>
              <bitRange>[4:4]</bitRange>
            </field>
            <field>
              <name>ACK</name>
              <description>ACK response received/transmitted interrupt</description>
              <bitRange>[5:5]</bitRange>
            </field>
            <field>
              <name>TXERR</name>
              <description>Transaction error</description>
              <bitRange>[7:7]</bitRange>
            </field>
            <field>
              <name>BBERR</name>
              <description>Babble error</description>
              <bitRange>[8:8]</bitRange>
            </field>
            <field>
              <name>FRMOR</name>
              <description>Frame overrun</description>
              <bitRange>[9:9]</bitRange>
            </field>
            <field>
              <name>DTERR</name>
              <description>Data toggle error</description>
              <bitRange>[10:10]</bitRange>
            </field>
          </fields>
        </register>
        <register>
          <name>FS_HCINTMSK1</name>
          <description>OTG_FS host channel-1 mask register (OTG_FS_HCINTMSK1)</description>
          <addressOffset>0x12C</addressOffset>
          <fields>
            <field>
              <name>XFRCM</name>
              <description>Transfer completed mask</description>
              <bitRange>[0:0]</bitRange>
            </field>
            <field>
              <name>CHHM</name>
              <description>Channel halted mask</description>
              <bitRange>[1:1]</bitRange>
            </field>
            <field>
              <name>STALLM</name>
              <description>STALL response received interrupt mask</description>
              <bitRange>[3:3]</bitRange>
            </field>
            <field>
              <name>NAKM</name>
              <description>NAK response received interrupt mask</description>
              <bitRange>[4:4]</bitRange>
            </field>
            <field>
              <name>ACKM</name>
              <description>ACK response received/transmitted interrupt mask</description>
              <bitRange>[5:5]</bitRange>
            </field>
            <field>
              <name>NYET</name>
              <description>response received interrupt mask</description>
              <bitRange>[6:6]</bitRange>
            </field>
            <field>
              <name>TXERRM</name>
              <description>Transaction error mask</description>
              <bitRange>[7:7]</bitRange>
            </field>
            <field>
              <name>BBERRM</name>
              <description>Babble error mask</description>
              <bitRange>[8:8]</bitRange>
            </field>
            <field>
              <name>FRMORM</name>
              <description>Frame overrun mask</description>
              <bitRange>[9:9]</bitRange>
            </field>
            <field>
              <name>DTERRM</name>
              <description>Data toggle error mask</description>
              <bitRange>[10:10]</bitRange>
            </field>
          </fields>
        </register>
        <register>
          <name>FS_HCTSIZ1</name>
          <description>OTG_FS host channel-1 transfer size register</description>
          <addressOffset>0x130</addressOffset>
          <fields>
            <field>
              <name>XFRSIZ</name>
              <description>Transfer size</description>
              <bitRange>[18:0]</bitRange>
            </field>
            <field>
              <name>PKTCNT</name>
              <description>Packet count</description>
              <bitRange>[28:19]</bitRange>
            </field>
            <field>
              <name>DPID</name>
              <description>Data PID</description>
              <bitRange>[30:29]</bitRange>
            </field>
          </fields>
        </register>
        <register>
          <name>FS_HCCHAR2</name>
          <description>OTG_FS host channel-2 characteristics register (OTG_FS_HCCHAR2)</description>
          <addressOffset>0x140</addressOffset>
          <fields>
            <field>
              <name>MPSIZ</name>
              <description>Maximum packet size</description>
              <bitRange>[10:0]</bitRange>
            </field>
            <field>
              <name>EPNUM</name>
              <description>Endpoint number</description>
              <bitRange>[14:11]</bitRange>
            </field>
            <field>
              <name>EPDIR</name>
              <description>Endpoint direction</description>
              <bitRange>[15:15]</bitRange>
            </field>
            <field>
              <name>LSDEV</name>
              <description>Low-speed device</description>
              <bitRange>[17:17]</bitRange>
            </field>
            <field>
              <name>EPTYP</name>
              <description>Endpoint type</description>
              <bitRange>[19:18]</bitRange>
            </field>
            <field>
              <name>MCNT</name>
              <description>Multicount</description>
              <bitRange>[21:20]</bitRange>
            </field>
            <field>
              <name>DAD</name>
              <description>Device address</description>
              <bitRange>[28:22]</bitRange>
            </field>
            <field>
              <name>ODDFRM</name>
              <description>Odd frame</description>
              <bitRange>[29:29]</bitRange>
            </field>
            <field>
              <name>CHDIS</name>
              <description>Channel disable</description>
              <bitRange>[30:30]</bitRange>
            </field>
            <field>
              <name>CHENA</name>
              <description>Channel enable</description>
              <bitRange>[31:31]</bitRange>
            </field>
          </fields>
        </register>
        <register>
          <name>FS_HCINT2</name>
          <description>OTG_FS host channel-2 interrupt register (OTG_FS_HCINT2)</description>
          <addressOffset>0x148</addressOffset>
          <fields>
            <field>
              <name>XFRC</name>
              <description>Transfer completed</description>
              <bitRange>[0:0]</bitRange>
            </field>
            <field>
              <name>CHH</name>
              <description>Channel halted</description>
              <bitRange>[1:1]</bitRange>
            </field>
            <field>
              <name>STALL</name>
              <description>STALL response received interrupt</description>
              <bitRange>[3:3]</bitRange>
            </field>
            <field>
              <name>NAK</name>
              <description>NAK response received interrupt</description>
              <bitRange>[4:4]</bitRange>
            </field>
            <field>
              <name>ACK</name>
              <description>ACK response received/transmitted interrupt</description>
              <bitRange>[5:5]</bitRange>
            </field>
            <field>
              <name>TXERR</name>
              <description>Transaction error</description>
              <bitRange>[7:7]</bitRange>
            </field>
            <field>
              <name>BBERR</name>
              <description>Babble error</description>
              <bitRange>[8:8]</bitRange>
            </field>
            <field>
              <name>FRMOR</name>
              <description>Frame overrun</description>
              <bitRange>[9:9]</bitRange>
            </field>
            <field>
              <name>DTERR</name>
              <description>Data toggle error</description>
              <bitRange>[10:10]</bitRange>
            </field>
          </fields>
        </register>
        <register>
          <name>FS_HCINTMSK2</name>
          <description>OTG_FS host channel-2 mask register (OTG_FS_HCINTMSK2)</description>
          <addressOffset>0x14C</addressOffset>
          <fields>
            <field>
              <name>XFRCM</name>
              <description>Transfer completed mask</description>
              <bitRange>[0:0]</bitRange>
            </field>
            <field>
              <name>CHHM</name>
              <description>Channel halted mask</description>
              <bitRange>[1:1]</bitRange>
            </field>
            <field>
              <name>STALLM</name>
              <description>STALL response received interrupt mask</description>
              <bitRange>[3:3]</bitRange>
            </field>
            <field>
              <name>NAKM</name>
              <description>NAK response received interrupt mask</description>
              <bitRange>[4:4]</bitRange>
            </field>
            <field>
              <name>ACKM</name>
              <description>ACK response received/transmitted interrupt mask</description>
              <bitRange>[5:5]</bitRange>
            </field>
            <field>
              <name>NYET</name>
              <description>response received interrupt mask</description>
              <bitRange>[6:6]</bitRange>
            </field>
            <field>
              <name>TXERRM</name>
              <description>Transaction error mask</description>
              <bitRange>[7:7]</bitRange>
            </field>
            <field>
              <name>BBERRM</name>
              <description>Babble error mask</description>
              <bitRange>[8:8]</bitRange>
            </field>
            <field>
              <name>FRMORM</name>
              <description>Frame overrun mask</description>
              <bitRange>[9:9]</bitRange>
            </field>
            <field>
              <name>DTERRM</name>
              <description>Data toggle error mask</description>
              <bitRange>[10:10]</bitRange>
            </field>
          </fields>
        </register>
        <register>
          <name>FS_HCTSIZ2</name>
          <description>OTG_FS host channel-2 transfer size register</description>
          <addressOffset>0x150</addressOffset>
          <fields>
            <field>
              <name>XFRSIZ</name>
              <description>Transfer size</description>
              <bitRange>[18:0]</bitRange>
            </field>
            <field>
              <name>PKTCNT</name>
              <description>Packet count</description>
              <bitRange>[28:19]</bitRange>
            </field>
            <field>
              <name>DPID</name>
              <description>Data PID</description>
              <bitRange>[30:29]</bitRange>
            </field>
          </fields>
        </register>
        <register>
          <name>FS_HCCHAR3</name>
          <description>OTG_FS host channel-3 characteristics register (OTG_FS_HCCHAR3)</description>
          <addressOffset>0x160</addressOffset>
          <fields>
            <field>
              <name>MPSIZ</name>
              <description>Maximum packet size</description>
              <bitRange>[10:0]</bitRange>
            </field>
            <field>
              <name>EPNUM</name>
              <description>Endpoint number</description>
              <bitRange>[14:11]</bitRange>
            </field>
            <field>
              <name>EPDIR</name>
              <description>Endpoint direction</description>
              <bitRange>[15:15]</bitRange>
            </field>
            <field>
              <name>LSDEV</name>
              <description>Low-speed device</description>
              <bitRange>[17:17]</bitRange>
            </field>
            <field>
              <name>EPTYP</name>
              <description>Endpoint type</description>
              <bitRange>[19:18]</bitRange>
            </field>
            <field>
              <name>MCNT</name>
              <description>Multicount</description>
              <bitRange>[21:20]</bitRange>
            </field>
            <field>
              <name>DAD</name>
              <description>Device address</description>
              <bitRange>[28:22]</bitRange>
            </field>
            <field>
              <name>ODDFRM</name>
              <description>Odd frame</description>
              <bitRange>[29:29]</bitRange>
            </field>
            <field>
              <name>CHDIS</name>
              <description>Channel disable</description>
              <bitRange>[30:30]</bitRange>
            </field>
            <field>
              <name>CHENA</name>
              <description>Channel enable</description>
              <bitRange>[31:31]</bitRange>
            </field>
          </fields>
        </register>
        <register>
          <name>FS_HCINT3</name>
          <description>OTG_FS host channel-3 interrupt register (OTG_FS_HCINT3)</description>
          <addressOffset>0x168</addressOffset>
          <fields>
            <field>
              <name>XFRC</name>
              <description>Transfer completed</description>
              <bitRange>[0:0]</bitRange>
            </field>
            <field>
              <name>CHH</name>
              <description>Channel halted</description>
              <bitRange>[1:1]</bitRange>
            </field>
            <field>
              <name>STALL</name>
              <description>STALL response received interrupt</description>
              <bitRange>[3:3]</bitRange>
            </field>
            <field>
              <name>NAK</name>
              <description>NAK response received interrupt</description>
              <bitRange>[4:4]</bitRange>
            </field>
            <field>
              <name>ACK</name>
              <description>ACK response received/transmitted interrupt</description>
              <bitRange>[5:5]</bitRange>
            </field>
            <field>
              <name>TXERR</name>
              <description>Transaction error</description>
              <bitRange>[7:7]</bitRange>
            </field>
            <field>
              <name>BBERR</name>
              <description>Babble error</description>
              <bitRange>[8:8]</bitRange>
            </field>
            <field>
              <name>FRMOR</name>
              <description>Frame overrun</description>
              <bitRange>[9:9]</bitRange>
            </field>
            <field>
              <name>DTERR</name>
              <description>Data toggle error</description>
              <bitRange>[10:10]</bitRange>
            </field>
          </fields>
        </register>
        <register>
          <name>FS_HCINTMSK3</name>
          <description>OTG_FS host channel-3 mask register (OTG_FS_HCINTMSK3)</description>
          <addressOffset>0x16C</addressOffset>
          <fields>
            <field>
              <name>XFRCM</name>
              <description>Transfer completed mask</description>
              <bitRange>[0:0]</bitRange>
            </field>
            <field>
              <name>CHHM</name>
              <description>Channel halted mask</description>
              <bitRange>[1:1]</bitRange>
            </field>
            <field>
              <name>STALLM</name>
              <description>STALL response received interrupt mask</description>
              <bitRange>[3:3]</bitRange>
            </field>
            <field>
              <name>NAKM</name>
              <description>NAK response received interrupt mask</description>
              <bitRange>[4:4]</bitRange>
            </field>
            <field>
              <name>ACKM</name>
              <description>ACK response received/transmitted interrupt mask</description>
              <bitRange>[5:5]</bitRange>
            </field>
            <field>
              <name>NYET</name>
              <description>response received interrupt mask</description>
              <bitRange>[6:6]</bitRange>
            </field>
            <field>
              <name>TXERRM</name>
              <description>Transaction error mask</description>
              <bitRange>[7:7]</bitRange>
            </field>
            <field>
              <name>BBERRM</name>
              <description>Babble error mask</description>
              <bitRange>[8:8]</bitRange>
            </field>
            <field>
              <name>FRMORM</name>
              <description>Frame overrun mask</description>
              <bitRange>[9:9]</bitRange>
            </field>
            <field>
              <name>DTERRM</name>
              <description>Data toggle error mask</description>
              <bitRange>[10:10]</bitRange>
            </field>
          </fields>
        </register>
        <register>
          <name>FS_HCTSIZ3</name>
          <description>OTG_FS host channel-3 transfer size register</description>
          <addressOffset>0x170</addressOffset>
          <fields>
            <field>
              <name>XFRSIZ</name>
              <description>Transfer size</description>
              <bitRange>[18:0]</bitRange>
            </field>
            <field>
              <name>PKTCNT</name>
              <description>Packet count</description>
              <bitRange>[28:19]</bitRange>
            </field>
            <field>
              <name>DPID</name>
              <description>Data PID</description>
              <bitRange>[30:29]</bitRange>
            </field>
          </fields>
        </register>
        <register>
          <name>FS_HCCHAR4</name>
          <description>OTG_FS host channel-4 characteristics register (OTG_FS_HCCHAR4)</description>
          <addressOffset>0x180</addressOffset>
          <fields>
            <field>
              <name>MPSIZ</name>
              <description>Maximum packet size</description>
              <bitRange>[10:0]</bitRange>
            </field>
            <field>
              <name>EPNUM</name>
              <description>Endpoint number</description>
              <bitRange>[14:11]</bitRange>
            </field>
            <field>
              <name>EPDIR</name>
              <description>Endpoint direction</description>
              <bitRange>[15:15]</bitRange>
            </field>
            <field>
              <name>LSDEV</name>
              <description>Low-speed device</description>
              <bitRange>[17:17]</bitRange>
            </field>
            <field>
              <name>EPTYP</name>
              <description>Endpoint type</description>
              <bitRange>[19:18]</bitRange>
            </field>
            <field>
              <name>MCNT</name>
              <description>Multicount</description>
              <bitRange>[21:20]</bitRange>
            </field>
            <field>
              <name>DAD</name>
              <description>Device address</description>
              <bitRange>[28:22]</bitRange>
            </field>
            <field>
              <name>ODDFRM</name>
              <description>Odd frame</description>
              <bitRange>[29:29]</bitRange>
            </field>
            <field>
              <name>CHDIS</name>
              <description>Channel disable</description>
              <bitRange>[30:30]</bitRange>
            </field>
            <field>
              <name>CHENA</name>
              <description>Channel enable</description>
              <bitRange>[31:31]</bitRange>
            </field>
          </fields>
        </register>
        <register>
          <name>FS_HCINT4</name>
          <description>OTG_FS host channel-4 interrupt register (OTG_FS_HCINT4)</description>
          <addressOffset>0x188</addressOffset>
          <fields>
            <field>
              <name>XFRC</name>
              <description>Transfer completed</description>
              <bitRange>[0:0]</bitRange>
            </field>
            <field>
              <name>CHH</name>
              <description>Channel halted</description>
              <bitRange>[1:1]</bitRange>
            </field>
            <field>
              <name>STALL</name>
              <description>STALL response received interrupt</description>
              <bitRange>[3:3]</bitRange>
            </field>
            <field>
              <name>NAK</name>
              <description>NAK response received interrupt</description>
              <bitRange>[4:4]</bitRange>
            </field>
            <field>
              <name>ACK</name>
              <description>ACK response received/transmitted interrupt</description>
              <bitRange>[5:5]</bitRange>
            </field>
            <field>
              <name>TXERR</name>
              <description>Transaction error</description>
              <bitRange>[7:7]</bitRange>
            </field>
            <field>
              <name>BBERR</name>
              <description>Babble error</description>
              <bitRange>[8:8]</bitRange>
            </field>
            <field>
              <name>FRMOR</name>
              <description>Frame overrun</description>
              <bitRange>[9:9]</bitRange>
            </field>
            <field>
              <name>DTERR</name>
              <description>Data toggle error</description>
              <bitRange>[10:10]</bitRange>
            </field>
          </fields>
        </register>
        <register>
          <name>FS_HCINTMSK4</name>
          <description>OTG_FS host channel-4 mask register (OTG_FS_HCINTMSK4)</description>
          <addressOffset>0x18C</addressOffset>
          <fields>
            <field>
              <name>XFRCM</name>
              <description>Transfer completed mask</description>
              <bitRange>[0:0]</bitRange>
            </field>
            <field>
              <name>CHHM</name>
              <description>Channel halted mask</description>
              <bitRange>[1:1]</bitRange>
            </field>
            <field>
              <name>STALLM</name>
              <description>STALL response received interrupt mask</description>
              <bitRange>[3:3]</bitRange>
            </field>
            <field>
              <name>NAKM</name>
              <description>NAK response received interrupt mask</description>
              <bitRange>[4:4]</bitRange>
            </field>
            <field>
              <name>ACKM</name>
              <description>ACK response received/transmitted interrupt mask</description>
              <bitRange>[5:5]</bitRange>
            </field>
            <field>
              <name>NYET</name>
              <description>response received interrupt mask</description>
              <bitRange>[6:6]</bitRange>
            </field>
            <field>
              <name>TXERRM</name>
              <description>Transaction error mask</description>
              <bitRange>[7:7]</bitRange>
            </field>
            <field>
              <name>BBERRM</name>
              <description>Babble error mask</description>
              <bitRange>[8:8]</bitRange>
            </field>
            <field>
              <name>FRMORM</name>
              <description>Frame overrun mask</description>
              <bitRange>[9:9]</bitRange>
            </field>
            <field>
              <name>DTERRM</name>
              <description>Data toggle error mask</description>
              <bitRange>[10:10]</bitRange>
            </field>
          </fields>
        </register>
        <register>
          <name>FS_HCTSIZ4</name>
          <description>OTG_FS host channel-x transfer size register</description>
          <addressOffset>0x190</addressOffset>
          <fields>
            <field>
              <name>XFRSIZ</name>
              <description>Transfer size</description>
              <bitRange>[18:0]</bitRange>
            </field>
            <field>
              <name>PKTCNT</name>
              <description>Packet count</description>
              <bitRange>[28:19]</bitRange>
            </field>
            <field>
              <name>DPID</name>
              <description>Data PID</description>
              <bitRange>[30:29]</bitRange>
            </field>
          </fields>
        </register>
        <register>
          <name>FS_HCCHAR5</name>
          <description>OTG_FS host channel-5 characteristics register (OTG_FS_HCCHAR5)</description>
          <addressOffset>0x1A0</addressOffset>
          <fields>
            <field>
              <name>MPSIZ</name>
              <description>Maximum packet size</description>
              <bitRange>[10:0]</bitRange>
            </field>
            <field>
              <name>EPNUM</name>
              <description>Endpoint number</description>
              <bitRange>[14:11]</bitRange>
            </field>
            <field>
              <name>EPDIR</name>
              <description>Endpoint direction</description>
              <bitRange>[15:15]</bitRange>
            </field>
            <field>
              <name>LSDEV</name>
              <description>Low-speed device</description>
              <bitRange>[17:17]</bitRange>
            </field>
            <field>
              <name>EPTYP</name>
              <description>Endpoint type</description>
              <bitRange>[19:18]</bitRange>
            </field>
            <field>
              <name>MCNT</name>
              <description>Multicount</description>
              <bitRange>[21:20]</bitRange>
            </field>
            <field>
              <name>DAD</name>
              <description>Device address</description>
              <bitRange>[28:22]</bitRange>
            </field>
            <field>
              <name>ODDFRM</name>
              <description>Odd frame</description>
              <bitRange>[29:29]</bitRange>
            </field>
            <field>
              <name>CHDIS</name>
              <description>Channel disable</description>
              <bitRange>[30:30]</bitRange>
            </field>
            <field>
              <name>CHENA</name>
              <description>Channel enable</description>
              <bitRange>[31:31]</bitRange>
            </field>
          </fields>
        </register>
        <register>
          <name>FS_HCINT5</name>
          <description>OTG_FS host channel-5 interrupt register (OTG_FS_HCINT5)</description>
          <addressOffset>0x1A8</addressOffset>
          <fields>
            <field>
              <name>XFRC</name>
              <description>Transfer completed</description>
              <bitRange>[0:0]</bitRange>
            </field>
            <field>
              <name>CHH</name>
              <description>Channel halted</description>
              <bitRange>[1:1]</bitRange>
            </field>
            <field>
              <name>STALL</name>
              <description>STALL response received interrupt</description>
              <bitRange>[3:3]</bitRange>
            </field>
            <field>
              <name>NAK</name>
              <description>NAK response received interrupt</description>
              <bitRange>[4:4]</bitRange>
            </field>
            <field>
              <name>ACK</name>
              <description>ACK response received/transmitted interrupt</description>
              <bitRange>[5:5]</bitRange>
            </field>
            <field>
              <name>TXERR</name>
              <description>Transaction error</description>
              <bitRange>[7:7]</bitRange>
            </field>
            <field>
              <name>BBERR</name>
              <description>Babble error</description>
              <bitRange>[8:8]</bitRange>
            </field>
            <field>
              <name>FRMOR</name>
              <description>Frame overrun</description>
              <bitRange>[9:9]</bitRange>
            </field>
            <field>
              <name>DTERR</name>
              <description>Data toggle error</description>
              <bitRange>[10:10]</bitRange>
            </field>
          </fields>
        </register>
        <register>
          <name>FS_HCINTMSK5</name>
          <description>OTG_FS host channel-5 mask register (OTG_FS_HCINTMSK5)</description>
          <addressOffset>0x1AC</addressOffset>
          <fields>
            <field>
              <name>XFRCM</name>
              <description>Transfer completed mask</description>
              <bitRange>[0:0]</bitRange>
            </field>
            <field>
              <name>CHHM</name>
              <description>Channel halted mask</description>
              <bitRange>[1:1]</bitRange>
            </field>
            <field>
              <name>STALLM</name>
              <description>STALL response received interrupt mask</description>
              <bitRange>[3:3]</bitRange>
            </field>
            <field>
              <name>NAKM</name>
              <description>NAK response received interrupt mask</description>
              <bitRange>[4:4]</bitRange>
            </field>
            <field>
              <name>ACKM</name>
              <description>ACK response received/transmitted interrupt mask</description>
              <bitRange>[5:5]</bitRange>
            </field>
            <field>
              <name>NYET</name>
              <description>response received interrupt mask</description>
              <bitRange>[6:6]</bitRange>
            </field>
            <field>
              <name>TXERRM</name>
              <description>Transaction error mask</description>
              <bitRange>[7:7]</bitRange>
            </field>
            <field>
              <name>BBERRM</name>
              <description>Babble error mask</description>
              <bitRange>[8:8]</bitRange>
            </field>
            <field>
              <name>FRMORM</name>
              <description>Frame overrun mask</description>
              <bitRange>[9:9]</bitRange>
            </field>
            <field>
              <name>DTERRM</name>
              <description>Data toggle error mask</description>
              <bitRange>[10:10]</bitRange>
            </field>
          </fields>
        </register>
        <register>
          <name>FS_HCTSIZ5</name>
          <description>OTG_FS host channel-5 transfer size register</description>
          <addressOffset>0x1B0</addressOffset>
          <fields>
            <field>
              <name>XFRSIZ</name>
              <description>Transfer size</description>
              <bitRange>[18:0]</bitRange>
            </field>
            <field>
              <name>PKTCNT</name>
              <description>Packet count</description>
              <bitRange>[28:19]</bitRange>
            </field>
            <field>
              <name>DPID</name>
              <description>Data PID</description>
              <bitRange>[30:29]</bitRange>
            </field>
          </fields>
        </register>
        <register>
          <name>FS_HCCHAR6</name>
          <description>OTG_FS host channel-6 characteristics register (OTG_FS_HCCHAR6)</description>
          <addressOffset>0x1C0</addressOffset>
          <fields>
            <field>
              <name>MPSIZ</name>
              <description>Maximum packet size</description>
              <bitRange>[10:0]</bitRange>
            </field>
            <field>
              <name>EPNUM</name>
              <description>Endpoint number</description>
              <bitRange>[14:11]</bitRange>
            </field>
            <field>
              <name>EPDIR</name>
              <description>Endpoint direction</description>
              <bitRange>[15:15]</bitRange>
            </field>
            <field>
              <name>LSDEV</name>
              <description>Low-speed device</description>
              <bitRange>[17:17]</bitRange>
            </field>
            <field>
              <name>EPTYP</name>
              <description>Endpoint type</description>
              <bitRange>[19:18]</bitRange>
            </field>
            <field>
              <name>MCNT</name>
              <description>Multicount</description>
              <bitRange>[21:20]</bitRange>
            </field>
            <field>
              <name>DAD</name>
              <description>Device address</description>
              <bitRange>[28:22]</bitRange>
            </field>
            <field>
              <name>ODDFRM</name>
              <description>Odd frame</description>
              <bitRange>[29:29]</bitRange>
            </field>
            <field>
              <name>CHDIS</name>
              <description>Channel disable</description>
              <bitRange>[30:30]</bitRange>
            </field>
            <field>
              <name>CHENA</name>
              <description>Channel enable</description>
              <bitRange>[31:31]</bitRange>
            </field>
          </fields>
        </register>
        <register>
          <name>FS_HCINT6</name>
          <description>OTG_FS host channel-6 interrupt register (OTG_FS_HCINT6)</description>
          <addressOffset>0x1C8</addressOffset>
          <fields>
            <field>
              <name>XFRC</name>
              <description>Transfer completed</description>
              <bitRange>[0:0]</bitRange>
            </field>
            <field>
              <name>CHH</name>
              <description>Channel halted</description>
              <bitRange>[1:1]</bitRange>
            </field>
            <field>
              <name>STALL</name>
              <description>STALL response received interrupt</description>
              <bitRange>[3:3]</bitRange>
            </field>
            <field>
              <name>NAK</name>
              <description>NAK response received interrupt</description>
              <bitRange>[4:4]</bitRange>
            </field>
            <field>
              <name>ACK</name>
              <description>ACK response received/transmitted interrupt</description>
              <bitRange>[5:5]</bitRange>
            </field>
            <field>
              <name>TXERR</name>
              <description>Transaction error</description>
              <bitRange>[7:7]</bitRange>
            </field>
            <field>
              <name>BBERR</name>
              <description>Babble error</description>
              <bitRange>[8:8]</bitRange>
            </field>
            <field>
              <name>FRMOR</name>
              <description>Frame overrun</description>
              <bitRange>[9:9]</bitRange>
            </field>
            <field>
              <name>DTERR</name>
              <description>Data toggle error</description>
              <bitRange>[10:10]</bitRange>
            </field>
          </fields>
        </register>
        <register>
          <name>FS_HCINTMSK6</name>
          <description>OTG_FS host channel-6 mask register (OTG_FS_HCINTMSK6)</description>
          <addressOffset>0x1CC</addressOffset>
          <fields>
            <field>
              <name>XFRCM</name>
              <description>Transfer completed mask</description>
              <bitRange>[0:0]</bitRange>
            </field>
            <field>
              <name>CHHM</name>
              <description>Channel halted mask</description>
              <bitRange>[1:1]</bitRange>
            </field>
            <field>
              <name>STALLM</name>
              <description>STALL response received interrupt mask</description>
              <bitRange>[3:3]</bitRange>
            </field>
            <field>
              <name>NAKM</name>
              <description>NAK response received interrupt mask</description>
              <bitRange>[4:4]</bitRange>
            </field>
            <field>
              <name>ACKM</name>
              <description>ACK response received/transmitted interrupt mask</description>
              <bitRange>[5:5]</bitRange>
            </field>
            <field>
              <name>NYET</name>
              <description>response received interrupt mask</description>
              <bitRange>[6:6]</bitRange>
            </field>
            <field>
              <name>TXERRM</name>
              <description>Transaction error mask</description>
              <bitRange>[7:7]</bitRange>
            </field>
            <field>
              <name>BBERRM</name>
              <description>Babble error mask</description>
              <bitRange>[8:8]</bitRange>
            </field>
            <field>
              <name>FRMORM</name>
              <description>Frame overrun mask</description>
              <bitRange>[9:9]</bitRange>
            </field>
            <field>
              <name>DTERRM</name>
              <description>Data toggle error mask</description>
              <bitRange>[10:10]</bitRange>
            </field>
          </fields>
        </register>
        <register>
          <name>FS_HCTSIZ6</name>
          <description>OTG_FS host channel-6 transfer size register</description>
          <addressOffset>0x1D0</addressOffset>
          <fields>
            <field>
              <name>XFRSIZ</name>
              <description>Transfer size</description>
              <bitRange>[18:0]</bitRange>
            </field>
            <field>
              <name>PKTCNT</name>
              <description>Packet count</description>
              <bitRange>[28:19]</bitRange>
            </field>
            <field>
              <name>DPID</name>
              <description>Data PID</description>
              <bitRange>[30:29]</bitRange>
            </field>
          </fields>
        </register>
        <register>
          <name>FS_HCCHAR7</name>
          <description>OTG_FS host channel-7 characteristics register (OTG_FS_HCCHAR7)</description>
          <addressOffset>0x1E0</addressOffset>
          <fields>
            <field>
              <name>MPSIZ</name>
              <description>Maximum packet size</description>
              <bitRange>[10:0]</bitRange>
            </field>
            <field>
              <name>EPNUM</name>
              <description>Endpoint number</description>
              <bitRange>[14:11]</bitRange>
            </field>
            <field>
              <name>EPDIR</name>
              <description>Endpoint direction</description>
              <bitRange>[15:15]</bitRange>
            </field>
            <field>
              <name>LSDEV</name>
              <description>Low-speed device</description>
              <bitRange>[17:17]</bitRange>
            </field>
            <field>
              <name>EPTYP</name>
              <description>Endpoint type</description>
              <bitRange>[19:18]</bitRange>
            </field>
            <field>
              <name>MCNT</name>
              <description>Multicount</description>
              <bitRange>[21:20]</bitRange>
            </field>
            <field>
              <name>DAD</name>
              <description>Device address</description>
              <bitRange>[28:22]</bitRange>
            </field>
            <field>
              <name>ODDFRM</name>
              <description>Odd frame</description>
              <bitRange>[29:29]</bitRange>
            </field>
            <field>
              <name>CHDIS</name>
              <description>Channel disable</description>
              <bitRange>[30:30]</bitRange>
            </field>
            <field>
              <name>CHENA</name>
              <description>Channel enable</description>
              <bitRange>[31:31]</bitRange>
            </field>
          </fields>
        </register>
        <register>
          <name>FS_HCINT7</name>
          <description>OTG_FS host channel-7 interrupt register (OTG_FS_HCINT7)</description>
          <addressOffset>0x1E8</addressOffset>
          <fields>
            <field>
              <name>XFRC</name>
              <description>Transfer completed</description>
              <bitRange>[0:0]</bitRange>
            </field>
            <field>
              <name>CHH</name>
              <description>Channel halted</description>
              <bitRange>[1:1]</bitRange>
            </field>
            <field>
              <name>STALL</name>
              <description>STALL response received interrupt</description>
              <bitRange>[3:3]</bitRange>
            </field>
            <field>
              <name>NAK</name>
              <description>NAK response received interrupt</description>
              <bitRange>[4:4]</bitRange>
            </field>
            <field>
              <name>ACK</name>
              <description>ACK response received/transmitted interrupt</description>
              <bitRange>[5:5]</bitRange>
            </field>
            <field>
              <name>TXERR</name>
              <description>Transaction error</description>
              <bitRange>[7:7]</bitRange>
            </field>
            <field>
              <name>BBERR</name>
              <description>Babble error</description>
              <bitRange>[8:8]</bitRange>
            </field>
            <field>
              <name>FRMOR</name>
              <description>Frame overrun</description>
              <bitRange>[9:9]</bitRange>
            </field>
            <field>
              <name>DTERR</name>
              <description>Data toggle error</description>
              <bitRange>[10:10]</bitRange>
            </field>
          </fields>
        </register>
        <register>
          <name>FS_HCINTMSK7</name>
          <description>OTG_FS host channel-7 mask register (OTG_FS_HCINTMSK7)</description>
          <addressOffset>0x1EC</addressOffset>
          <fields>
            <field>
              <name>XFRCM</name>
              <description>Transfer completed mask</description>
              <bitRange>[0:0]</bitRange>
            </field>
            <field>
              <name>CHHM</name>
              <description>Channel halted mask</description>
              <bitRange>[1:1]</bitRange>
            </field>
            <field>
              <name>STALLM</name>
              <description>STALL response received interrupt mask</description>
              <bitRange>[3:3]</bitRange>
            </field>
            <field>
              <name>NAKM</name>
              <description>NAK response received interrupt mask</description>
              <bitRange>[4:4]</bitRange>
            </field>
            <field>
              <name>ACKM</name>
              <description>ACK response received/transmitted interrupt mask</description>
              <bitRange>[5:5]</bitRange>
            </field>
            <field>
              <name>NYET</name>
              <description>response received interrupt mask</description>
              <bitRange>[6:6]</bitRange>
            </field>
            <field>
              <name>TXERRM</name>
              <description>Transaction error mask</description>
              <bitRange>[7:7]</bitRange>
            </field>
            <field>
              <name>BBERRM</name>
              <description>Babble error mask</description>
              <bitRange>[8:8]</bitRange>
            </field>
            <field>
              <name>FRMORM</name>
              <description>Frame overrun mask</description>
              <bitRange>[9:9]</bitRange>
            </field>
            <field>
              <name>DTERRM</name>
              <description>Data toggle error mask</description>
              <bitRange>[10:10]</bitRange>
            </field>
          </fields>
        </register>
        <register>
          <name>FS_HCTSIZ7</name>
          <description>OTG_FS host channel-7 transfer size register</description>
          <addressOffset>0x1F0</addressOffset>
          <fields>
            <field>
              <name>XFRSIZ</name>
              <description>Transfer size</description>
              <bitRange>[18:0]</bitRange>
            </field>
            <field>
              <name>PKTCNT</name>
              <description>Packet count</description>
              <bitRange>[28:19]</bitRange>
            </field>
            <field>
              <name>DPID</name>
              <description>Data PID</description>
              <bitRange>[30:29]</bitRange>
            </field>
          </fields>
        </register>
      </registers>
    </peripheral>
    <peripheral>
      <name>USB1_OTG_PWRCLK</name>
      <description>USB on the go full speed</description>
      <baseAddress>0x48040E00</baseAddress>
      <addressBlock>
        <offset>0x0</offset>
        <size>0x400</size>
        <usage>registers</usage>
      </addressBlock>
      <registers>
        <register>
          <name>FS_PCGCCTL</name>
          <description>OTG_FS power and clock gating control register (OTG_FS_PCGCCTL)</description>
          <addressOffset>0x0</addressOffset>
          <fields>
            <field>
              <name>STPPCLK</name>
              <description>Stop PHY clock</description>
              <bitRange>[0:0]</bitRange>
            </field>
            <field>
              <name>GATEHCLK</name>
              <description>Gate HCLK</description>
              <bitRange>[1:1]</bitRange>
            </field>
            <field>
              <name>PHYSUSP</name>
              <description>PHY Suspended</description>
              <bitRange>[4:4]</bitRange>
            </field>
          </fields>
        </register>
      </registers>
    </peripheral>
    <peripheral derivedFrom="USB1_OTG_DEVICE">
      <name>USB2_OTG_DEVICE</name>
      <baseAddress>0x48080800</baseAddress>
    </peripheral>
    <peripheral derivedFrom="USB1_OTG_GLOBAL">
      <name>USB2_OTG_GLOBAL</name>
      <baseAddress>0x48080000</baseAddress>
    </peripheral>
    <peripheral derivedFrom="USB1_OTG_HOST">
      <name>USB2_OTG_HOST</name>
      <baseAddress>0x48080400</baseAddress>
      <interrupt>
        <name>OTG2_FS_WKUP</name>
        <value>81</value>
      </interrupt>
      <interrupt>
        <name>OTG2_FS</name>
        <value>82</value>
      </interrupt>
    </peripheral>
    <peripheral derivedFrom="USB1_OTG_PWRCLK">
      <name>USB2_OTG_PWRCLK</name>
      <baseAddress>0x48080E00</baseAddress>
    </peripheral>
    <peripheral>
      <name>WWDG</name>
      <baseAddress>0x40002C00</baseAddress>
      <addressBlock>
        <offset>0x0</offset>
        <size>0x400</size>
        <usage>registers</usage>
      </addressBlock>
      <interrupt>
        <name>WWDG</name>
        <description>Window Watchdog global interrupt</description>
        <value>0</value>
      </interrupt>
      <registers>
        <register>
          <name>CR</name>
          <addressOffset>0x0</addressOffset>
          <fields>
            <field>
              <name>T</name>
              <description>wwdg 7-bit counter</description>
              <bitRange>[6:0]</bitRange>
              <enumeratedValues>
                <enumeratedValue>
                  <name>0</name>
                  <value>1</value>
                </enumeratedValue>
                <enumeratedValue>
                  <name>1</name>
                  <value>2</value>
                </enumeratedValue>
                <enumeratedValue>
                  <name>2</name>
                  <value>4</value>
                </enumeratedValue>
                <enumeratedValue>
                  <name>3</name>
                  <value>8</value>
                </enumeratedValue>
                <enumeratedValue>
                  <name>4</name>
                  <value>16</value>
                </enumeratedValue>
                <enumeratedValue>
                  <name>5</name>
                  <value>32</value>
                </enumeratedValue>
                <enumeratedValue>
                  <name>6</name>
                  <value>64</value>
                </enumeratedValue>
              </enumeratedValues>
            </field>
            <field>
              <name>WDGA</name>
              <description>WWDG Activation</description>
              <bitRange>[7:7]</bitRange>
            </field>
          </fields>
        </register>
        <register>
          <name>CFR</name>
          <addressOffset>0x4</addressOffset>
          <fields>
            <field>
              <name>W</name>
              <description>window value</description>
              <bitRange>[6:0]</bitRange>
              <enumeratedValues>
                <enumeratedValue>
                  <name>0</name>
                  <value>1</value>
                </enumeratedValue>
                <enumeratedValue>
                  <name>1</name>
                  <value>2</value>
                </enumeratedValue>
                <enumeratedValue>
                  <name>2</name>
                  <value>4</value>
                </enumeratedValue>
                <enumeratedValue>
                  <name>3</name>
                  <value>8</value>
                </enumeratedValue>
                <enumeratedValue>
                  <name>4</name>
                  <value>16</value>
                </enumeratedValue>
                <enumeratedValue>
                  <name>5</name>
                  <value>32</value>
                </enumeratedValue>
                <enumeratedValue>
                  <name>6</name>
                  <value>64</value>
                </enumeratedValue>
              </enumeratedValues>
            </field>
            <field>
              <name>WDGTB</name>
              <description>time base</description>
              <bitRange>[8:7]</bitRange>
              <enumeratedValues>
                <enumeratedValue>
                  <name>0</name>
                  <value>1</value>
                </enumeratedValue>
                <enumeratedValue>
                  <name>1</name>
                  <value>2</value>
                </enumeratedValue>
              </enumeratedValues>
            </field>
            <field>
              <name>EWI</name>
              <description>Early wakeup interrupt</description>
              <bitRange>[9:9]</bitRange>
            </field>
          </fields>
        </register>
        <register>
          <name>SR</name>
          <addressOffset>0x8</addressOffset>
          <size>16</size>
          <fields>
            <field>
              <name>EWIF</name>
              <description>Early wakeup interrupt flag</description>
              <bitRange>[0:0]</bitRange>
            </field>
          </fields>
        </register>
      </registers>
    </peripheral>
  </peripherals>
</device>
